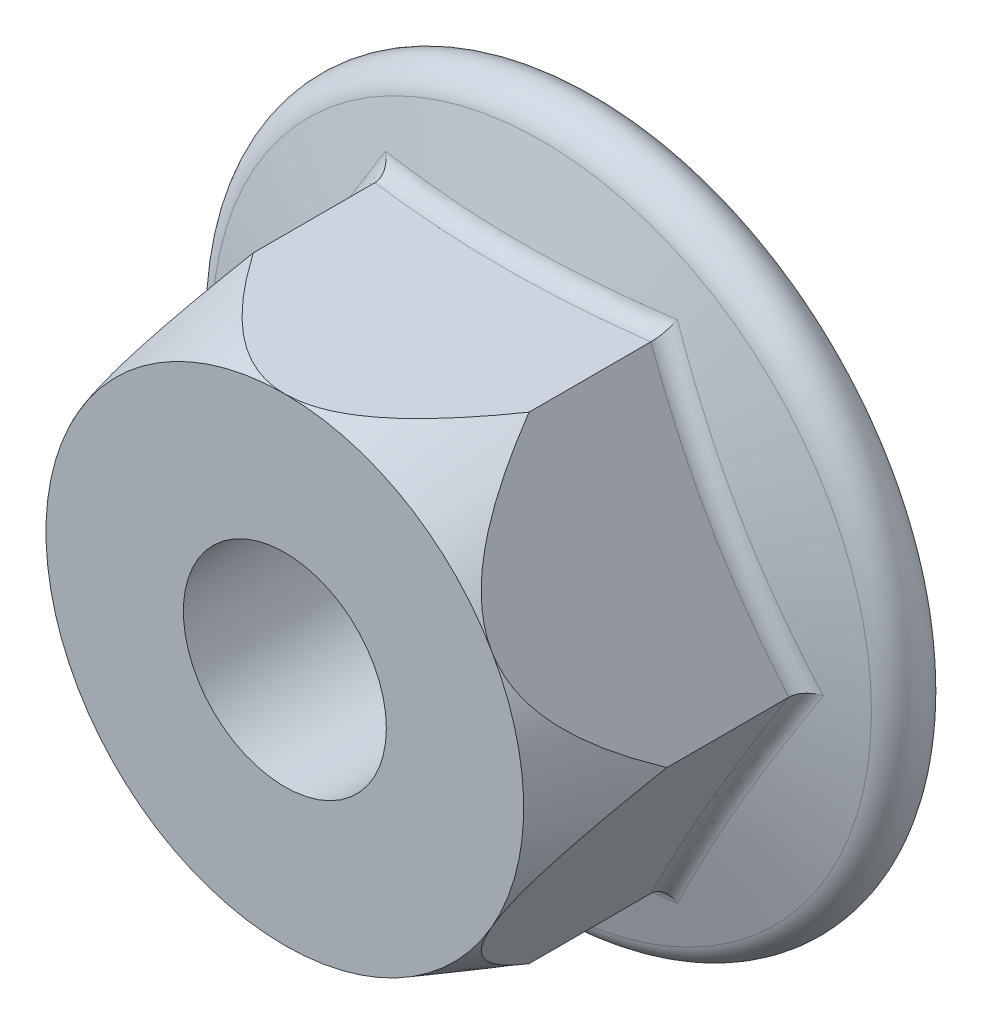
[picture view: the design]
ISO-10303-21;
HEADER;
FILE_DESCRIPTION(('STEP AP214'),'2;1');
FILE_NAME('part.step','',(''),(''),'','','');
FILE_SCHEMA(('AUTOMOTIVE_DESIGN { 1 0 10303 214 1 1 1 1 }'));
ENDSEC;
DATA;
#1=APPLICATION_CONTEXT('core data for automotive mechanical design processes');
#2=APPLICATION_PROTOCOL_DEFINITION('international standard','automotive_design',2000,#1);
#3=PRODUCT_CONTEXT('',#1,'mechanical');
#4=PRODUCT('Part','Part','',(#3));
#5=PRODUCT_RELATED_PRODUCT_CATEGORY('part','',(#4));
#6=PRODUCT_DEFINITION_FORMATION('','',#4);
#7=PRODUCT_DEFINITION_CONTEXT('part definition',#1,'design');
#8=PRODUCT_DEFINITION('design','',#6,#7);
#9=PRODUCT_DEFINITION_SHAPE('','',#8);
#10=(LENGTH_UNIT() NAMED_UNIT(*) SI_UNIT(.MILLI.,.METRE.));
#11=(NAMED_UNIT(*) PLANE_ANGLE_UNIT() SI_UNIT($,.RADIAN.));
#12=(NAMED_UNIT(*) SI_UNIT($,.STERADIAN.) SOLID_ANGLE_UNIT());
#13=UNCERTAINTY_MEASURE_WITH_UNIT(LENGTH_MEASURE(1.E-05),#10,'distance_accuracy_value','');
#14=(GEOMETRIC_REPRESENTATION_CONTEXT(3) GLOBAL_UNCERTAINTY_ASSIGNED_CONTEXT((#13)) GLOBAL_UNIT_ASSIGNED_CONTEXT((#10,
#11,#12)) REPRESENTATION_CONTEXT('',''));
#15=CARTESIAN_POINT('',(0.,0.,0.));
#16=DIRECTION('',(0.,0.,1.));
#17=DIRECTION('',(1.,0.,0.));
#18=AXIS2_PLACEMENT_3D('',#15,#16,#17);
#19=CARTESIAN_POINT('',(2.30940107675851,-4.,-5.3));
#20=DIRECTION('',(0.866025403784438,-0.5,0.));
#21=DIRECTION('',(0.5,0.866025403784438,0.));
#22=AXIS2_PLACEMENT_3D('',#19,#20,#21);
#23=PLANE('',#22);
#24=DIRECTION('',(0.,0.,1.));
#25=VECTOR('',#24,1.);
#26=CARTESIAN_POINT('',(2.30940107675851,-4.,-5.3));
#27=LINE('',#26,#25);
#28=CARTESIAN_POINT('',(2.30940107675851,-4.,-3.81737471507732));
#29=VERTEX_POINT('',#28);
#30=CARTESIAN_POINT('',(2.30940107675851,-4.,-1.78));
#31=VERTEX_POINT('',#30);
#32=EDGE_CURVE('E175',#29,#31,#27,.T.);
#33=ORIENTED_EDGE('',*,*,#32,.F.);
#34=CARTESIAN_POINT('',(-7.61123118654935,-21.1830391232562,-8.55558985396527));
#35=CARTESIAN_POINT('',(-7.57491118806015,-21.1201310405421,-8.83174684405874));
#36=CARTESIAN_POINT('',(-7.32612653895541,-21.2596298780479,-8.84536760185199));
#37=CARTESIAN_POINT('',(-7.14834835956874,-20.3813025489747,-8.31214514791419));
#38=CARTESIAN_POINT('',(-7.11245730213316,-20.3191374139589,-8.58793733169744));
#39=CARTESIAN_POINT('',(-6.863826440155,-20.4576960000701,-8.60192289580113));
#40=CARTESIAN_POINT('',(-6.68541201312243,-19.5794732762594,-8.06910132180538));
#41=CARTESIAN_POINT('',(-6.64988004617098,-19.5179301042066,-8.34442822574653));
#42=CARTESIAN_POINT('',(-6.4015282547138,-19.6556514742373,-8.35887906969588));
#43=CARTESIAN_POINT('',(-5.75902963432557,-17.9749319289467,-7.58440903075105));
#44=CARTESIAN_POINT('',(-5.72390360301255,-17.9140918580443,-7.8584468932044));
#45=CARTESIAN_POINT('',(-5.47663891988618,-18.0506377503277,-7.874186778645));
#46=CARTESIAN_POINT('',(-5.29558346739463,-17.1722196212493,-7.34276159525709));
#47=CARTESIAN_POINT('',(-5.26080405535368,-17.111979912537,-7.61612935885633));
#48=CARTESIAN_POINT('',(-5.01404777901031,-17.2476682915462,-7.63253934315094));
#49=CARTESIAN_POINT('',(-4.35666662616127,-15.545967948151,-6.85569776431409));
#50=CARTESIAN_POINT('',(-4.32238974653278,-15.4865986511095,-7.12731783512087));
#51=CARTESIAN_POINT('',(-4.07718877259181,-15.6208476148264,-7.14547551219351));
#52=CARTESIAN_POINT('',(-3.88118826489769,-14.7224152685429,-6.61034060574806));
#53=CARTESIAN_POINT('',(-3.84748393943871,-14.6640376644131,-6.88108543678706));
#54=CARTESIAN_POINT('',(-3.60292146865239,-14.7969818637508,-6.9001183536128));
#55=CARTESIAN_POINT('',(-2.93002562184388,-13.0749532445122,-6.12383947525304));
#56=CARTESIAN_POINT('',(-2.89709389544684,-13.0179138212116,-6.39216776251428));
#57=CARTESIAN_POINT('',(-2.65474442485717,-13.1488478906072,-6.41361722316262));
#58=CARTESIAN_POINT('',(-2.45434168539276,-12.2510444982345,-5.88269281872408));
#59=CARTESIAN_POINT('',(-2.4223507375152,-12.1956345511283,-6.14984390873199));
#60=CARTESIAN_POINT('',(-2.18083465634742,-12.3245802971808,-6.17247056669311));
#61=CARTESIAN_POINT('',(-1.75255773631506,-11.0355190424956,-5.53294307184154));
#62=CARTESIAN_POINT('',(-1.72021507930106,-10.9794999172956,-5.79690487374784));
#63=CARTESIAN_POINT('',(-1.48243860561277,-11.1085537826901,-5.82272081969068));
#64=CARTESIAN_POINT('',(-1.52682941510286,-10.6445461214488,-5.42136208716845));
#65=CARTESIAN_POINT('',(-1.49489405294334,-10.5892324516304,-5.6844641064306));
#66=CARTESIAN_POINT('',(-1.25791724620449,-10.7174240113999,-5.71113983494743));
#67=CARTESIAN_POINT('',(-1.07506727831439,-9.86207114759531,-5.20067849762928));
#68=CARTESIAN_POINT('',(-1.04389094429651,-9.8080721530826,-5.46179745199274));
#69=CARTESIAN_POINT('',(-0.808900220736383,-9.93467370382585,-5.49045624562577));
#70=CARTESIAN_POINT('',(-0.849033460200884,-9.47056909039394,-5.09157591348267));
#71=CARTESIAN_POINT('',(-0.81838657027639,-9.41748711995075,-5.35165029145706));
#72=CARTESIAN_POINT('',(-0.584404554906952,-9.54305316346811,-5.38135366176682));
#73=CARTESIAN_POINT('',(-0.396069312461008,-8.68601217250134,-4.87674409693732));
#74=CARTESIAN_POINT('',(-0.366445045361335,-8.63470143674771,-5.1344034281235));
#75=CARTESIAN_POINT('',(-0.134983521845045,-8.75835650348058,-5.16652184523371));
#76=CARTESIAN_POINT('',(-0.169138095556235,-8.29295577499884,-4.77102231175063));
#77=CARTESIAN_POINT('',(-0.140236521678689,-8.24289678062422,-5.02740455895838));
#78=CARTESIAN_POINT('',(0.0899417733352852,-8.36527904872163,-5.06080005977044));
#79=CARTESIAN_POINT('',(0.285345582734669,-7.50576695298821,-4.56505534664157));
#80=CARTESIAN_POINT('',(0.312820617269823,-7.45817879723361,-4.81848453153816));
#81=CARTESIAN_POINT('',(0.539752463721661,-7.57827322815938,-4.85483309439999));
#82=CARTESIAN_POINT('',(0.512898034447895,-7.11163454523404,-4.46481008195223));
#83=CARTESIAN_POINT('',(0.539373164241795,-7.06577827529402,-4.71666888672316));
#84=CARTESIAN_POINT('',(0.764637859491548,-7.18434487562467,-4.75458782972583));
#85=CARTESIAN_POINT('',(0.965655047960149,-6.32743639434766,-4.27436791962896));
#86=CARTESIAN_POINT('',(0.990117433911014,-6.28506629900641,-4.52267428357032));
#87=CARTESIAN_POINT('',(1.21118051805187,-6.40105138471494,-4.5641456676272));
#88=CARTESIAN_POINT('',(1.19084639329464,-5.93739354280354,-4.184047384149));
#89=CARTESIAN_POINT('',(1.21394070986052,-5.89739301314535,-4.43047216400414));
#90=CARTESIAN_POINT('',(1.4328377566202,-6.01170196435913,-4.47382513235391));
#91=CARTESIAN_POINT('',(1.64257926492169,-5.15496925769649,-4.01707291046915));
#92=CARTESIAN_POINT('',(1.66271797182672,-5.12008799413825,-4.25943247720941));
#93=CARTESIAN_POINT('',(1.87635689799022,-5.23168790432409,-4.30685065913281));
#94=CARTESIAN_POINT('',(1.86912112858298,-4.7625872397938,-3.94042254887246));
#95=CARTESIAN_POINT('',(1.8873877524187,-4.73094851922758,-4.18059335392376));
#96=CARTESIAN_POINT('',(2.09821883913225,-4.84102294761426,-4.23020029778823));
#97=CARTESIAN_POINT('',(2.32311926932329,-3.97623939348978,-3.80992031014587));
#98=CARTESIAN_POINT('',(2.337137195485,-3.95195963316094,-4.04600903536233));
#99=CARTESIAN_POINT('',(2.54185284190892,-4.06009928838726,-4.09969805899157));
#100=CARTESIAN_POINT('',(2.55056920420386,-3.5822845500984,-3.75598635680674));
#101=CARTESIAN_POINT('',(2.56229119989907,-3.5619814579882,-3.98996132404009));
#102=CARTESIAN_POINT('',(2.76362228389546,-3.66984429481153,-4.04576410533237));
#103=CARTESIAN_POINT('',(2.89270035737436,-2.98969600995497,-3.70029165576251));
#104=CARTESIAN_POINT('',(2.90051641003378,-2.97615820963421,-3.93207627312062));
#105=CARTESIAN_POINT('',(3.09747471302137,-3.08479578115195,-3.99006940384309));
#106=CARTESIAN_POINT('',(3.00686662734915,-2.791954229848,-3.68592836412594));
#107=CARTESIAN_POINT('',(3.0132311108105,-2.78093062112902,-3.91711556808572));
#108=CARTESIAN_POINT('',(3.20892257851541,-2.88989781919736,-3.97570611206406));
#109=CARTESIAN_POINT('',(3.23539205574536,-2.39613657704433,-3.66664521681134));
#110=CARTESIAN_POINT('',(3.23857973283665,-2.39061535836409,-3.89705602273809));
#111=CARTESIAN_POINT('',(3.4323757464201,-2.5003310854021,-3.95642296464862));
#112=CARTESIAN_POINT('',(3.34975118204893,-2.19806075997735,-3.66172391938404));
#113=CARTESIAN_POINT('',(3.35139245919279,-2.19521798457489,-3.89192321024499));
#114=CARTESIAN_POINT('',(3.544380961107,-2.30566228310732,-3.95150166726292));
#115=CARTESIAN_POINT('',(3.50978592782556,-1.92087244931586,-3.66171696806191));
#116=CARTESIAN_POINT('',(3.50913015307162,-1.92200828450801,-3.89191458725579));
#117=CARTESIAN_POINT('',(3.70152527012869,-2.03347809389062,-3.95149471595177));
#118=CARTESIAN_POINT('',(3.55546885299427,-1.8417473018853,-3.6624996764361));
#119=CARTESIAN_POINT('',(3.55416444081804,-1.84400661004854,-3.89273007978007));
#120=CARTESIAN_POINT('',(3.74642913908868,-1.95580835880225,-3.95227742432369));
#121=CARTESIAN_POINT('',(3.64682245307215,-1.68351822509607,-3.66561475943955));
#122=CARTESIAN_POINT('',(3.64421400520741,-1.68803618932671,-3.8959727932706));
#123=CARTESIAN_POINT('',(3.83632424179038,-1.80052369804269,-3.95539250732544));
#124=CARTESIAN_POINT('',(3.69249312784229,-1.60441429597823,-3.66794715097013));
#125=CARTESIAN_POINT('',(3.68924157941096,-1.61004614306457,-3.89840092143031));
#126=CARTESIAN_POINT('',(3.88131547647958,-1.72290877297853,-3.95772489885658));
#127=CARTESIAN_POINT('',(3.82950397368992,-1.36710454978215,-3.67723166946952));
#128=CARTESIAN_POINT('',(3.82436213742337,-1.37601047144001,-3.90806527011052));
#129=CARTESIAN_POINT('',(4.01644472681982,-1.49009005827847,-3.96700941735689));
#130=CARTESIAN_POINT('',(3.92080623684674,-1.20896439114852,-3.68647110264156));
#131=CARTESIAN_POINT('',(3.91445378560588,-1.21996715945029,-3.91768701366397));
#132=CARTESIAN_POINT('',(4.10670223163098,-1.33497476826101,-3.97624885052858));
#133=CARTESIAN_POINT('',(4.19477955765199,-0.734428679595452,-3.72273800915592));
#134=CARTESIAN_POINT('',(4.18503615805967,-0.751304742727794,-3.95540495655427));
#135=CARTESIAN_POINT('',(4.37816374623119,-0.869375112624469,-4.01251575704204));
#136=CARTESIAN_POINT('',(4.3771741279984,-0.418512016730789,-3.75831137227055));
#137=CARTESIAN_POINT('',(4.36539673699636,-0.438911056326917,-3.99241678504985));
#138=CARTESIAN_POINT('',(4.55971999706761,-0.559219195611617,-4.04808912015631));
#139=CARTESIAN_POINT('',(4.65065751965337,0.0551751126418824,-3.82480471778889));
#140=CARTESIAN_POINT('',(4.63549818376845,0.0289183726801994,-4.0610737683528));
#141=CARTESIAN_POINT('',(4.83278724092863,-0.0933721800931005,-4.1145824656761));
#142=CARTESIAN_POINT('',(4.74217033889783,0.213679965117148,-3.8492840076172));
#143=CARTESIAN_POINT('',(4.726080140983,0.18581092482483,-4.0863647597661));
#144=CARTESIAN_POINT('',(4.92430330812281,0.0626443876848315,-4.13906175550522));
#145=CARTESIAN_POINT('',(4.92494243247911,0.530250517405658,-3.90190705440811));
#146=CARTESIAN_POINT('',(4.90710566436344,0.499356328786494,-4.14062943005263));
#147=CARTESIAN_POINT('',(5.10728053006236,0.374525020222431,-4.19168480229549));
#148=CARTESIAN_POINT('',(5.01620168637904,0.688316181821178,-3.93005109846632));
#149=CARTESIAN_POINT('',(4.99755743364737,0.656023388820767,-4.16961875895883));
#150=CARTESIAN_POINT('',(5.19874167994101,0.530389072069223,-4.21982884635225));
#151=CARTESIAN_POINT('',(5.19824692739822,1.00362778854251,-3.9892892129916));
#152=CARTESIAN_POINT('',(5.17809955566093,0.968731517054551,-4.23053091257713));
#153=CARTESIAN_POINT('',(5.38132017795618,0.84158462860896,-4.2790669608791));
#154=CARTESIAN_POINT('',(5.28903352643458,1.16087479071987,-4.0203758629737));
#155=CARTESIAN_POINT('',(5.26818514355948,1.12476433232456,-4.26245525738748));
#156=CARTESIAN_POINT('',(5.47243781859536,0.996916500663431,-4.31015361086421));
#157=CARTESIAN_POINT('',(5.47036783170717,1.4749550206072,-4.0850307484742));
#158=CARTESIAN_POINT('',(5.44823424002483,1.43661851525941,-4.32876154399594));
#159=CARTESIAN_POINT('',(5.65451402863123,1.30742143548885,-4.37480849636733));
#160=CARTESIAN_POINT('',(5.56091558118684,1.63178832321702,-4.11859849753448));
#161=CARTESIAN_POINT('',(5.53818436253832,1.59241669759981,-4.36314658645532));
#162=CARTESIAN_POINT('',(5.74547262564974,1.46259452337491,-4.40837624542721));
#163=CARTESIAN_POINT('',(5.65136623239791,1.78845344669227,-4.15314978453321));
#164=CARTESIAN_POINT('',(5.62793136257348,1.74786306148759,-4.3984261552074));
#165=CARTESIAN_POINT('',(5.83634927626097,1.61771364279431,-4.44292753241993));
#166=(BOUNDED_SURFACE() B_SPLINE_SURFACE(3,2,((#34,#35,#36),(#37,#38,#39),(#40,#41,#42),(#43,
#44,#45),(#46,#47,#48),(#49,#50,#51),(#52,#53,#54),(#55,#56,#57),(#58,#59,#60),(#61,#62,#63),
(#64,#65,#66),(#67,#68,#69),(#70,#71,#72),(#73,#74,#75),(#76,#77,#78),(#79,#80,#81),(#82,#83,
#84),(#85,#86,#87),(#88,#89,#90),(#91,#92,#93),(#94,#95,#96),(#97,#98,#99),(#100,#101,#102),
(#103,#104,#105),(#106,#107,#108),(#109,#110,#111),(#112,#113,#114),(#115,#116,#117),(#118,#119,
#120),(#121,#122,#123),(#124,#125,#126),(#127,#128,#129),(#130,#131,#132),(#133,#134,#135),
(#136,#137,#138),(#139,#140,#141),(#142,#143,#144),(#145,#146,#147),(#148,#149,#150),(#151,#152,
#153),(#154,#155,#156),(#157,#158,#159),(#160,#161,#162),(#163,#164,#165)),.UNSPECIFIED.,.F.,
.F.,.F.) B_SPLINE_SURFACE_WITH_KNOTS((4,2,2,2,2,2,2,2,2,2,2,2,2,2,2,2,2,2,2,2,2,4),(3,3),(0.,
2.87172082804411,5.74534141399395,8.69163587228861,11.6359776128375,13.0310968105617,
14.4262276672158,15.8242453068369,17.222241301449,18.600159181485,19.978437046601,
21.3516914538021,22.0378780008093,22.7239597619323,22.9980573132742,23.272157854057,
23.8205791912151,24.9194760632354,25.4734222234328,26.0274118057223,26.5800398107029,
27.1325597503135),(0.,1.),
.UNSPECIFIED.) GEOMETRIC_REPRESENTATION_ITEM() RATIONAL_B_SPLINE_SURFACE(((1.,0.72433504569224,
1.),(1.,0.72502874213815,1.),(1.,0.725787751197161,1.),(1.,0.727541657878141,1.),(1.,
0.728536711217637,1.),(1.,0.730896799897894,1.),(1.,0.732270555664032,1.),(1.,0.73558815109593,
1.),(1.,0.737531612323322,1.),(1.,0.741117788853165,1.),(1.,0.742380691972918,1.),(1.,
0.745198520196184,1.),(1.,0.74675344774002,1.),(1.,0.750247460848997,1.),(1.,0.752187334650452,
1.),(1.,0.756556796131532,1.),(1.,0.758986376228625,1.),(1.,0.764379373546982,1.),(1.,
0.767334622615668,1.),(1.,0.773723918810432,1.),(1.,0.777158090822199,1.),(1.,0.783844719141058,
1.),(1.,0.787097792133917,1.),(1.,0.790686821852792,1.),(1.,0.791667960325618,1.),(1.,
0.79300075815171,1.),(1.,0.793352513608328,1.),(1.,0.793353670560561,1.),(1.,0.793297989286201,
1.),(1.,0.793078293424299,1.),(1.,0.792914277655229,1.),(1.,0.792266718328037,1.),(1.,
0.791627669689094,1.),(1.,0.789211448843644,1.),(1.,0.786935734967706,1.),(1.,0.783154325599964,
1.),(1.,0.78182642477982,1.),(1.,0.779132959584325,1.),(1.,0.777767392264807,1.),(1.,
0.775062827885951,1.),(1.,0.773723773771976,1.),(1.,0.771102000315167,1.),(1.,0.769819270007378,
1.),(1.,0.768581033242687,1.))) REPRESENTATION_ITEM('') SURFACE());
#167=CARTESIAN_POINT('',(-7.61123118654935,-21.1830391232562,-8.55558985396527));
#168=CARTESIAN_POINT('',(-7.14834835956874,-20.3813025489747,-8.31214514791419));
#169=CARTESIAN_POINT('',(-6.68541201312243,-19.5794732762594,-8.06910132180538));
#170=CARTESIAN_POINT('',(-5.75902963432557,-17.9749319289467,-7.58440903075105));
#171=CARTESIAN_POINT('',(-5.29558346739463,-17.1722196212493,-7.3427615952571));
#172=CARTESIAN_POINT('',(-4.35666662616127,-15.545967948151,-6.85569776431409));
#173=CARTESIAN_POINT('',(-3.88118826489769,-14.7224152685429,-6.61034060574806));
#174=CARTESIAN_POINT('',(-2.93002562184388,-13.0749532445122,-6.12383947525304));
#175=CARTESIAN_POINT('',(-2.45434168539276,-12.2510444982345,-5.88269281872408));
#176=CARTESIAN_POINT('',(-1.75255773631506,-11.0355190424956,-5.53294307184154));
#177=CARTESIAN_POINT('',(-1.52682941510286,-10.6445461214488,-5.42136208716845));
#178=CARTESIAN_POINT('',(-1.07506727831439,-9.86207114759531,-5.20067849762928));
#179=CARTESIAN_POINT('',(-0.849033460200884,-9.47056909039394,-5.09157591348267));
#180=CARTESIAN_POINT('',(-0.396069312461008,-8.68601217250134,-4.87674409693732));
#181=CARTESIAN_POINT('',(-0.169138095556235,-8.29295577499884,-4.77102231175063));
#182=CARTESIAN_POINT('',(0.285345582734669,-7.50576695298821,-4.56505534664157));
#183=CARTESIAN_POINT('',(0.512898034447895,-7.11163454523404,-4.46481008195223));
#184=CARTESIAN_POINT('',(0.965655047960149,-6.32743639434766,-4.27436791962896));
#185=CARTESIAN_POINT('',(1.19084639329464,-5.93739354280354,-4.184047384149));
#186=CARTESIAN_POINT('',(1.64257926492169,-5.15496925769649,-4.01707291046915));
#187=CARTESIAN_POINT('',(1.86912112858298,-4.7625872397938,-3.94042254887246));
#188=CARTESIAN_POINT('',(2.32311926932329,-3.97623939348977,-3.80992031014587));
#189=CARTESIAN_POINT('',(2.55056920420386,-3.5822845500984,-3.75598635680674));
#190=CARTESIAN_POINT('',(2.89270035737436,-2.98969600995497,-3.70029165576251));
#191=CARTESIAN_POINT('',(3.00686662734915,-2.791954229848,-3.68592836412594));
#192=CARTESIAN_POINT('',(3.23539205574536,-2.39613657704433,-3.66664521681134));
#193=CARTESIAN_POINT('',(3.34975118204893,-2.19806075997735,-3.66172391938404));
#194=CARTESIAN_POINT('',(3.50978592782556,-1.92087244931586,-3.66171696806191));
#195=CARTESIAN_POINT('',(3.55546885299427,-1.8417473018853,-3.6624996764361));
#196=CARTESIAN_POINT('',(3.64682245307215,-1.68351822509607,-3.66561475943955));
#197=CARTESIAN_POINT('',(3.69249312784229,-1.60441429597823,-3.66794715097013));
#198=CARTESIAN_POINT('',(3.82950397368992,-1.36710454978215,-3.67723166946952));
#199=CARTESIAN_POINT('',(3.92080623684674,-1.20896439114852,-3.68647110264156));
#200=CARTESIAN_POINT('',(4.19477955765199,-0.734428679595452,-3.72273800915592));
#201=CARTESIAN_POINT('',(4.3771741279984,-0.41851201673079,-3.75831137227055));
#202=CARTESIAN_POINT('',(4.65065751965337,0.0551751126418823,-3.82480471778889));
#203=CARTESIAN_POINT('',(4.74217033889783,0.213679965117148,-3.8492840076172));
#204=CARTESIAN_POINT('',(4.92494243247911,0.530250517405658,-3.90190705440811));
#205=CARTESIAN_POINT('',(5.01620168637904,0.688316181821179,-3.93005109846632));
#206=CARTESIAN_POINT('',(5.19824692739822,1.00362778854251,-3.9892892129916));
#207=CARTESIAN_POINT('',(5.28903352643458,1.16087479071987,-4.0203758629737));
#208=CARTESIAN_POINT('',(5.47036783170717,1.4749550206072,-4.0850307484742));
#209=CARTESIAN_POINT('',(5.56091558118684,1.63178832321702,-4.11859849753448));
#210=CARTESIAN_POINT('',(5.65136623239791,1.78845344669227,-4.15314978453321));
#211=B_SPLINE_CURVE_WITH_KNOTS('',3,(#167,#168,#169,#170,#171,#172,#173,#174,#175,#176,#177,
#178,#179,#180,#181,#182,#183,#184,#185,#186,#187,#188,#189,#190,#191,#192,#193,#194,#195,#196,
#197,#198,#199,#200,#201,#202,#203,#204,#205,#206,#207,#208,#209,#210),.UNSPECIFIED.,.F.,.F.,(4,
2,2,2,2,2,2,2,2,2,2,2,2,2,2,2,2,2,2,2,2,4),(0.,2.87172082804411,5.74534141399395,
8.69163587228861,11.6359776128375,13.0310968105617,14.4262276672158,15.8242453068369,
17.222241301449,18.600159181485,19.978437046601,21.3516914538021,22.0378780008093,
22.7239597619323,22.9980573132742,23.272157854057,23.8205791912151,24.9194760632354,
25.4734222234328,26.0274118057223,26.5800398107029,27.1325597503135),.UNSPECIFIED.);
#212=CARTESIAN_POINT('',(4.61880215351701,0.,-3.81737471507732));
#213=VERTEX_POINT('',#212);
#214=EDGE_CURVE('E329',#29,#213,#211,.T.);
#215=ORIENTED_EDGE('',*,*,#214,.T.);
#216=DIRECTION('',(0.,0.,1.));
#217=VECTOR('',#216,1.);
#218=CARTESIAN_POINT('',(4.61880215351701,0.,-5.3));
#219=LINE('',#218,#217);
#220=CARTESIAN_POINT('',(4.61880215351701,0.,-1.78));
#221=VERTEX_POINT('',#220);
#222=EDGE_CURVE('E157',#213,#221,#219,.T.);
#223=ORIENTED_EDGE('',*,*,#222,.T.);
#224=CARTESIAN_POINT('',(2.30933154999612,-4.00012042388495,-1.78020000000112));
#225=CARTESIAN_POINT('',(2.329672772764,-3.96488839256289,-1.72169220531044));
#226=CARTESIAN_POINT('',(2.35028187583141,-3.92919237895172,-1.66355827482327));
#227=CARTESIAN_POINT('',(2.3921122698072,-3.85674001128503,-1.54815677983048));
#228=CARTESIAN_POINT('',(2.41333371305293,-3.81998339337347,-1.4908894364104));
#229=CARTESIAN_POINT('',(2.47830561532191,-3.70744875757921,-1.31984609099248));
#230=CARTESIAN_POINT('',(2.52309209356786,-3.62987630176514,-1.20761921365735));
#231=CARTESIAN_POINT('',(2.61818869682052,-3.46516415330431,-0.984245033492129));
#232=CARTESIAN_POINT('',(2.66865503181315,-3.37775389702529,-0.873361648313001));
#233=CARTESIAN_POINT('',(2.77442244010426,-3.19455937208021,-0.661563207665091));
#234=CARTESIAN_POINT('',(2.82970800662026,-3.09880196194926,-0.560618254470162));
#235=CARTESIAN_POINT('',(2.9106528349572,-2.95860140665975,-0.431782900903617));
#236=CARTESIAN_POINT('',(2.93362248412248,-2.91881680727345,-0.397143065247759));
#237=CARTESIAN_POINT('',(2.98058363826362,-2.83747770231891,-0.330748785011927));
#238=CARTESIAN_POINT('',(3.00457540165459,-2.79592274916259,-0.298995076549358));
#239=CARTESIAN_POINT('',(3.07782339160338,-2.66905350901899,-0.209445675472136));
#240=CARTESIAN_POINT('',(3.12873106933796,-2.58087882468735,-0.156734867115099));
#241=CARTESIAN_POINT('',(3.22066888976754,-2.42163784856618,-0.0827968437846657));
#242=CARTESIAN_POINT('',(3.26075482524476,-2.35220697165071,-0.0569308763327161));
#243=CARTESIAN_POINT('',(3.34254671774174,-2.21053925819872,-0.0188566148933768));
#244=CARTESIAN_POINT('',(3.38425146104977,-2.1383045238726,-0.00663828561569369));
#245=CARTESIAN_POINT('',(3.46826163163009,-1.99279464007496,0.00251875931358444));
#246=CARTESIAN_POINT('',(3.5105687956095,-1.91951648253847,-0.000603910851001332));
#247=CARTESIAN_POINT('',(3.59423504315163,-1.77460229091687,-0.0218132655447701));
#248=CARTESIAN_POINT('',(3.63559318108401,-1.70296789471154,-0.0399142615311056));
#249=CARTESIAN_POINT('',(3.72775187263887,-1.54334435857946,-0.0957585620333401));
#250=CARTESIAN_POINT('',(3.77791738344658,-1.45645514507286,-0.137607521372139));
#251=CARTESIAN_POINT('',(3.87438442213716,-1.28936933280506,-0.236407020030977));
#252=CARTESIAN_POINT('',(3.92067460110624,-1.20919239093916,-0.293400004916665));
#253=CARTESIAN_POINT('',(4.00728859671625,-1.05917254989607,-0.414494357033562));
#254=CARTESIAN_POINT('',(4.04779671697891,-0.989010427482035,-0.478080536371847));
#255=CARTESIAN_POINT('',(4.1260142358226,-0.853533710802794,-0.611867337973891));
#256=CARTESIAN_POINT('',(4.16372066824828,-0.788224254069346,-0.682074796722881));
#257=CARTESIAN_POINT('',(4.23687359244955,-0.661519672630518,-0.827445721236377));
#258=CARTESIAN_POINT('',(4.27231261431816,-0.600137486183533,-0.902624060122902));
#259=CARTESIAN_POINT('',(4.34118808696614,-0.48084166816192,-1.05648002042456));
#260=CARTESIAN_POINT('',(4.37462539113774,-0.422926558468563,-1.13515612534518));
#261=CARTESIAN_POINT('',(4.44457071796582,-0.301777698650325,-1.30677603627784));
#262=CARTESIAN_POINT('',(4.48082190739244,-0.238988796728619,-1.40013569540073));
#263=CARTESIAN_POINT('',(4.55123163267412,-0.117035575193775,-1.58876843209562));
#264=CARTESIAN_POINT('',(4.58540498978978,-0.0578455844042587,-1.68401931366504));
#265=CARTESIAN_POINT('',(4.61887168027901,0.000120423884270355,-1.7802));
#266=B_SPLINE_CURVE_WITH_KNOTS('',3,(#224,#225,#226,#227,#228,#229,#230,#231,#232,#233,#234,
#235,#236,#237,#238,#239,#240,#241,#242,#243,#244,#245,#246,#247,#248,#249,#250,#251,#252,#253,
#254,#255,#256,#257,#258,#259,#260,#261,#262,#263,#264,#265),.UNSPECIFIED.,.F.,.F.,(4,2,2,2,2,2,
2,2,2,2,2,2,2,2,2,2,2,2,2,2,4),(0.,0.213777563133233,0.427608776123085,0.858145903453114,
1.30759304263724,1.75564391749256,1.92815043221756,2.10070082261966,2.44287249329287,
2.69463411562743,2.9462104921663,3.19879434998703,3.45161982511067,3.77590275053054,
4.10110434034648,4.40960953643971,4.71843682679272,5.02823407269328,5.33789828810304,
5.6924202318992,6.0440116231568),.UNSPECIFIED.);
#267=CARTESIAN_POINT('',(3.46410161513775,-2.,0.));
#268=VERTEX_POINT('',#267);
#269=EDGE_CURVE('E212',#268,#221,#266,.T.);
#270=ORIENTED_EDGE('',*,*,#269,.F.);
#271=EDGE_CURVE('E519',#31,#268,#266,.T.);
#272=ORIENTED_EDGE('',*,*,#271,.F.);
#273=EDGE_LOOP('',(#33,#215,#223,#270,#272));
#274=FACE_BOUND('',#273,.T.);
#275=ADVANCED_FACE('F35',(#274),#23,.T.);
#276=CARTESIAN_POINT('',(-2.3094010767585,-4.,-5.3));
#277=DIRECTION('',(0.,-1.,0.));
#278=DIRECTION('',(1.,0.,0.));
#279=AXIS2_PLACEMENT_3D('',#276,#277,#278);
#280=PLANE('',#279);
#281=DIRECTION('',(0.,0.,1.));
#282=VECTOR('',#281,1.);
#283=CARTESIAN_POINT('',(-2.3094010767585,-4.,-5.3));
#284=LINE('',#283,#282);
#285=CARTESIAN_POINT('',(-2.3094010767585,-4.,-3.81737471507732));
#286=VERTEX_POINT('',#285);
#287=CARTESIAN_POINT('',(-2.3094010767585,-4.,-1.78));
#288=VERTEX_POINT('',#287);
#289=EDGE_CURVE('E139',#286,#288,#284,.T.);
#290=ORIENTED_EDGE('',*,*,#289,.F.);
#291=CARTESIAN_POINT('',(-22.1112237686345,-4.00000000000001,-8.54521545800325));
#292=CARTESIAN_POINT('',(-22.0385943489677,-4.00000000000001,-8.82135013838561));
#293=CARTESIAN_POINT('',(-22.0350059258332,-4.28517781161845,-8.83499320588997));
#294=CARTESIAN_POINT('',(-21.1869548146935,-4.00000000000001,-8.30218033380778));
#295=CARTESIAN_POINT('',(-21.1151840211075,-4.00000000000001,-8.57794941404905));
#296=CARTESIAN_POINT('',(-21.1108578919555,-4.28457344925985,-8.59195808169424));
#297=CARTESIAN_POINT('',(-20.2625786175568,-4.00000000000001,-8.05954685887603));
#298=CARTESIAN_POINT('',(-20.1915266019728,-4.00000000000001,-8.33484970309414));
#299=CARTESIAN_POINT('',(-20.186614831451,-4.28391199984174,-8.34932460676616));
#300=CARTESIAN_POINT('',(-18.4128085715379,-4.00000000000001,-7.57567895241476));
#301=CARTESIAN_POINT('',(-18.3425699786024,-4.00000000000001,-7.8496906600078));
#302=CARTESIAN_POINT('',(-18.3371834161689,-4.28238013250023,-7.86545670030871));
#303=CARTESIAN_POINT('',(-17.4874144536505,-4.00000000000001,-7.33444554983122));
#304=CARTESIAN_POINT('',(-17.4178700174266,-4.,-7.60778598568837));
#305=CARTESIAN_POINT('',(-17.4119948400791,-4.28150957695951,-7.62422329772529));
#306=CARTESIAN_POINT('',(-15.6125978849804,-4.00000000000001,-6.84822064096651));
#307=CARTESIAN_POINT('',(-15.5440609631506,-4.,-7.11981074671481));
#308=CARTESIAN_POINT('',(-15.5377163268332,-4.27943938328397,-7.13799838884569));
#309=CARTESIAN_POINT('',(-14.6631600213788,-4.,-6.60328852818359));
#310=CARTESIAN_POINT('',(-14.5957695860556,-4.,-6.87400182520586));
#311=CARTESIAN_POINT('',(-14.5886140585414,-4.2782319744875,-6.89306627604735));
#312=CARTESIAN_POINT('',(-12.7638679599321,-4.,-6.11764487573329));
#313=CARTESIAN_POINT('',(-12.6980262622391,-4.,-6.38593809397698));
#314=CARTESIAN_POINT('',(-12.6902361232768,-4.27530549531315,-6.4074226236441));
#315=CARTESIAN_POINT('',(-11.8140144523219,-4.,-5.87693065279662));
#316=CARTESIAN_POINT('',(-11.750056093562,-4.,-6.14404449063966));
#317=CARTESIAN_POINT('',(-11.7409609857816,-4.2735867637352,-6.16670840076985));
#318=CARTESIAN_POINT('',(-10.4126820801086,-4.,-5.52783081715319));
#319=CARTESIAN_POINT('',(-10.3480253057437,-4.,-5.79175246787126));
#320=CARTESIAN_POINT('',(-10.3408930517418,-4.27039733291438,-5.81760856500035));
#321=CARTESIAN_POINT('',(-9.9619478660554,-4.,-5.41646145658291));
#322=CARTESIAN_POINT('',(-9.8981071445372,-4.,-5.67952220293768));
#323=CARTESIAN_POINT('',(-9.8906281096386,-4.26927197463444,-5.70623920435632));
#324=CARTESIAN_POINT('',(-9.05986760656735,-4.,-5.19620577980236));
#325=CARTESIAN_POINT('',(-8.99754862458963,-4.,-5.45728129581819));
#326=CARTESIAN_POINT('',(-8.98968585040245,-4.26675342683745,-5.48598352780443));
#327=CARTESIAN_POINT('',(-8.60852155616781,-4.,-5.08731948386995));
#328=CARTESIAN_POINT('',(-8.54726330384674,-4.,-5.34734923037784));
#329=CARTESIAN_POINT('',(-8.53900852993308,-4.26536023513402,-5.37709723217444));
#330=CARTESIAN_POINT('',(-7.70403865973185,-4.,-4.87292751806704));
#331=CARTESIAN_POINT('',(-7.64483046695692,-4.,-5.13054011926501));
#332=CARTESIAN_POINT('',(-7.63618162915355,-4.26221811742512,-5.16270526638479));
#333=CARTESIAN_POINT('',(-7.25090004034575,-4.,-4.76742929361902));
#334=CARTESIAN_POINT('',(-7.19313947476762,-4.,-5.02376363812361));
#335=CARTESIAN_POINT('',(-7.1840309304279,-4.26046846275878,-5.05720704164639));
#336=CARTESIAN_POINT('',(-6.3433786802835,-4.,-4.5619180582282));
#337=CARTESIAN_POINT('',(-6.28847741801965,-4.,-4.81529776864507));
#338=CARTESIAN_POINT('',(-6.27901227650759,-4.25650944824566,-4.85169580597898));
#339=CARTESIAN_POINT('',(-5.8889959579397,-4.,-4.46190496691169));
#340=CARTESIAN_POINT('',(-5.83609699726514,-4.,-4.7137134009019));
#341=CARTESIAN_POINT('',(-5.82614433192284,-4.25430009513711,-4.75168271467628));
#342=CARTESIAN_POINT('',(-4.9849139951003,-4.,-4.27193449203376));
#343=CARTESIAN_POINT('',(-4.93604839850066,-4.,-4.5201905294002));
#344=CARTESIAN_POINT('',(-4.92596362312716,-4.24936870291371,-4.56171224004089));
#345=CARTESIAN_POINT('',(-4.53524119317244,-4.,-4.18185333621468));
#346=CARTESIAN_POINT('',(-4.48911412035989,-4.,-4.42822784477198));
#347=CARTESIAN_POINT('',(-4.47866446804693,-4.2466544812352,-4.47163108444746));
#348=CARTESIAN_POINT('',(-3.63319803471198,-4.,-4.01536776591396));
#349=CARTESIAN_POINT('',(-3.5929902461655,-4.,-4.25768058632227));
#350=CARTESIAN_POINT('',(-3.58282861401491,-4.24074911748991,-4.30514551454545));
#351=CARTESIAN_POINT('',(-3.18082701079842,-4.,-3.93896689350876));
#352=CARTESIAN_POINT('',(-3.14436378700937,-4.,-4.17909325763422));
#353=CARTESIAN_POINT('',(-3.13429162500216,-4.23755785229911,-4.22874464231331));
#354=CARTESIAN_POINT('',(-2.27425917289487,-4.,-3.80895642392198));
#355=CARTESIAN_POINT('',(-2.2462996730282,-4.,-4.04501060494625));
#356=CARTESIAN_POINT('',(-2.23761389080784,-4.23130704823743,-4.09873417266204));
#357=CARTESIAN_POINT('',(-1.82007498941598,-4.,-3.75526491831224));
#358=CARTESIAN_POINT('',(-1.7967057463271,-4.,-3.98921229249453));
#359=CARTESIAN_POINT('',(-1.78947764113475,-4.22824707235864,-4.04504266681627));
#360=CARTESIAN_POINT('',(-1.13689782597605,-4.,-3.69988893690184));
#361=CARTESIAN_POINT('',(-1.12134181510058,-4.,-3.93165738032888));
#362=CARTESIAN_POINT('',(-1.11696623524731,-4.22486404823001,-3.98966668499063));
#363=CARTESIAN_POINT('',(-0.908928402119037,-4.,-3.6856243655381));
#364=CARTESIAN_POINT('',(-0.896273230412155,-4.,-3.91679929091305));
#365=CARTESIAN_POINT('',(-0.892816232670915,-4.22393763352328,-3.97540211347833));
#366=CARTESIAN_POINT('',(-0.452607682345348,-4.,-3.6665138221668));
#367=CARTESIAN_POINT('',(-0.446298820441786,-4.,-3.89691907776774));
#368=CARTESIAN_POINT('',(-0.444436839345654,-4.22268126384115,-3.95629157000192));
#369=CARTESIAN_POINT('',(-0.224256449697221,-4.,-3.66166641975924));
#370=CARTESIAN_POINT('',(-0.221036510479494,-4.,-3.89186334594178));
#371=CARTESIAN_POINT('',(-0.220207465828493,-4.22235121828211,-3.95144416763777));
#372=CARTESIAN_POINT('',(0.0954427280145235,-4.,-3.66174069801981));
#373=CARTESIAN_POINT('',(0.0940729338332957,-4.,-3.89193929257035));
#374=CARTESIAN_POINT('',(0.093719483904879,-4.22235556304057,-3.95151844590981));
#375=CARTESIAN_POINT('',(0.186806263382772,-4.,-3.66254657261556));
#376=CARTESIAN_POINT('',(0.184139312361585,-4.,-3.89277890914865));
#377=CARTESIAN_POINT('',(0.183433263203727,-4.22241014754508,-3.95232432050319));
#378=CARTESIAN_POINT('',(0.369508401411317,-4.,-3.66570760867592));
#379=CARTESIAN_POINT('',(0.364233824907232,-4.,-3.89606944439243));
#380=CARTESIAN_POINT('',(0.36285690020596,-4.22262231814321,-3.95548535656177));
#381=CARTESIAN_POINT('',(0.460847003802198,-4.,-3.66806278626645));
#382=CARTESIAN_POINT('',(0.454286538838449,-4.,-3.89852128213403));
#383=CARTESIAN_POINT('',(0.452566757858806,-4.22277990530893,-3.95784053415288));
#384=CARTESIAN_POINT('',(0.734859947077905,-4.,-3.67741468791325));
#385=CARTESIAN_POINT('',(0.724520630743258,-4.,-3.90825571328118));
#386=CARTESIAN_POINT('',(0.721751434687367,-4.22340023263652,-3.96719243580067));
#387=CARTESIAN_POINT('',(0.917457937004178,-4.,-3.68669772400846));
#388=CARTESIAN_POINT('',(0.904698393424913,-4.,-3.91792275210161));
#389=CARTESIAN_POINT('',(0.901209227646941,-4.22401053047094,-3.97647547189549));
#390=CARTESIAN_POINT('',(1.46538584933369,-4.,-3.72308878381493));
#391=CARTESIAN_POINT('',(1.44585029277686,-4.,-3.9557693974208));
#392=CARTESIAN_POINT('',(1.44014875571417,-4.22631007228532,-4.01286653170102));
#393=CARTESIAN_POINT('',(1.83016120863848,-4.,-3.75873584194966));
#394=CARTESIAN_POINT('',(1.80655994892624,-4.,-3.99285693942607));
#395=CARTESIAN_POINT('',(1.79952160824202,-4.22846742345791,-4.04851358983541));
#396=CARTESIAN_POINT('',(2.37711083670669,-4.,-3.82532371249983));
#397=CARTESIAN_POINT('',(2.34675067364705,-4.,-4.06161010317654));
#398=CARTESIAN_POINT('',(2.33948155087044,-4.23202948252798,-4.11510146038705));
#399=CARTESIAN_POINT('',(2.56013311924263,-4.,-3.84983223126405));
#400=CARTESIAN_POINT('',(2.52791293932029,-4.,-4.08693071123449));
#401=CARTESIAN_POINT('',(2.52035319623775,-4.23327690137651,-4.13960997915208));
#402=CARTESIAN_POINT('',(2.92567074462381,-4.,-3.90250884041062));
#403=CARTESIAN_POINT('',(2.88996101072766,-4.,-4.1412494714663));
#404=CARTESIAN_POINT('',(2.8819368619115,-4.23579994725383,-4.19228658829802));
#405=CARTESIAN_POINT('',(3.10818604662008,-4.,-3.93067721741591));
#406=CARTESIAN_POINT('',(3.0708629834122,-4.,-4.17026322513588));
#407=CARTESIAN_POINT('',(3.06264886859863,-4.23707557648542,-4.22045496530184));
#408=CARTESIAN_POINT('',(3.47226816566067,-4.,-3.98995927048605));
#409=CARTESIAN_POINT('',(3.43194217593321,-4.,-4.23121932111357));
#410=CARTESIAN_POINT('',(3.42343750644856,-4.23959503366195,-4.27973701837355));
#411=CARTESIAN_POINT('',(3.65383621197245,-4.,-4.02106549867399));
#412=CARTESIAN_POINT('',(3.61210971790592,-4.,-4.26316311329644));
#413=CARTESIAN_POINT('',(3.60351460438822,-4.24083893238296,-4.31084324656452));
#414=CARTESIAN_POINT('',(4.01649495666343,-4.,-4.08575591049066));
#415=CARTESIAN_POINT('',(3.97220093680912,-4.,-4.3295045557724));
#416=CARTESIAN_POINT('',(3.96345182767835,-4.24326819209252,-4.37553365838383));
#417=CARTESIAN_POINT('',(4.19758574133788,-4.,-4.11933960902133));
#418=CARTESIAN_POINT('',(4.15209774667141,-4.,-4.36390527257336));
#419=CARTESIAN_POINT('',(4.14331198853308,-4.24445356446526,-4.4091173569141));
#420=CARTESIAN_POINT('',(4.37848254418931,-4.,-4.15390538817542));
#421=CARTESIAN_POINT('',(4.33158869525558,-4.,-4.39919906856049));
#422=CARTESIAN_POINT('',(4.32308448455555,-4.24559492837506,-4.44368313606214));
#423=(BOUNDED_SURFACE() B_SPLINE_SURFACE(3,2,((#291,#292,#293),(#294,#295,#296),(#297,#298,
#299),(#300,#301,#302),(#303,#304,#305),(#306,#307,#308),(#309,#310,#311),(#312,#313,#314),
(#315,#316,#317),(#318,#319,#320),(#321,#322,#323),(#324,#325,#326),(#327,#328,#329),(#330,#331,
#332),(#333,#334,#335),(#336,#337,#338),(#339,#340,#341),(#342,#343,#344),(#345,#346,#347),
(#348,#349,#350),(#351,#352,#353),(#354,#355,#356),(#357,#358,#359),(#360,#361,#362),(#363,#364,
#365),(#366,#367,#368),(#369,#370,#371),(#372,#373,#374),(#375,#376,#377),(#378,#379,#380),
(#381,#382,#383),(#384,#385,#386),(#387,#388,#389),(#390,#391,#392),(#393,#394,#395),(#396,#397,
#398),(#399,#400,#401),(#402,#403,#404),(#405,#406,#407),(#408,#409,#410),(#411,#412,#413),
(#414,#415,#416),(#417,#418,#419),(#420,#421,#422)),.UNSPECIFIED.,.F.,.F.,
.F.) B_SPLINE_SURFACE_WITH_KNOTS((4,2,2,2,2,2,2,2,2,2,2,2,2,2,2,2,2,2,2,2,2,4),(3,3),(0.,
2.86706588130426,5.73602383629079,8.67758762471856,11.6172066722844,13.0100695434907,
14.4029437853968,15.7986943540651,17.1944244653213,18.5701126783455,19.9461565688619,
21.3171941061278,22.0022754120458,22.6872526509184,22.9613438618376,23.2354379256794,
23.7838463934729,24.8827249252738,25.4366728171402,25.9906641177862,26.5432868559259,
27.0958016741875),(0.,1.),
.UNSPECIFIED.) GEOMETRIC_REPRESENTATION_ITEM() RATIONAL_B_SPLINE_SURFACE(((1.,0.724364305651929,
1.),(1.,0.725059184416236,1.),(1.,0.725819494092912,1.),(1.,0.727576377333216,1.),(1.,
0.728573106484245,1.),(1.,0.730937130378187,1.),(1.,0.732313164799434,1.),(1.,0.735636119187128,
1.),(1.,0.73758266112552,1.),(1.,0.741174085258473,1.),(1.,0.742438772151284,1.),(1.,
0.74526034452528,1.),(1.,0.746817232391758,1.),(1.,0.750315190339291,1.),(1.,0.752257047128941,
1.),(1.,0.75663005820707,1.),(1.,0.759061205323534,1.),(1.,0.764455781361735,1.),(1.,
0.767411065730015,1.),(1.,0.773796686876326,1.),(1.,0.777227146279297,1.),(1.,0.783899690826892,
1.),(1.,0.787142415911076,1.),(1.,0.790713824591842,1.),(1.,0.791688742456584,1.),(1.,
0.793010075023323,1.),(1.,0.793356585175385,1.),(1.,0.793351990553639,1.),(1.,0.79329466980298,
1.),(1.,0.793071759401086,1.),(1.,0.792906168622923,1.),(1.,0.792254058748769,1.),(1.,
0.791612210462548,1.),(1.,0.789188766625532,1.),(1.,0.786909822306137,1.),(1.,0.783125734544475,
1.),(1.,0.781797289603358,1.),(1.,0.779103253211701,1.),(1.,0.777737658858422,1.),(1.,
0.77503340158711,1.),(1.,0.773694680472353,1.),(1.,0.771073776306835,1.),(1.,0.769791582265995,
1.),(1.,0.768553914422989,1.))) REPRESENTATION_ITEM('') SURFACE());
#424=CARTESIAN_POINT('',(-22.1112237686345,-4.00000000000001,-8.54521545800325));
#425=CARTESIAN_POINT('',(-21.1869548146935,-4.00000000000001,-8.30218033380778));
#426=CARTESIAN_POINT('',(-20.2625786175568,-4.00000000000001,-8.05954685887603));
#427=CARTESIAN_POINT('',(-18.4128085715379,-4.00000000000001,-7.57567895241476));
#428=CARTESIAN_POINT('',(-17.4874144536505,-4.00000000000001,-7.33444554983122));
#429=CARTESIAN_POINT('',(-15.6125978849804,-4.00000000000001,-6.84822064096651));
#430=CARTESIAN_POINT('',(-14.6631600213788,-4.,-6.60328852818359));
#431=CARTESIAN_POINT('',(-12.7638679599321,-4.,-6.11764487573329));
#432=CARTESIAN_POINT('',(-11.8140144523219,-4.,-5.87693065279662));
#433=CARTESIAN_POINT('',(-10.4126820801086,-4.,-5.52783081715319));
#434=CARTESIAN_POINT('',(-9.9619478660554,-4.,-5.41646145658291));
#435=CARTESIAN_POINT('',(-9.05986760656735,-4.,-5.19620577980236));
#436=CARTESIAN_POINT('',(-8.60852155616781,-4.,-5.08731948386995));
#437=CARTESIAN_POINT('',(-7.70403865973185,-4.,-4.87292751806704));
#438=CARTESIAN_POINT('',(-7.25090004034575,-4.,-4.76742929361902));
#439=CARTESIAN_POINT('',(-6.3433786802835,-4.,-4.5619180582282));
#440=CARTESIAN_POINT('',(-5.8889959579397,-4.,-4.46190496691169));
#441=CARTESIAN_POINT('',(-4.9849139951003,-4.,-4.27193449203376));
#442=CARTESIAN_POINT('',(-4.53524119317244,-4.,-4.18185333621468));
#443=CARTESIAN_POINT('',(-3.63319803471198,-4.,-4.01536776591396));
#444=CARTESIAN_POINT('',(-3.18082701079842,-4.,-3.93896689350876));
#445=CARTESIAN_POINT('',(-2.27425917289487,-4.,-3.80895642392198));
#446=CARTESIAN_POINT('',(-1.82007498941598,-4.,-3.75526491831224));
#447=CARTESIAN_POINT('',(-1.13689782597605,-4.,-3.69988893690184));
#448=CARTESIAN_POINT('',(-0.908928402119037,-4.,-3.6856243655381));
#449=CARTESIAN_POINT('',(-0.452607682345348,-4.,-3.6665138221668));
#450=CARTESIAN_POINT('',(-0.22425644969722,-4.,-3.66166641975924));
#451=CARTESIAN_POINT('',(0.0954427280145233,-4.,-3.66174069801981));
#452=CARTESIAN_POINT('',(0.186806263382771,-4.,-3.66254657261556));
#453=CARTESIAN_POINT('',(0.369508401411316,-4.,-3.66570760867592));
#454=CARTESIAN_POINT('',(0.460847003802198,-4.,-3.66806278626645));
#455=CARTESIAN_POINT('',(0.734859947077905,-4.,-3.67741468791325));
#456=CARTESIAN_POINT('',(0.917457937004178,-4.,-3.68669772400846));
#457=CARTESIAN_POINT('',(1.46538584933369,-4.,-3.72308878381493));
#458=CARTESIAN_POINT('',(1.83016120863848,-4.,-3.75873584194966));
#459=CARTESIAN_POINT('',(2.37711083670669,-4.,-3.82532371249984));
#460=CARTESIAN_POINT('',(2.56013311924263,-4.,-3.84983223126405));
#461=CARTESIAN_POINT('',(2.92567074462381,-4.,-3.90250884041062));
#462=CARTESIAN_POINT('',(3.10818604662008,-4.,-3.93067721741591));
#463=CARTESIAN_POINT('',(3.47226816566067,-4.,-3.98995927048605));
#464=CARTESIAN_POINT('',(3.65383621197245,-4.,-4.02106549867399));
#465=CARTESIAN_POINT('',(4.01649495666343,-4.,-4.08575591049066));
#466=CARTESIAN_POINT('',(4.19758574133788,-4.,-4.11933960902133));
#467=CARTESIAN_POINT('',(4.37848254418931,-4.,-4.15390538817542));
#468=B_SPLINE_CURVE_WITH_KNOTS('',3,(#424,#425,#426,#427,#428,#429,#430,#431,#432,#433,#434,
#435,#436,#437,#438,#439,#440,#441,#442,#443,#444,#445,#446,#447,#448,#449,#450,#451,#452,#453,
#454,#455,#456,#457,#458,#459,#460,#461,#462,#463,#464,#465,#466,#467),.UNSPECIFIED.,.F.,.F.,(4,
2,2,2,2,2,2,2,2,2,2,2,2,2,2,2,2,2,2,2,2,4),(0.,2.86706588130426,5.73602383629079,
8.67758762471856,11.6172066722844,13.0100695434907,14.4029437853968,15.7986943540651,
17.1944244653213,18.5701126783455,19.9461565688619,21.3171941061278,22.0022754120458,
22.6872526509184,22.9613438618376,23.2354379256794,23.7838463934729,24.8827249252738,
25.4366728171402,25.9906641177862,26.5432868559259,27.0958016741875),.UNSPECIFIED.);
#469=EDGE_CURVE('E50',#286,#29,#468,.T.);
#470=ORIENTED_EDGE('',*,*,#469,.T.);
#471=ORIENTED_EDGE('',*,*,#32,.T.);
#472=CARTESIAN_POINT('',(-3.95402007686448,-4.,-4.67272970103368));
#473=CARTESIAN_POINT('',(-3.87640017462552,-4.,-4.51580666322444));
#474=CARTESIAN_POINT('',(-3.79788047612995,-4.,-4.35932155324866));
#475=CARTESIAN_POINT('',(-3.63863622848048,-4.,-4.04742537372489));
#476=CARTESIAN_POINT('',(-3.55791109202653,-4.,-3.89201460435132));
#477=CARTESIAN_POINT('',(-3.39300442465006,-4.,-3.58087522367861));
#478=CARTESIAN_POINT('',(-3.30879494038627,-4.,-3.42516137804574));
#479=CARTESIAN_POINT('',(-3.13722206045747,-4.,-3.11550528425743));
#480=CARTESIAN_POINT('',(-3.04985911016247,-4.,-2.9615627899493));
#481=CARTESIAN_POINT('',(-2.86487822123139,-4.,-2.64500008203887));
#482=CARTESIAN_POINT('',(-2.76697365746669,-4.,-2.4825463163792));
#483=CARTESIAN_POINT('',(-2.56554664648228,-4.,-2.16117918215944));
#484=CARTESIAN_POINT('',(-2.46202508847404,-4.,-2.00226525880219));
#485=CARTESIAN_POINT('',(-2.24812167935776,-4.,-1.69008184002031));
#486=CARTESIAN_POINT('',(-2.13777248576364,-4.,-1.53679033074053));
#487=CARTESIAN_POINT('',(-1.96498453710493,-4.,-1.31253972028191));
#488=CARTESIAN_POINT('',(-1.90620177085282,-4.,-1.23876446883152));
#489=CARTESIAN_POINT('',(-1.78577110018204,-4.,-1.09359841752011));
#490=CARTESIAN_POINT('',(-1.72412378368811,-4.,-1.02220713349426));
#491=CARTESIAN_POINT('',(-1.61052145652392,-4.,-0.896903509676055));
#492=CARTESIAN_POINT('',(-1.55919243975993,-4.,-0.842425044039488));
#493=CARTESIAN_POINT('',(-1.454075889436,-4.,-0.735842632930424));
#494=CARTESIAN_POINT('',(-1.40028749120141,-4.,-0.68373953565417));
#495=CARTESIAN_POINT('',(-1.29016745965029,-4.,-0.582774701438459));
#496=CARTESIAN_POINT('',(-1.23384819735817,-4.,-0.533899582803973));
#497=CARTESIAN_POINT('',(-1.1181091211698,-4.,-0.439997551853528));
#498=CARTESIAN_POINT('',(-1.05869041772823,-4.,-0.394969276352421));
#499=CARTESIAN_POINT('',(-0.912113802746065,-4.,-0.292936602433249));
#500=CARTESIAN_POINT('',(-0.823293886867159,-4.,-0.238256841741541));
#501=CARTESIAN_POINT('',(-0.638475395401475,-4.,-0.142743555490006));
#502=CARTESIAN_POINT('',(-0.542492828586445,-4.,-0.101880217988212));
#503=CARTESIAN_POINT('',(-0.365756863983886,-4.,-0.045869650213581));
#504=CARTESIAN_POINT('',(-0.28618107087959,-4.,-0.0270776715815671));
#505=CARTESIAN_POINT('',(-0.12496801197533,-4.,-0.00329341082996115));
#506=CARTESIAN_POINT('',(-0.0433321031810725,-4.,0.00170772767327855));
#507=CARTESIAN_POINT('',(0.119595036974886,-4.,-0.00275332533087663));
#508=CARTESIAN_POINT('',(0.200885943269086,-4.,-0.0122270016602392));
#509=CARTESIAN_POINT('',(0.36075120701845,-4.,-0.0444133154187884));
#510=CARTESIAN_POINT('',(0.439323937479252,-4.,-0.067133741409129));
#511=CARTESIAN_POINT('',(0.626552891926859,-4.,-0.13601192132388));
#512=CARTESIAN_POINT('',(0.732992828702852,-4.,-0.188103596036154));
#513=CARTESIAN_POINT('',(0.936786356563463,-4.,-0.307816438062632));
#514=CARTESIAN_POINT('',(1.03410669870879,-4.,-0.375491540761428));
#515=CARTESIAN_POINT('',(1.2460878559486,-4.,-0.54089570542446));
#516=CARTESIAN_POINT('',(1.35823651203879,-4.,-0.641787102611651));
#517=CARTESIAN_POINT('',(1.57251337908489,-4.,-0.853819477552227));
#518=CARTESIAN_POINT('',(1.67462071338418,-4.,-0.964980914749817));
#519=CARTESIAN_POINT('',(1.87229782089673,-4.,-1.19539292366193));
#520=CARTESIAN_POINT('',(1.96776699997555,-4.,-1.31472892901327));
#521=CARTESIAN_POINT('',(2.1062622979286,-4.,-1.4971529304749));
#522=CARTESIAN_POINT('',(2.15162165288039,-4.,-1.55850014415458));
#523=CARTESIAN_POINT('',(2.24096257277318,-4.,-1.68218822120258));
#524=CARTESIAN_POINT('',(2.28494418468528,-4.,-1.7445290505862));
#525=CARTESIAN_POINT('',(2.42881087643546,-4.,-1.9527039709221));
#526=CARTESIAN_POINT('',(2.52603970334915,-4.,-2.10037526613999));
#527=CARTESIAN_POINT('',(2.71542878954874,-4.,-2.39894567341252));
#528=CARTESIAN_POINT('',(2.80758794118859,-4.,-2.54984548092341));
#529=CARTESIAN_POINT('',(2.98790854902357,-4.,-2.8541464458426));
#530=CARTESIAN_POINT('',(3.07606723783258,-4.,-3.00754923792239));
#531=CARTESIAN_POINT('',(3.2490756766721,-4.,-3.31621372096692));
#532=CARTESIAN_POINT('',(3.33392522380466,-4.,-3.47147552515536));
#533=CARTESIAN_POINT('',(3.58500735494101,-4.,-3.94058437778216));
#534=CARTESIAN_POINT('',(3.74712222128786,-4.,-4.25663403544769));
#535=CARTESIAN_POINT('',(4.06349973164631,-4.,-4.89244192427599));
#536=CARTESIAN_POINT('',(4.2177654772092,-4.,-5.21219862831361));
#537=CARTESIAN_POINT('',(4.50248810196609,-4.,-5.81629142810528));
#538=CARTESIAN_POINT('',(4.63359595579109,-4.,-6.10032168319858));
#539=CARTESIAN_POINT('',(4.89223369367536,-4.,-6.67004326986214));
#540=CARTESIAN_POINT('',(5.01976315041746,-4.,-6.95573479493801));
#541=CARTESIAN_POINT('',(5.27098286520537,-4.,-7.52627080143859));
#542=CARTESIAN_POINT('',(5.39469457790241,-4.,-7.81110585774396));
#543=CARTESIAN_POINT('',(5.63971237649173,-4.,-8.38175114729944));
#544=CARTESIAN_POINT('',(5.76101887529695,-4.,-8.66756120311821));
#545=CARTESIAN_POINT('',(5.88137200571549,-4.,-8.95376720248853));
#546=B_SPLINE_CURVE_WITH_KNOTS('',3,(#472,#473,#474,#475,#476,#477,#478,#479,#480,#481,#482,
#483,#484,#485,#486,#487,#488,#489,#490,#491,#492,#493,#494,#495,#496,#497,#498,#499,#500,#501,
#502,#503,#504,#505,#506,#507,#508,#509,#510,#511,#512,#513,#514,#515,#516,#517,#518,#519,#520,
#521,#522,#523,#524,#525,#526,#527,#528,#529,#530,#531,#532,#533,#534,#535,#536,#537,#538,#539,
#540,#541,#542,#543,#544,#545),.UNSPECIFIED.,.F.,.F.,(4,2,2,2,2,2,2,2,2,2,2,2,2,2,2,2,2,2,2,2,2,
2,2,2,2,2,2,2,2,2,2,2,2,2,2,2,4),(0.,0.525218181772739,1.05057761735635,1.58162323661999,
2.11259414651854,2.68152598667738,3.25036802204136,3.81667291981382,4.09960866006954,
4.38248658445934,4.60697399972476,4.8315409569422,5.05510944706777,5.27859838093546,
5.59064578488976,5.90201551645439,6.14626082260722,6.39034923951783,6.63463142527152,
6.87905738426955,7.2325226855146,7.58723024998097,8.03870278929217,8.49109496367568,
8.94928685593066,9.17815941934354,9.40702417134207,9.93728661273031,10.467664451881,
10.9984037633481,11.5291755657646,12.5946055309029,13.6596111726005,14.5980694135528,
15.5366392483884,16.4682501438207,17.3996996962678),.UNSPECIFIED.);
#547=CARTESIAN_POINT('',(0.,-4.,0.));
#548=VERTEX_POINT('',#547);
#549=EDGE_CURVE('E169',#548,#31,#546,.T.);
#550=ORIENTED_EDGE('',*,*,#549,.F.);
#551=EDGE_CURVE('E151',#288,#548,#546,.T.);
#552=ORIENTED_EDGE('',*,*,#551,.F.);
#553=EDGE_LOOP('',(#290,#470,#471,#550,#552));
#554=FACE_BOUND('',#553,.T.);
#555=ADVANCED_FACE('F383',(#554),#280,.T.);
#556=CARTESIAN_POINT('',(-4.61880215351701,0.,-5.3));
#557=DIRECTION('',(-0.866025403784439,-0.5,0.));
#558=DIRECTION('',(0.5,-0.866025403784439,0.));
#559=AXIS2_PLACEMENT_3D('',#556,#557,#558);
#560=PLANE('',#559);
#561=DIRECTION('',(0.,0.,1.));
#562=VECTOR('',#561,1.);
#563=CARTESIAN_POINT('',(-4.61880215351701,0.,-5.3));
#564=LINE('',#563,#562);
#565=CARTESIAN_POINT('',(-4.61880215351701,0.,-3.81737471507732));
#566=VERTEX_POINT('',#565);
#567=CARTESIAN_POINT('',(-4.61880215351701,0.,-1.78));
#568=VERTEX_POINT('',#567);
#569=EDGE_CURVE('E130',#566,#568,#564,.T.);
#570=ORIENTED_EDGE('',*,*,#569,.F.);
#571=CARTESIAN_POINT('',(-14.5394344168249,17.1830391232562,-8.55558985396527));
#572=CARTESIAN_POINT('',(-14.5031144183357,17.1201310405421,-8.83174684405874));
#573=CARTESIAN_POINT('',(-14.7483162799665,16.9744266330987,-8.84536760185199));
#574=CARTESIAN_POINT('',(-14.0765515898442,16.3813025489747,-8.31214514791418));
#575=CARTESIAN_POINT('',(-14.0406605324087,16.3191374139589,-8.58793733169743));
#576=CARTESIAN_POINT('',(-14.2849712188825,16.1730960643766,-8.60192289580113));
#577=CARTESIAN_POINT('',(-13.6136152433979,15.5794732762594,-8.06910132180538));
#578=CARTESIAN_POINT('',(-13.5780832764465,15.5179301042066,-8.34442822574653));
#579=CARTESIAN_POINT('',(-13.8215293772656,15.3717118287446,-8.35887906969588));
#580=CARTESIAN_POINT('',(-12.6872328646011,13.9749319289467,-7.58440903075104));
#581=CARTESIAN_POINT('',(-12.6521068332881,13.9140918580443,-7.8584468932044));
#582=CARTESIAN_POINT('',(-12.8939913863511,13.7682273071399,-7.874186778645));
#583=CARTESIAN_POINT('',(-12.2237866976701,13.1722196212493,-7.34276159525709));
#584=CARTESIAN_POINT('',(-12.1890072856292,13.111979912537,-7.61612935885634));
#585=CARTESIAN_POINT('',(-12.4298950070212,12.966126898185,-7.63253934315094));
#586=CARTESIAN_POINT('',(-11.2848698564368,11.545967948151,-6.85569776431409));
#587=CARTESIAN_POINT('',(-11.2505929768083,11.4865986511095,-7.12731783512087));
#588=CARTESIAN_POINT('',(-11.4894564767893,11.3413728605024,-7.14547551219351));
#589=CARTESIAN_POINT('',(-10.8093914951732,10.7224152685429,-6.61034060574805));
#590=CARTESIAN_POINT('',(-10.7756871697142,10.6640376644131,-6.88108543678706));
#591=CARTESIAN_POINT('',(-11.0131014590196,10.5187124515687,-6.9001183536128));
#592=CARTESIAN_POINT('',(-9.85822885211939,9.07495324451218,-6.12383947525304));
#593=CARTESIAN_POINT('',(-9.82529712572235,9.01791382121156,-6.39216776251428));
#594=CARTESIAN_POINT('',(-10.0598640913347,8.87350005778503,-6.41361722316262));
#595=CARTESIAN_POINT('',(-9.38254491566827,8.25104449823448,-5.88269281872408));
#596=CARTESIAN_POINT('',(-9.35055396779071,8.19563455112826,-6.14984390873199));
#597=CARTESIAN_POINT('',(-9.582982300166,8.05094836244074,-6.17247056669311));
#598=CARTESIAN_POINT('',(-8.68076096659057,7.03551904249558,-5.53294307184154));
#599=CARTESIAN_POINT('',(-8.64841830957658,6.97949991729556,-5.79690487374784));
#600=CARTESIAN_POINT('',(-8.87907047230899,6.8381063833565,-5.82272081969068));
#601=CARTESIAN_POINT('',(-8.45503264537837,6.64454612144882,-5.42136208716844));
#602=CARTESIAN_POINT('',(-8.42309728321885,6.58923245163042,-5.6844641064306));
#603=CARTESIAN_POINT('',(-8.65260283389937,6.44810029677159,-5.71113983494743));
#604=CARTESIAN_POINT('',(-8.0032705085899,5.86207114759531,-5.20067849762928));
#605=CARTESIAN_POINT('',(-7.97209417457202,5.8080721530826,-5.46179745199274));
#606=CARTESIAN_POINT('',(-8.19922969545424,5.66786499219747,-5.49045624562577));
#607=CARTESIAN_POINT('',(-7.77723669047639,5.47056909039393,-5.09157591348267));
#608=CARTESIAN_POINT('',(-7.7465898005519,5.41748711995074,-5.35165029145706));
#609=CARTESIAN_POINT('',(-7.97232419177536,5.27763577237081,-5.38135366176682));
#610=CARTESIAN_POINT('',(-7.32427254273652,4.68601217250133,-4.87674409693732));
#611=CARTESIAN_POINT('',(-7.29464827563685,4.63470143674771,-5.1344034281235));
#612=CARTESIAN_POINT('',(-7.51746746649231,4.49607741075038,-5.16652184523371));
#613=CARTESIAN_POINT('',(-7.09734132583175,4.29295577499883,-4.77102231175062));
#614=CARTESIAN_POINT('',(-7.0684397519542,4.24289678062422,-5.02740455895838));
#615=CARTESIAN_POINT('',(-7.28951505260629,4.10474766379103,-5.06080005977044));
#616=CARTESIAN_POINT('',(-6.64285764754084,3.5057669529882,-4.56505534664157));
#617=CARTESIAN_POINT('',(-6.61538261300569,3.4581787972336,-4.81848453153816));
#618=CARTESIAN_POINT('',(-6.83285336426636,3.32169726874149,-4.85483309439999));
#619=CARTESIAN_POINT('',(-6.41530519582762,3.11163454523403,-4.46481008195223));
#620=CARTESIAN_POINT('',(-6.38883006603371,3.06577827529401,-4.71666888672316));
#621=CARTESIAN_POINT('',(-6.60414410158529,2.92997662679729,-4.75458782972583));
#622=CARTESIAN_POINT('',(-5.96254818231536,2.32743639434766,-4.27436791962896));
#623=CARTESIAN_POINT('',(-5.9380857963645,2.2850662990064,-4.52267428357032));
#624=CARTESIAN_POINT('',(-6.14906336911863,2.15161259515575,-4.5641456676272));
#625=CARTESIAN_POINT('',(-5.73735683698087,1.93739354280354,-4.184047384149));
#626=CARTESIAN_POINT('',(-5.71426252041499,1.89739301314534,-4.43047216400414));
#627=CARTESIAN_POINT('',(-5.92270549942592,1.76497708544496,-4.4738251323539));
#628=CARTESIAN_POINT('',(-5.28562396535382,1.15496925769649,-4.01707291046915));
#629=CARTESIAN_POINT('',(-5.26548525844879,1.12008799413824,-4.25943247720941));
#630=CARTESIAN_POINT('',(-5.46895307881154,0.990871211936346,-4.30685065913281));
#631=CARTESIAN_POINT('',(-5.05908210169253,0.762587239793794,-3.94042254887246));
#632=CARTESIAN_POINT('',(-5.04081547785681,0.730948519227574,-4.18059335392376));
#633=CARTESIAN_POINT('',(-5.24155827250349,0.603400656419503,-4.23020029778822));
#634=CARTESIAN_POINT('',(-4.60508396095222,-0.0237606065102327,-3.80992031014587));
#635=CARTESIAN_POINT('',(-4.59106603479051,-0.048040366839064,-4.04600903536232));
#636=CARTESIAN_POINT('',(-4.78707554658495,-0.171259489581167,-4.09969805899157));
#637=CARTESIAN_POINT('',(-4.37763402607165,-0.417715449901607,-3.75598635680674));
#638=CARTESIAN_POINT('',(-4.36591203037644,-0.438018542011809,-3.98996132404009));
#639=CARTESIAN_POINT('',(-4.5599895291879,-0.558444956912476,-4.04576410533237));
#640=CARTESIAN_POINT('',(-4.03550287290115,-1.01030399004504,-3.70029165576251));
#641=CARTESIAN_POINT('',(-4.02768682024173,-1.02384179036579,-3.93207627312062));
#642=CARTESIAN_POINT('',(-4.22024886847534,-1.14009389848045,-3.99006940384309));
#643=CARTESIAN_POINT('',(-3.92133660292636,-1.20804577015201,-3.68592836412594));
#644=CARTESIAN_POINT('',(-3.91497211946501,-1.21906937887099,-3.91711556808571));
#645=CARTESIAN_POINT('',(-4.10718621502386,-1.33405956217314,-3.97570611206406));
#646=CARTESIAN_POINT('',(-3.69281117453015,-1.60386342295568,-3.66664521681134));
#647=CARTESIAN_POINT('',(-3.68962349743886,-1.60938464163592,-3.89705602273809));
#648=CARTESIAN_POINT('',(-3.88153811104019,-1.72235904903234,-3.95642296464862));
#649=CARTESIAN_POINT('',(-3.57845204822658,-1.80193924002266,-3.66172391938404));
#650=CARTESIAN_POINT('',(-3.57681077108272,-1.80478201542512,-3.89192321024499));
#651=CARTESIAN_POINT('',(-3.76895259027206,-1.91669281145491,-3.95150166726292));
#652=CARTESIAN_POINT('',(-3.41841730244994,-2.07912755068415,-3.66171696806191));
#653=CARTESIAN_POINT('',(-3.41907307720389,-2.077991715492,-3.89191458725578));
#654=CARTESIAN_POINT('',(-3.61180632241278,-2.18887586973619,-3.95149471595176));
#655=CARTESIAN_POINT('',(-3.37273437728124,-2.15825269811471,-3.6624996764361));
#656=CARTESIAN_POINT('',(-3.37403878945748,-2.15599338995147,-3.89273007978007));
#657=CARTESIAN_POINT('',(-3.56699429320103,-2.26659862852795,-3.95227742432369));
#658=CARTESIAN_POINT('',(-3.28138077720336,-2.31648177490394,-3.66561475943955));
#659=CARTESIAN_POINT('',(-3.2839892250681,-2.3119638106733,-3.8959727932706));
#660=CARTESIAN_POINT('',(-3.47746138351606,-2.42209240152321,-3.95539250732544));
#661=CARTESIAN_POINT('',(-3.23571010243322,-2.39558570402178,-3.66794715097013));
#662=CARTESIAN_POINT('',(-3.23896165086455,-2.38995385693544,-3.8984009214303));
#663=CARTESIAN_POINT('',(-3.43274050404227,-2.49986341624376,-3.95772489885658));
#664=CARTESIAN_POINT('',(-3.09869925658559,-2.63289545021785,-3.67723166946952));
#665=CARTESIAN_POINT('',(-3.10384109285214,-2.62398952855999,-3.90806527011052));
#666=CARTESIAN_POINT('',(-3.29867820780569,-2.73329813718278,-3.96700941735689));
#667=CARTESIAN_POINT('',(-3.00739699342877,-2.79103560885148,-3.68647110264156));
#668=CARTESIAN_POINT('',(-3.01374944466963,-2.78003284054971,-3.91768701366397));
#669=CARTESIAN_POINT('',(-3.20947317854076,-2.88902107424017,-3.97624885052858));
#670=CARTESIAN_POINT('',(-2.73342367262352,-3.26557132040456,-3.72273800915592));
#671=CARTESIAN_POINT('',(-2.74316707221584,-3.24869525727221,-3.95540495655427));
#672=CARTESIAN_POINT('',(-2.94198280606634,-3.35691346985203,-4.01251575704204));
#673=CARTESIAN_POINT('',(-2.55102910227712,-3.58148798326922,-3.75831137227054));
#674=CARTESIAN_POINT('',(-2.56280649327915,-3.56108894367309,-3.99241678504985));
#675=CARTESIAN_POINT('',(-2.76415802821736,-3.66922375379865,-4.04808912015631));
#676=CARTESIAN_POINT('',(-2.27754571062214,-4.05517511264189,-3.82480471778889));
#677=CARTESIAN_POINT('',(-2.29270504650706,-4.0289183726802,-4.06107376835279));
#678=CARTESIAN_POINT('',(-2.49725630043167,-4.13863043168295,-4.1145824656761));
#679=CARTESIAN_POINT('',(-2.18603289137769,-4.21367996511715,-3.8492840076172));
#680=CARTESIAN_POINT('',(-2.20212308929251,-4.18581092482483,-4.0863647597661));
#681=CARTESIAN_POINT('',(-2.40790002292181,-4.29589395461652,-4.13906175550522));
#682=CARTESIAN_POINT('',(-2.00326079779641,-4.53025051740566,-3.90190705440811));
#683=CARTESIAN_POINT('',(-2.02109756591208,-4.4993563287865,-4.14062943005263));
#684=CARTESIAN_POINT('',(-2.22929208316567,-4.61029719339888,-4.19168480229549));
#685=CARTESIAN_POINT('',(-1.91200154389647,-4.68831618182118,-3.93005109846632));
#686=CARTESIAN_POINT('',(-1.93064579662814,-4.65602338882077,-4.16961875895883));
#687=CARTESIAN_POINT('',(-2.1400404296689,-4.76743689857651,-4.21982884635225));
#688=CARTESIAN_POINT('',(-1.7299563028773,-5.00362778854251,-3.9892892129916));
#689=CARTESIAN_POINT('',(-1.75010367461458,-4.96873151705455,-4.23053091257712));
#690=CARTESIAN_POINT('',(-1.96182642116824,-5.08115229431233,-4.2790669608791));
#691=CARTESIAN_POINT('',(-1.63916970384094,-5.16087479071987,-4.0203758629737));
#692=CARTESIAN_POINT('',(-1.66001808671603,-5.12476433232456,-4.26245525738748));
#693=CARTESIAN_POINT('',(-1.87286389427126,-5.23772842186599,-4.31015361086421));
#694=CARTESIAN_POINT('',(-1.45783539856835,-5.4749550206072,-4.0850307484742));
#695=CARTESIAN_POINT('',(-1.47996899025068,-5.43661851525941,-4.32876154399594));
#696=CARTESIAN_POINT('',(-1.69499683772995,-5.55066351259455,-4.37480849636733));
#697=CARTESIAN_POINT('',(-1.36728764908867,-5.63178832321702,-4.11859849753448));
#698=CARTESIAN_POINT('',(-1.3900188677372,-5.59241669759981,-4.36314658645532));
#699=CARTESIAN_POINT('',(-1.6060923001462,-5.70702251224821,-4.40837624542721));
#700=CARTESIAN_POINT('',(-1.27683699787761,-5.78845344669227,-4.15314978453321));
#701=CARTESIAN_POINT('',(-1.30027186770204,-5.7478630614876,-4.3984261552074));
#702=CARTESIAN_POINT('',(-1.51719352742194,-5.86328355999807,-4.44292753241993));
#703=(BOUNDED_SURFACE() B_SPLINE_SURFACE(3,2,((#571,#572,#573),(#574,#575,#576),(#577,#578,
#579),(#580,#581,#582),(#583,#584,#585),(#586,#587,#588),(#589,#590,#591),(#592,#593,#594),
(#595,#596,#597),(#598,#599,#600),(#601,#602,#603),(#604,#605,#606),(#607,#608,#609),(#610,#611,
#612),(#613,#614,#615),(#616,#617,#618),(#619,#620,#621),(#622,#623,#624),(#625,#626,#627),
(#628,#629,#630),(#631,#632,#633),(#634,#635,#636),(#637,#638,#639),(#640,#641,#642),(#643,#644,
#645),(#646,#647,#648),(#649,#650,#651),(#652,#653,#654),(#655,#656,#657),(#658,#659,#660),
(#661,#662,#663),(#664,#665,#666),(#667,#668,#669),(#670,#671,#672),(#673,#674,#675),(#676,#677,
#678),(#679,#680,#681),(#682,#683,#684),(#685,#686,#687),(#688,#689,#690),(#691,#692,#693),
(#694,#695,#696),(#697,#698,#699),(#700,#701,#702)),.UNSPECIFIED.,.F.,.F.,
.F.) B_SPLINE_SURFACE_WITH_KNOTS((4,2,2,2,2,2,2,2,2,2,2,2,2,2,2,2,2,2,2,2,2,4),(3,3),(0.,
2.87172082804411,5.74534141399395,8.69163587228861,11.6359776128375,13.0310968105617,
14.4262276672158,15.8242453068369,17.222241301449,18.600159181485,19.978437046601,
21.3516914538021,22.0378780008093,22.7239597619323,22.9980573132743,23.272157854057,
23.8205791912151,24.9194760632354,25.4734222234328,26.0274118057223,26.5800398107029,
27.1325597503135),(0.,1.),
.UNSPECIFIED.) GEOMETRIC_REPRESENTATION_ITEM() RATIONAL_B_SPLINE_SURFACE(((1.,0.724335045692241,
1.),(1.,0.725028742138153,1.),(1.,0.725787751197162,1.),(1.,0.727541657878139,1.),(1.,
0.728536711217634,1.),(1.,0.730896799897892,1.),(1.,0.732270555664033,1.),(1.,0.735588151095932,
1.),(1.,0.737531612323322,1.),(1.,0.741117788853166,1.),(1.,0.742380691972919,1.),(1.,
0.745198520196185,1.),(1.,0.746753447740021,1.),(1.,0.750247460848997,1.),(1.,0.752187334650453,
1.),(1.,0.756556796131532,1.),(1.,0.758986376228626,1.),(1.,0.764379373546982,1.),(1.,
0.767334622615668,1.),(1.,0.773723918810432,1.),(1.,0.777158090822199,1.),(1.,0.783844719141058,
1.),(1.,0.787097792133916,1.),(1.,0.790686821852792,1.),(1.,0.791667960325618,1.),(1.,
0.79300075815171,1.),(1.,0.793352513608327,1.),(1.,0.793353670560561,1.),(1.,0.793297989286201,
1.),(1.,0.793078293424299,1.),(1.,0.792914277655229,1.),(1.,0.792266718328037,1.),(1.,
0.791627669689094,1.),(1.,0.789211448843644,1.),(1.,0.786935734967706,1.),(1.,0.783154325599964,
1.),(1.,0.78182642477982,1.),(1.,0.779132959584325,1.),(1.,0.777767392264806,1.),(1.,
0.77506282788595,1.),(1.,0.773723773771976,1.),(1.,0.771102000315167,1.),(1.,0.769819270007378,
1.),(1.,0.768581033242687,1.))) REPRESENTATION_ITEM('') SURFACE());
#704=CARTESIAN_POINT('',(-14.5394344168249,17.1830391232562,-8.55558985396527));
#705=CARTESIAN_POINT('',(-14.0765515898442,16.3813025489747,-8.31214514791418));
#706=CARTESIAN_POINT('',(-13.6136152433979,15.5794732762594,-8.06910132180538));
#707=CARTESIAN_POINT('',(-12.6872328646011,13.9749319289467,-7.58440903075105));
#708=CARTESIAN_POINT('',(-12.2237866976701,13.1722196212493,-7.34276159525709));
#709=CARTESIAN_POINT('',(-11.2848698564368,11.545967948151,-6.85569776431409));
#710=CARTESIAN_POINT('',(-10.8093914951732,10.7224152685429,-6.61034060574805));
#711=CARTESIAN_POINT('',(-9.85822885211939,9.07495324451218,-6.12383947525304));
#712=CARTESIAN_POINT('',(-9.38254491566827,8.25104449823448,-5.88269281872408));
#713=CARTESIAN_POINT('',(-8.68076096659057,7.03551904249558,-5.53294307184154));
#714=CARTESIAN_POINT('',(-8.45503264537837,6.64454612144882,-5.42136208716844));
#715=CARTESIAN_POINT('',(-8.0032705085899,5.86207114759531,-5.20067849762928));
#716=CARTESIAN_POINT('',(-7.77723669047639,5.47056909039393,-5.09157591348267));
#717=CARTESIAN_POINT('',(-7.32427254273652,4.68601217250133,-4.87674409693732));
#718=CARTESIAN_POINT('',(-7.09734132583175,4.29295577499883,-4.77102231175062));
#719=CARTESIAN_POINT('',(-6.64285764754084,3.5057669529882,-4.56505534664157));
#720=CARTESIAN_POINT('',(-6.41530519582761,3.11163454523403,-4.46481008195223));
#721=CARTESIAN_POINT('',(-5.96254818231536,2.32743639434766,-4.27436791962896));
#722=CARTESIAN_POINT('',(-5.73735683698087,1.93739354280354,-4.184047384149));
#723=CARTESIAN_POINT('',(-5.28562396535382,1.15496925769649,-4.01707291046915));
#724=CARTESIAN_POINT('',(-5.05908210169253,0.762587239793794,-3.94042254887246));
#725=CARTESIAN_POINT('',(-4.60508396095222,-0.0237606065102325,-3.80992031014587));
#726=CARTESIAN_POINT('',(-4.37763402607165,-0.417715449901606,-3.75598635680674));
#727=CARTESIAN_POINT('',(-4.03550287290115,-1.01030399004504,-3.70029165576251));
#728=CARTESIAN_POINT('',(-3.92133660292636,-1.20804577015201,-3.68592836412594));
#729=CARTESIAN_POINT('',(-3.69281117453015,-1.60386342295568,-3.66664521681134));
#730=CARTESIAN_POINT('',(-3.57845204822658,-1.80193924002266,-3.66172391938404));
#731=CARTESIAN_POINT('',(-3.41841730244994,-2.07912755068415,-3.66171696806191));
#732=CARTESIAN_POINT('',(-3.37273437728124,-2.15825269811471,-3.6624996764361));
#733=CARTESIAN_POINT('',(-3.28138077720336,-2.31648177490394,-3.66561475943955));
#734=CARTESIAN_POINT('',(-3.23571010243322,-2.39558570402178,-3.66794715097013));
#735=CARTESIAN_POINT('',(-3.09869925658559,-2.63289545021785,-3.67723166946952));
#736=CARTESIAN_POINT('',(-3.00739699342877,-2.79103560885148,-3.68647110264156));
#737=CARTESIAN_POINT('',(-2.73342367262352,-3.26557132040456,-3.72273800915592));
#738=CARTESIAN_POINT('',(-2.55102910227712,-3.58148798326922,-3.75831137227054));
#739=CARTESIAN_POINT('',(-2.27754571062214,-4.05517511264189,-3.82480471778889));
#740=CARTESIAN_POINT('',(-2.18603289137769,-4.21367996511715,-3.8492840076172));
#741=CARTESIAN_POINT('',(-2.00326079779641,-4.53025051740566,-3.90190705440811));
#742=CARTESIAN_POINT('',(-1.91200154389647,-4.68831618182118,-3.93005109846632));
#743=CARTESIAN_POINT('',(-1.7299563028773,-5.00362778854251,-3.9892892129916));
#744=CARTESIAN_POINT('',(-1.63916970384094,-5.16087479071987,-4.0203758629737));
#745=CARTESIAN_POINT('',(-1.45783539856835,-5.4749550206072,-4.0850307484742));
#746=CARTESIAN_POINT('',(-1.36728764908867,-5.63178832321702,-4.11859849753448));
#747=CARTESIAN_POINT('',(-1.27683699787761,-5.78845344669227,-4.15314978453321));
#748=B_SPLINE_CURVE_WITH_KNOTS('',3,(#704,#705,#706,#707,#708,#709,#710,#711,#712,#713,#714,
#715,#716,#717,#718,#719,#720,#721,#722,#723,#724,#725,#726,#727,#728,#729,#730,#731,#732,#733,
#734,#735,#736,#737,#738,#739,#740,#741,#742,#743,#744,#745,#746,#747),.UNSPECIFIED.,.F.,.F.,(4,
2,2,2,2,2,2,2,2,2,2,2,2,2,2,2,2,2,2,2,2,4),(0.,2.87172082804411,5.74534141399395,
8.69163587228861,11.6359776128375,13.0310968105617,14.4262276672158,15.8242453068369,
17.222241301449,18.600159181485,19.978437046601,21.3516914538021,22.0378780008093,
22.7239597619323,22.9980573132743,23.272157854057,23.8205791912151,24.9194760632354,
25.4734222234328,26.0274118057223,26.5800398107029,27.1325597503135),.UNSPECIFIED.);
#749=EDGE_CURVE('E11',#566,#286,#748,.T.);
#750=ORIENTED_EDGE('',*,*,#749,.T.);
#751=ORIENTED_EDGE('',*,*,#289,.T.);
#752=CARTESIAN_POINT('',(-4.61887168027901,0.000120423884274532,-1.7802));
#753=CARTESIAN_POINT('',(-4.59853045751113,-0.0351116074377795,-1.72169220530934));
#754=CARTESIAN_POINT('',(-4.57792135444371,-0.0708076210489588,-1.66355827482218));
#755=CARTESIAN_POINT('',(-4.53609096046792,-0.143259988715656,-1.54815677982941));
#756=CARTESIAN_POINT('',(-4.51486951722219,-0.180016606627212,-1.49088943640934));
#757=CARTESIAN_POINT('',(-4.44989761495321,-0.292551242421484,-1.31984609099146));
#758=CARTESIAN_POINT('',(-4.40511113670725,-0.370123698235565,-1.20761921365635));
#759=CARTESIAN_POINT('',(-4.31001453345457,-0.53483584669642,-0.984245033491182));
#760=CARTESIAN_POINT('',(-4.25954819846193,-0.622246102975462,-0.87336164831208));
#761=CARTESIAN_POINT('',(-4.1537807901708,-0.805440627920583,-0.661563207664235));
#762=CARTESIAN_POINT('',(-4.09849522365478,-0.901198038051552,-0.560618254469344));
#763=CARTESIAN_POINT('',(-4.01755039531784,-1.04139859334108,-0.431782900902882));
#764=CARTESIAN_POINT('',(-3.99458074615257,-1.08118319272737,-0.39714306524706));
#765=CARTESIAN_POINT('',(-3.94761959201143,-1.16252229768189,-0.330748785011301));
#766=CARTESIAN_POINT('',(-3.92362782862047,-1.2040772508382,-0.298995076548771));
#767=CARTESIAN_POINT('',(-3.85037983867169,-1.33094649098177,-0.209445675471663));
#768=CARTESIAN_POINT('',(-3.79947216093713,-1.41912117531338,-0.156734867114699));
#769=CARTESIAN_POINT('',(-3.70753434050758,-1.57836215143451,-0.0827968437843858));
#770=CARTESIAN_POINT('',(-3.66744840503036,-1.64779302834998,-0.0569308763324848));
#771=CARTESIAN_POINT('',(-3.58565651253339,-1.78946074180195,-0.0188566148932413));
#772=CARTESIAN_POINT('',(-3.54395176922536,-1.86169547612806,-0.00663828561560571));
#773=CARTESIAN_POINT('',(-3.45994159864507,-2.00720535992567,0.0025187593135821));
#774=CARTESIAN_POINT('',(-3.41763443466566,-2.08048351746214,-0.000603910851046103));
#775=CARTESIAN_POINT('',(-3.33396818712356,-2.22539770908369,-0.0218132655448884));
#776=CARTESIAN_POINT('',(-3.2926100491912,-2.29703210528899,-0.0399142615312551));
#777=CARTESIAN_POINT('',(-3.20045135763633,-2.45665564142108,-0.0957585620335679));
#778=CARTESIAN_POINT('',(-3.15028584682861,-2.54354485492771,-0.137607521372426));
#779=CARTESIAN_POINT('',(-3.05381880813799,-2.71063066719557,-0.236407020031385));
#780=CARTESIAN_POINT('',(-3.0075286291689,-2.79080760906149,-0.293400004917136));
#781=CARTESIAN_POINT('',(-2.92091463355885,-2.94082745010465,-0.414494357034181));
#782=CARTESIAN_POINT('',(-2.88040651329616,-3.01098957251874,-0.478080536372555));
#783=CARTESIAN_POINT('',(-2.80218899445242,-3.14646628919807,-0.611867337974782));
#784=CARTESIAN_POINT('',(-2.76448256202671,-3.21177574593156,-0.682074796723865));
#785=CARTESIAN_POINT('',(-2.6913296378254,-3.33848032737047,-0.827445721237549));
#786=CARTESIAN_POINT('',(-2.65589061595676,-3.39986251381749,-0.902624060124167));
#787=CARTESIAN_POINT('',(-2.58701514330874,-3.51915833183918,-1.05648002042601));
#788=CARTESIAN_POINT('',(-2.55357783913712,-3.57707344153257,-1.13515612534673));
#789=CARTESIAN_POINT('',(-2.48363251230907,-3.69822230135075,-1.30677603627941));
#790=CARTESIAN_POINT('',(-2.44738132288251,-3.76101120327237,-1.40013569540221));
#791=CARTESIAN_POINT('',(-2.37697159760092,-3.88296442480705,-1.58876843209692));
#792=CARTESIAN_POINT('',(-2.3427982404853,-3.94215441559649,-1.68401931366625));
#793=CARTESIAN_POINT('',(-2.30933154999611,-4.00012042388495,-1.78020000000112));
#794=B_SPLINE_CURVE_WITH_KNOTS('',3,(#752,#753,#754,#755,#756,#757,#758,#759,#760,#761,#762,
#763,#764,#765,#766,#767,#768,#769,#770,#771,#772,#773,#774,#775,#776,#777,#778,#779,#780,#781,
#782,#783,#784,#785,#786,#787,#788,#789,#790,#791,#792,#793),.UNSPECIFIED.,.F.,.F.,(4,2,2,2,2,2,
2,2,2,2,2,2,2,2,2,2,2,2,2,2,4),(0.,0.213777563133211,0.427608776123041,0.858145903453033,
1.30759304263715,1.75564391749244,1.92815043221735,2.10070082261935,2.44287249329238,
2.69463411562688,2.94621049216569,3.19879434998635,3.45161982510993,3.77590275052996,
4.10110434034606,4.4096095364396,4.71843682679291,5.02823407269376,5.33789828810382,
5.69242023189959,6.04401162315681),.UNSPECIFIED.);
#795=CARTESIAN_POINT('',(-3.46410161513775,-2.,0.));
#796=VERTEX_POINT('',#795);
#797=EDGE_CURVE('E150',#796,#288,#794,.T.);
#798=ORIENTED_EDGE('',*,*,#797,.F.);
#799=EDGE_CURVE('E145',#568,#796,#794,.T.);
#800=ORIENTED_EDGE('',*,*,#799,.F.);
#801=EDGE_LOOP('',(#570,#750,#751,#798,#800));
#802=FACE_BOUND('',#801,.T.);
#803=ADVANCED_FACE('F155',(#802),#560,.T.);
#804=CARTESIAN_POINT('',(-2.3094010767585,4.,-5.3));
#805=DIRECTION('',(-0.866025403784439,0.5,0.));
#806=DIRECTION('',(-0.5,-0.866025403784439,0.));
#807=AXIS2_PLACEMENT_3D('',#804,#805,#806);
#808=PLANE('',#807);
#809=DIRECTION('',(0.,0.,1.));
#810=VECTOR('',#809,1.);
#811=CARTESIAN_POINT('',(-2.3094010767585,4.,-5.3));
#812=LINE('',#811,#810);
#813=CARTESIAN_POINT('',(-2.3094010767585,4.,-3.81737471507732));
#814=VERTEX_POINT('',#813);
#815=CARTESIAN_POINT('',(-2.30940107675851,4.,-1.78));
#816=VERTEX_POINT('',#815);
#817=EDGE_CURVE('E140',#814,#816,#812,.T.);
#818=ORIENTED_EDGE('',*,*,#817,.F.);
#819=CARTESIAN_POINT('',(7.61123118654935,21.1830391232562,-8.55558985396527));
#820=CARTESIAN_POINT('',(7.57491118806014,21.1201310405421,-8.83174684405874));
#821=CARTESIAN_POINT('',(7.32612653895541,21.2596298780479,-8.84536760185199));
#822=CARTESIAN_POINT('',(7.14834835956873,20.3813025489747,-8.31214514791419));
#823=CARTESIAN_POINT('',(7.11245730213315,20.3191374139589,-8.58793733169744));
#824=CARTESIAN_POINT('',(6.863826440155,20.4576960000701,-8.60192289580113));
#825=CARTESIAN_POINT('',(6.68541201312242,19.5794732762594,-8.06910132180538));
#826=CARTESIAN_POINT('',(6.64988004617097,19.5179301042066,-8.34442822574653));
#827=CARTESIAN_POINT('',(6.40152825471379,19.6556514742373,-8.35887906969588));
#828=CARTESIAN_POINT('',(5.75902963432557,17.9749319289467,-7.58440903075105));
#829=CARTESIAN_POINT('',(5.72390360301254,17.9140918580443,-7.8584468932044));
#830=CARTESIAN_POINT('',(5.47663891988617,18.0506377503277,-7.874186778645));
#831=CARTESIAN_POINT('',(5.29558346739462,17.1722196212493,-7.34276159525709));
#832=CARTESIAN_POINT('',(5.26080405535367,17.111979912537,-7.61612935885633));
#833=CARTESIAN_POINT('',(5.0140477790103,17.2476682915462,-7.63253934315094));
#834=CARTESIAN_POINT('',(4.35666662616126,15.545967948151,-6.85569776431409));
#835=CARTESIAN_POINT('',(4.32238974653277,15.4865986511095,-7.12731783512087));
#836=CARTESIAN_POINT('',(4.07718877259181,15.6208476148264,-7.14547551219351));
#837=CARTESIAN_POINT('',(3.88118826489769,14.7224152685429,-6.61034060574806));
#838=CARTESIAN_POINT('',(3.84748393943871,14.6640376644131,-6.88108543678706));
#839=CARTESIAN_POINT('',(3.60292146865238,14.7969818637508,-6.9001183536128));
#840=CARTESIAN_POINT('',(2.93002562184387,13.0749532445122,-6.12383947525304));
#841=CARTESIAN_POINT('',(2.89709389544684,13.0179138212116,-6.39216776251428));
#842=CARTESIAN_POINT('',(2.65474442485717,13.1488478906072,-6.41361722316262));
#843=CARTESIAN_POINT('',(2.45434168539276,12.2510444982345,-5.88269281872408));
#844=CARTESIAN_POINT('',(2.4223507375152,12.1956345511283,-6.14984390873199));
#845=CARTESIAN_POINT('',(2.18083465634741,12.3245802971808,-6.17247056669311));
#846=CARTESIAN_POINT('',(1.75255773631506,11.0355190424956,-5.53294307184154));
#847=CARTESIAN_POINT('',(1.72021507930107,10.9794999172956,-5.79690487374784));
#848=CARTESIAN_POINT('',(1.48243860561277,11.1085537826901,-5.82272081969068));
#849=CARTESIAN_POINT('',(1.52682941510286,10.6445461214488,-5.42136208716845));
#850=CARTESIAN_POINT('',(1.49489405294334,10.5892324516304,-5.68446410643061));
#851=CARTESIAN_POINT('',(1.25791724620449,10.7174240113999,-5.71113983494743));
#852=CARTESIAN_POINT('',(1.07506727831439,9.86207114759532,-5.20067849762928));
#853=CARTESIAN_POINT('',(1.04389094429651,9.80807215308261,-5.46179745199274));
#854=CARTESIAN_POINT('',(0.808900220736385,9.93467370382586,-5.49045624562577));
#855=CARTESIAN_POINT('',(0.849033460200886,9.47056909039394,-5.09157591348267));
#856=CARTESIAN_POINT('',(0.818386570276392,9.41748711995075,-5.35165029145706));
#857=CARTESIAN_POINT('',(0.584404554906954,9.54305316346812,-5.38135366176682));
#858=CARTESIAN_POINT('',(0.396069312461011,8.68601217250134,-4.87674409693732));
#859=CARTESIAN_POINT('',(0.366445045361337,8.63470143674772,-5.1344034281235));
#860=CARTESIAN_POINT('',(0.134983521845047,8.75835650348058,-5.16652184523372));
#861=CARTESIAN_POINT('',(0.169138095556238,8.29295577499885,-4.77102231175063));
#862=CARTESIAN_POINT('',(0.140236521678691,8.24289678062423,-5.02740455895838));
#863=CARTESIAN_POINT('',(-0.0899417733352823,8.36527904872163,-5.06080005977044));
#864=CARTESIAN_POINT('',(-0.285345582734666,7.50576695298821,-4.56505534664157));
#865=CARTESIAN_POINT('',(-0.312820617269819,7.45817879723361,-4.81848453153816));
#866=CARTESIAN_POINT('',(-0.539752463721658,7.57827322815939,-4.85483309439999));
#867=CARTESIAN_POINT('',(-0.512898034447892,7.11163454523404,-4.46481008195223));
#868=CARTESIAN_POINT('',(-0.539373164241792,7.06577827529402,-4.71666888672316));
#869=CARTESIAN_POINT('',(-0.764637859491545,7.18434487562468,-4.75458782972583));
#870=CARTESIAN_POINT('',(-0.965655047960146,6.32743639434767,-4.27436791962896));
#871=CARTESIAN_POINT('',(-0.990117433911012,6.28506629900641,-4.52267428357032));
#872=CARTESIAN_POINT('',(-1.21118051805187,6.40105138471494,-4.5641456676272));
#873=CARTESIAN_POINT('',(-1.19084639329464,5.93739354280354,-4.184047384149));
#874=CARTESIAN_POINT('',(-1.21394070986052,5.89739301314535,-4.43047216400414));
#875=CARTESIAN_POINT('',(-1.4328377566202,6.01170196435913,-4.47382513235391));
#876=CARTESIAN_POINT('',(-1.64257926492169,5.1549692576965,-4.01707291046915));
#877=CARTESIAN_POINT('',(-1.66271797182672,5.12008799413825,-4.25943247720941));
#878=CARTESIAN_POINT('',(-1.87635689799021,5.23168790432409,-4.30685065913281));
#879=CARTESIAN_POINT('',(-1.86912112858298,4.7625872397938,-3.94042254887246));
#880=CARTESIAN_POINT('',(-1.8873877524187,4.73094851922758,-4.18059335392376));
#881=CARTESIAN_POINT('',(-2.09821883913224,4.84102294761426,-4.23020029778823));
#882=CARTESIAN_POINT('',(-2.32311926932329,3.97623939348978,-3.80992031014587));
#883=CARTESIAN_POINT('',(-2.337137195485,3.95195963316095,-4.04600903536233));
#884=CARTESIAN_POINT('',(-2.54185284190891,4.06009928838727,-4.09969805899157));
#885=CARTESIAN_POINT('',(-2.55056920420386,3.5822845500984,-3.75598635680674));
#886=CARTESIAN_POINT('',(-2.56229119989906,3.5619814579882,-3.98996132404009));
#887=CARTESIAN_POINT('',(-2.76362228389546,3.66984429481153,-4.04576410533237));
#888=CARTESIAN_POINT('',(-2.89270035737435,2.98969600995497,-3.70029165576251));
#889=CARTESIAN_POINT('',(-2.90051641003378,2.97615820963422,-3.93207627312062));
#890=CARTESIAN_POINT('',(-3.09747471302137,3.08479578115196,-3.99006940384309));
#891=CARTESIAN_POINT('',(-3.00686662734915,2.791954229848,-3.68592836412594));
#892=CARTESIAN_POINT('',(-3.0132311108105,2.78093062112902,-3.91711556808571));
#893=CARTESIAN_POINT('',(-3.20892257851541,2.88989781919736,-3.97570611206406));
#894=CARTESIAN_POINT('',(-3.23539205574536,2.39613657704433,-3.66664521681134));
#895=CARTESIAN_POINT('',(-3.23857973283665,2.39061535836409,-3.89705602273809));
#896=CARTESIAN_POINT('',(-3.4323757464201,2.5003310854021,-3.95642296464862));
#897=CARTESIAN_POINT('',(-3.34975118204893,2.19806075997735,-3.66172391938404));
#898=CARTESIAN_POINT('',(-3.35139245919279,2.19521798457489,-3.89192321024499));
#899=CARTESIAN_POINT('',(-3.544380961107,2.30566228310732,-3.95150166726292));
#900=CARTESIAN_POINT('',(-3.50978592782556,1.92087244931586,-3.66171696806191));
#901=CARTESIAN_POINT('',(-3.50913015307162,1.92200828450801,-3.89191458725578));
#902=CARTESIAN_POINT('',(-3.70152527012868,2.03347809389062,-3.95149471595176));
#903=CARTESIAN_POINT('',(-3.55546885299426,1.8417473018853,-3.6624996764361));
#904=CARTESIAN_POINT('',(-3.55416444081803,1.84400661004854,-3.89273007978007));
#905=CARTESIAN_POINT('',(-3.74642913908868,1.95580835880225,-3.95227742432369));
#906=CARTESIAN_POINT('',(-3.64682245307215,1.68351822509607,-3.66561475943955));
#907=CARTESIAN_POINT('',(-3.6442140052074,1.68803618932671,-3.89597279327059));
#908=CARTESIAN_POINT('',(-3.83632424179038,1.80052369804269,-3.95539250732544));
#909=CARTESIAN_POINT('',(-3.69249312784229,1.60441429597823,-3.66794715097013));
#910=CARTESIAN_POINT('',(-3.68924157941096,1.61004614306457,-3.8984009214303));
#911=CARTESIAN_POINT('',(-3.88131547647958,1.72290877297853,-3.95772489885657));
#912=CARTESIAN_POINT('',(-3.82950397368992,1.36710454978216,-3.67723166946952));
#913=CARTESIAN_POINT('',(-3.82436213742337,1.37601047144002,-3.90806527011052));
#914=CARTESIAN_POINT('',(-4.01644472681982,1.49009005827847,-3.96700941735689));
#915=CARTESIAN_POINT('',(-3.92080623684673,1.20896439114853,-3.68647110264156));
#916=CARTESIAN_POINT('',(-3.91445378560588,1.21996715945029,-3.91768701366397));
#917=CARTESIAN_POINT('',(-4.10670223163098,1.33497476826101,-3.97624885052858));
#918=CARTESIAN_POINT('',(-4.19477955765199,0.734428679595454,-3.72273800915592));
#919=CARTESIAN_POINT('',(-4.18503615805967,0.751304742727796,-3.95540495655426));
#920=CARTESIAN_POINT('',(-4.37816374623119,0.86937511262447,-4.01251575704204));
#921=CARTESIAN_POINT('',(-4.37717412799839,0.418512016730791,-3.75831137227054));
#922=CARTESIAN_POINT('',(-4.36539673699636,0.438911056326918,-3.99241678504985));
#923=CARTESIAN_POINT('',(-4.5597199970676,0.559219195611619,-4.04808912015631));
#924=CARTESIAN_POINT('',(-4.65065751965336,-0.0551751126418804,-3.82480471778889));
#925=CARTESIAN_POINT('',(-4.63549818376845,-0.0289183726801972,-4.06107376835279));
#926=CARTESIAN_POINT('',(-4.83278724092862,0.0933721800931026,-4.11458246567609));
#927=CARTESIAN_POINT('',(-4.74217033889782,-0.213679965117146,-3.84928400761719));
#928=CARTESIAN_POINT('',(-4.726080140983,-0.185810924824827,-4.0863647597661));
#929=CARTESIAN_POINT('',(-4.9243033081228,-0.0626443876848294,-4.13906175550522));
#930=CARTESIAN_POINT('',(-4.9249424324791,-0.530250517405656,-3.9019070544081));
#931=CARTESIAN_POINT('',(-4.90710566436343,-0.499356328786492,-4.14062943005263));
#932=CARTESIAN_POINT('',(-5.10728053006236,-0.374525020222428,-4.19168480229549));
#933=CARTESIAN_POINT('',(-5.01620168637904,-0.688316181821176,-3.93005109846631));
#934=CARTESIAN_POINT('',(-4.99755743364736,-0.656023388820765,-4.16961875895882));
#935=CARTESIAN_POINT('',(-5.198741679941,-0.530389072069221,-4.21982884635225));
#936=CARTESIAN_POINT('',(-5.19824692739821,-1.00362778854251,-3.9892892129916));
#937=CARTESIAN_POINT('',(-5.17809955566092,-0.968731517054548,-4.23053091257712));
#938=CARTESIAN_POINT('',(-5.38132017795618,-0.841584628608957,-4.2790669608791));
#939=CARTESIAN_POINT('',(-5.28903352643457,-1.16087479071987,-4.0203758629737));
#940=CARTESIAN_POINT('',(-5.26818514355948,-1.12476433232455,-4.26245525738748));
#941=CARTESIAN_POINT('',(-5.47243781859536,-0.996916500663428,-4.31015361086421));
#942=CARTESIAN_POINT('',(-5.47036783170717,-1.4749550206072,-4.0850307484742));
#943=CARTESIAN_POINT('',(-5.44823424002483,-1.43661851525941,-4.32876154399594));
#944=CARTESIAN_POINT('',(-5.65451402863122,-1.30742143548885,-4.37480849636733));
#945=CARTESIAN_POINT('',(-5.56091558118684,-1.63178832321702,-4.11859849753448));
#946=CARTESIAN_POINT('',(-5.53818436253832,-1.59241669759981,-4.36314658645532));
#947=CARTESIAN_POINT('',(-5.74547262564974,-1.46259452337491,-4.40837624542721));
#948=CARTESIAN_POINT('',(-5.65136623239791,-1.78845344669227,-4.1531497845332));
#949=CARTESIAN_POINT('',(-5.62793136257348,-1.7478630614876,-4.3984261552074));
#950=CARTESIAN_POINT('',(-5.83634927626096,-1.61771364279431,-4.44292753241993));
#951=(BOUNDED_SURFACE() B_SPLINE_SURFACE(3,2,((#819,#820,#821),(#822,#823,#824),(#825,#826,
#827),(#828,#829,#830),(#831,#832,#833),(#834,#835,#836),(#837,#838,#839),(#840,#841,#842),
(#843,#844,#845),(#846,#847,#848),(#849,#850,#851),(#852,#853,#854),(#855,#856,#857),(#858,#859,
#860),(#861,#862,#863),(#864,#865,#866),(#867,#868,#869),(#870,#871,#872),(#873,#874,#875),
(#876,#877,#878),(#879,#880,#881),(#882,#883,#884),(#885,#886,#887),(#888,#889,#890),(#891,#892,
#893),(#894,#895,#896),(#897,#898,#899),(#900,#901,#902),(#903,#904,#905),(#906,#907,#908),
(#909,#910,#911),(#912,#913,#914),(#915,#916,#917),(#918,#919,#920),(#921,#922,#923),(#924,#925,
#926),(#927,#928,#929),(#930,#931,#932),(#933,#934,#935),(#936,#937,#938),(#939,#940,#941),
(#942,#943,#944),(#945,#946,#947),(#948,#949,#950)),.UNSPECIFIED.,.F.,.F.,
.F.) B_SPLINE_SURFACE_WITH_KNOTS((4,2,2,2,2,2,2,2,2,2,2,2,2,2,2,2,2,2,2,2,2,4),(3,3),(0.,
2.87172082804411,5.74534141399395,8.69163587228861,11.6359776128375,13.0310968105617,
14.4262276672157,15.8242453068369,17.222241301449,18.600159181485,19.978437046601,
21.3516914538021,22.0378780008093,22.7239597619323,22.9980573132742,23.272157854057,
23.8205791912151,24.9194760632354,25.4734222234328,26.0274118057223,26.5800398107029,
27.1325597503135),(0.,1.),
.UNSPECIFIED.) GEOMETRIC_REPRESENTATION_ITEM() RATIONAL_B_SPLINE_SURFACE(((1.,0.72433504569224,
1.),(1.,0.72502874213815,1.),(1.,0.72578775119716,1.),(1.,0.72754165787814,1.),(1.,
0.728536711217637,1.),(1.,0.730896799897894,1.),(1.,0.732270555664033,1.),(1.,0.73558815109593,
1.),(1.,0.737531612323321,1.),(1.,0.741117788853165,1.),(1.,0.742380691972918,1.),(1.,
0.745198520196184,1.),(1.,0.74675344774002,1.),(1.,0.750247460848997,1.),(1.,0.752187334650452,
1.),(1.,0.756556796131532,1.),(1.,0.758986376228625,1.),(1.,0.764379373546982,1.),(1.,
0.767334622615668,1.),(1.,0.773723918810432,1.),(1.,0.777158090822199,1.),(1.,0.783844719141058,
1.),(1.,0.787097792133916,1.),(1.,0.790686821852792,1.),(1.,0.791667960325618,1.),(1.,
0.79300075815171,1.),(1.,0.793352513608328,1.),(1.,0.793353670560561,1.),(1.,0.793297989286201,
1.),(1.,0.793078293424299,1.),(1.,0.792914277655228,1.),(1.,0.792266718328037,1.),(1.,
0.791627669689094,1.),(1.,0.789211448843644,1.),(1.,0.786935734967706,1.),(1.,0.783154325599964,
1.),(1.,0.78182642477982,1.),(1.,0.779132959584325,1.),(1.,0.777767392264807,1.),(1.,
0.77506282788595,1.),(1.,0.773723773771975,1.),(1.,0.771102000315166,1.),(1.,0.769819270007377,
1.),(1.,0.768581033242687,1.))) REPRESENTATION_ITEM('') SURFACE());
#952=CARTESIAN_POINT('',(7.61123118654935,21.1830391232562,-8.55558985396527));
#953=CARTESIAN_POINT('',(7.14834835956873,20.3813025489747,-8.31214514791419));
#954=CARTESIAN_POINT('',(6.68541201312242,19.5794732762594,-8.06910132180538));
#955=CARTESIAN_POINT('',(5.75902963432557,17.9749319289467,-7.58440903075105));
#956=CARTESIAN_POINT('',(5.29558346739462,17.1722196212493,-7.3427615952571));
#957=CARTESIAN_POINT('',(4.35666662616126,15.545967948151,-6.85569776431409));
#958=CARTESIAN_POINT('',(3.88118826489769,14.7224152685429,-6.61034060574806));
#959=CARTESIAN_POINT('',(2.93002562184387,13.0749532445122,-6.12383947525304));
#960=CARTESIAN_POINT('',(2.45434168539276,12.2510444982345,-5.88269281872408));
#961=CARTESIAN_POINT('',(1.75255773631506,11.0355190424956,-5.53294307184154));
#962=CARTESIAN_POINT('',(1.52682941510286,10.6445461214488,-5.42136208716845));
#963=CARTESIAN_POINT('',(1.07506727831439,9.86207114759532,-5.20067849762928));
#964=CARTESIAN_POINT('',(0.849033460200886,9.47056909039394,-5.09157591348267));
#965=CARTESIAN_POINT('',(0.396069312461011,8.68601217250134,-4.87674409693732));
#966=CARTESIAN_POINT('',(0.169138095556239,8.29295577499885,-4.77102231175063));
#967=CARTESIAN_POINT('',(-0.285345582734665,7.50576695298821,-4.56505534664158));
#968=CARTESIAN_POINT('',(-0.512898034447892,7.11163454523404,-4.46481008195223));
#969=CARTESIAN_POINT('',(-0.965655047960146,6.32743639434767,-4.27436791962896));
#970=CARTESIAN_POINT('',(-1.19084639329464,5.93739354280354,-4.184047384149));
#971=CARTESIAN_POINT('',(-1.64257926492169,5.15496925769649,-4.01707291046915));
#972=CARTESIAN_POINT('',(-1.86912112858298,4.7625872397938,-3.94042254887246));
#973=CARTESIAN_POINT('',(-2.32311926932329,3.97623939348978,-3.80992031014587));
#974=CARTESIAN_POINT('',(-2.55056920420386,3.5822845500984,-3.75598635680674));
#975=CARTESIAN_POINT('',(-2.89270035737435,2.98969600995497,-3.70029165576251));
#976=CARTESIAN_POINT('',(-3.00686662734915,2.791954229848,-3.68592836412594));
#977=CARTESIAN_POINT('',(-3.23539205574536,2.39613657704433,-3.66664521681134));
#978=CARTESIAN_POINT('',(-3.34975118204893,2.19806075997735,-3.66172391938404));
#979=CARTESIAN_POINT('',(-3.50978592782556,1.92087244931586,-3.66171696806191));
#980=CARTESIAN_POINT('',(-3.55546885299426,1.8417473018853,-3.6624996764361));
#981=CARTESIAN_POINT('',(-3.64682245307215,1.68351822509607,-3.66561475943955));
#982=CARTESIAN_POINT('',(-3.69249312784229,1.60441429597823,-3.66794715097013));
#983=CARTESIAN_POINT('',(-3.82950397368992,1.36710454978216,-3.67723166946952));
#984=CARTESIAN_POINT('',(-3.92080623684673,1.20896439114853,-3.68647110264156));
#985=CARTESIAN_POINT('',(-4.19477955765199,0.734428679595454,-3.72273800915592));
#986=CARTESIAN_POINT('',(-4.37717412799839,0.418512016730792,-3.75831137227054));
#987=CARTESIAN_POINT('',(-4.65065751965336,-0.0551751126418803,-3.82480471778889));
#988=CARTESIAN_POINT('',(-4.74217033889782,-0.213679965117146,-3.84928400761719));
#989=CARTESIAN_POINT('',(-4.9249424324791,-0.530250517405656,-3.9019070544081));
#990=CARTESIAN_POINT('',(-5.01620168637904,-0.688316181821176,-3.93005109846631));
#991=CARTESIAN_POINT('',(-5.19824692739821,-1.0036277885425,-3.9892892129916));
#992=CARTESIAN_POINT('',(-5.28903352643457,-1.16087479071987,-4.0203758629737));
#993=CARTESIAN_POINT('',(-5.47036783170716,-1.4749550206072,-4.0850307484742));
#994=CARTESIAN_POINT('',(-5.56091558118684,-1.63178832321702,-4.11859849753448));
#995=CARTESIAN_POINT('',(-5.65136623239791,-1.78845344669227,-4.1531497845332));
#996=B_SPLINE_CURVE_WITH_KNOTS('',3,(#952,#953,#954,#955,#956,#957,#958,#959,#960,#961,#962,
#963,#964,#965,#966,#967,#968,#969,#970,#971,#972,#973,#974,#975,#976,#977,#978,#979,#980,#981,
#982,#983,#984,#985,#986,#987,#988,#989,#990,#991,#992,#993,#994,#995),.UNSPECIFIED.,.F.,.F.,(4,
2,2,2,2,2,2,2,2,2,2,2,2,2,2,2,2,2,2,2,2,4),(0.,2.87172082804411,5.74534141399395,
8.69163587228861,11.6359776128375,13.0310968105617,14.4262276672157,15.8242453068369,
17.222241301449,18.600159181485,19.978437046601,21.3516914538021,22.0378780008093,
22.7239597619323,22.9980573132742,23.272157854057,23.8205791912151,24.9194760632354,
25.4734222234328,26.0274118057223,26.5800398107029,27.1325597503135),.UNSPECIFIED.);
#997=EDGE_CURVE('E137',#814,#566,#996,.T.);
#998=ORIENTED_EDGE('',*,*,#997,.T.);
#999=ORIENTED_EDGE('',*,*,#569,.T.);
#1000=CARTESIAN_POINT('',(-2.30933154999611,4.00012042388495,-1.78020000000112));
#1001=CARTESIAN_POINT('',(-2.329672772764,3.9648883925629,-1.72169220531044));
#1002=CARTESIAN_POINT('',(-2.35028187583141,3.92919237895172,-1.66355827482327));
#1003=CARTESIAN_POINT('',(-2.3921122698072,3.85674001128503,-1.54815677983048));
#1004=CARTESIAN_POINT('',(-2.41333371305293,3.81998339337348,-1.4908894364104));
#1005=CARTESIAN_POINT('',(-2.4783056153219,3.70744875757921,-1.31984609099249));
#1006=CARTESIAN_POINT('',(-2.52309209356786,3.62987630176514,-1.20761921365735));
#1007=CARTESIAN_POINT('',(-2.61818869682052,3.46516415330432,-0.98424503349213));
#1008=CARTESIAN_POINT('',(-2.66865503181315,3.37775389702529,-0.873361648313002));
#1009=CARTESIAN_POINT('',(-2.77442244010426,3.19455937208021,-0.661563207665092));
#1010=CARTESIAN_POINT('',(-2.82970800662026,3.09880196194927,-0.560618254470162));
#1011=CARTESIAN_POINT('',(-2.91065283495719,2.95860140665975,-0.431782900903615));
#1012=CARTESIAN_POINT('',(-2.93362248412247,2.91881680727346,-0.397143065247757));
#1013=CARTESIAN_POINT('',(-2.98058363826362,2.83747770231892,-0.330748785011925));
#1014=CARTESIAN_POINT('',(-3.00457540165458,2.7959227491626,-0.298995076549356));
#1015=CARTESIAN_POINT('',(-3.07782339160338,2.66905350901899,-0.209445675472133));
#1016=CARTESIAN_POINT('',(-3.12873106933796,2.58087882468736,-0.156734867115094));
#1017=CARTESIAN_POINT('',(-3.22066888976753,2.42163784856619,-0.0827968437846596));
#1018=CARTESIAN_POINT('',(-3.26075482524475,2.35220697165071,-0.0569308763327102));
#1019=CARTESIAN_POINT('',(-3.34254671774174,2.21053925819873,-0.0188566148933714));
#1020=CARTESIAN_POINT('',(-3.38425146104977,2.1383045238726,-0.0066382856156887));
#1021=CARTESIAN_POINT('',(-3.46826163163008,1.99279464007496,0.00251875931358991));
#1022=CARTESIAN_POINT('',(-3.5105687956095,1.91951648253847,-0.000603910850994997));
#1023=CARTESIAN_POINT('',(-3.59423504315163,1.77460229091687,-0.0218132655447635));
#1024=CARTESIAN_POINT('',(-3.63559318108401,1.70296789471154,-0.0399142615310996));
#1025=CARTESIAN_POINT('',(-3.72775187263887,1.54334435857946,-0.0957585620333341));
#1026=CARTESIAN_POINT('',(-3.77791738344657,1.45645514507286,-0.137607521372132));
#1027=CARTESIAN_POINT('',(-3.87438442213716,1.28936933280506,-0.236407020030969));
#1028=CARTESIAN_POINT('',(-3.92067460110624,1.20919239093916,-0.293400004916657));
#1029=CARTESIAN_POINT('',(-4.00728859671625,1.05917254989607,-0.414494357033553));
#1030=CARTESIAN_POINT('',(-4.04779671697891,0.989010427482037,-0.478080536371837));
#1031=CARTESIAN_POINT('',(-4.12601423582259,0.853533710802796,-0.611867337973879));
#1032=CARTESIAN_POINT('',(-4.16372066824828,0.788224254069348,-0.682074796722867));
#1033=CARTESIAN_POINT('',(-4.23687359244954,0.661519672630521,-0.827445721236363));
#1034=CARTESIAN_POINT('',(-4.27231261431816,0.600137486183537,-0.902624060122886));
#1035=CARTESIAN_POINT('',(-4.34118808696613,0.480841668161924,-1.05648002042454));
#1036=CARTESIAN_POINT('',(-4.37462539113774,0.422926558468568,-1.13515612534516));
#1037=CARTESIAN_POINT('',(-4.44457071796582,0.301777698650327,-1.30677603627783));
#1038=CARTESIAN_POINT('',(-4.48082190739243,0.238988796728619,-1.40013569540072));
#1039=CARTESIAN_POINT('',(-4.55123163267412,0.117035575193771,-1.58876843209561));
#1040=CARTESIAN_POINT('',(-4.58540498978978,0.0578455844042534,-1.68401931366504));
#1041=CARTESIAN_POINT('',(-4.61887168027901,-0.000120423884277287,-1.7802));
#1042=B_SPLINE_CURVE_WITH_KNOTS('',3,(#1000,#1001,#1002,#1003,#1004,#1005,#1006,#1007,#1008,
#1009,#1010,#1011,#1012,#1013,#1014,#1015,#1016,#1017,#1018,#1019,#1020,#1021,#1022,#1023,#1024,
#1025,#1026,#1027,#1028,#1029,#1030,#1031,#1032,#1033,#1034,#1035,#1036,#1037,#1038,#1039,#1040,
#1041),.UNSPECIFIED.,.F.,.F.,(4,2,2,2,2,2,2,2,2,2,2,2,2,2,2,2,2,2,2,2,4),(0.,0.213777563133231,
0.427608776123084,0.858145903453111,1.30759304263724,1.75564391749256,1.92815043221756,
2.10070082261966,2.44287249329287,2.69463411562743,2.9462104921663,3.19879434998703,
3.45161982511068,3.77590275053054,4.10110434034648,4.40960953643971,4.71843682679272,
5.02823407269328,5.33789828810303,5.6924202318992,6.04401162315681),.UNSPECIFIED.);
#1043=CARTESIAN_POINT('',(-3.46410161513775,2.,0.));
#1044=VERTEX_POINT('',#1043);
#1045=EDGE_CURVE('E135',#1044,#568,#1042,.T.);
#1046=ORIENTED_EDGE('',*,*,#1045,.F.);
#1047=EDGE_CURVE('E153',#816,#1044,#1042,.T.);
#1048=ORIENTED_EDGE('',*,*,#1047,.F.);
#1049=EDGE_LOOP('',(#818,#998,#999,#1046,#1048));
#1050=FACE_BOUND('',#1049,.T.);
#1051=ADVANCED_FACE('F133',(#1050),#808,.T.);
#1052=CARTESIAN_POINT('',(2.3094010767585,4.,-5.3));
#1053=DIRECTION('',(0.,1.,0.));
#1054=DIRECTION('',(-1.,0.,0.));
#1055=AXIS2_PLACEMENT_3D('',#1052,#1053,#1054);
#1056=PLANE('',#1055);
#1057=DIRECTION('',(0.,0.,1.));
#1058=VECTOR('',#1057,1.);
#1059=CARTESIAN_POINT('',(2.3094010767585,4.,-5.3));
#1060=LINE('',#1059,#1058);
#1061=CARTESIAN_POINT('',(2.3094010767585,4.,-3.81737471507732));
#1062=VERTEX_POINT('',#1061);
#1063=CARTESIAN_POINT('',(2.30940107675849,4.00000000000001,-1.78));
#1064=VERTEX_POINT('',#1063);
#1065=EDGE_CURVE('E159',#1062,#1064,#1060,.T.);
#1066=ORIENTED_EDGE('',*,*,#1065,.F.);
#1067=CARTESIAN_POINT('',(22.1188668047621,4.,-8.54722575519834));
#1068=CARTESIAN_POINT('',(22.0462353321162,4.00000000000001,-8.82336476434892));
#1069=CARTESIAN_POINT('',(22.0426480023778,4.28518274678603,-8.83700350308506));
#1070=CARTESIAN_POINT('',(21.1946054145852,4.00000000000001,-8.30418942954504));
#1071=CARTESIAN_POINT('',(21.1228321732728,4.00000000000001,-8.5799631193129));
#1072=CARTESIAN_POINT('',(21.1185074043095,4.2845787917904,-8.59396717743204));
#1073=CARTESIAN_POINT('',(20.2702368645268,4.,-8.06155444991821));
#1074=CARTESIAN_POINT('',(20.1991816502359,4.00000000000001,-8.33686215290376));
#1075=CARTESIAN_POINT('',(20.1942718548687,4.28391779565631,-8.35133219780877));
#1076=CARTESIAN_POINT('',(18.4204834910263,4.,-7.57768195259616));
#1077=CARTESIAN_POINT('',(18.3502408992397,4.,-7.85169940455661));
#1078=CARTESIAN_POINT('',(18.3448567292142,4.28238706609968,-7.86745970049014));
#1079=CARTESIAN_POINT('',(17.4950983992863,4.,-7.33644546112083));
#1080=CARTESIAN_POINT('',(17.4255492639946,4.,-7.60979211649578));
#1081=CARTESIAN_POINT('',(17.4196769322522,4.28151719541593,-7.62622320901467));
#1082=CARTESIAN_POINT('',(15.6203737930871,4.,-6.8502301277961));
#1083=CARTESIAN_POINT('',(15.551830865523,4.,-7.12182785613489));
#1084=CARTESIAN_POINT('',(15.5454896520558,4.27944884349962,-7.14000787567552));
#1085=CARTESIAN_POINT('',(14.6710189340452,4.,-6.60531041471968));
#1086=CARTESIAN_POINT('',(14.6036209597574,4.,-6.87603207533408));
#1087=CARTESIAN_POINT('',(14.5964698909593,4.27824262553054,-6.89508816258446));
#1088=CARTESIAN_POINT('',(12.7718935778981,4.,-6.11968437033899));
#1089=CARTESIAN_POINT('',(12.706042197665,4.,-6.38798839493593));
#1090=CARTESIAN_POINT('',(12.6982571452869,4.27531933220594,-6.40946211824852));
#1091=CARTESIAN_POINT('',(11.8221237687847,4.,-5.87897536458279));
#1092=CARTESIAN_POINT('',(11.7581527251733,4.,-6.14610115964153));
#1093=CARTESIAN_POINT('',(11.749064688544,4.27360259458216,-6.16875311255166));
#1094=CARTESIAN_POINT('',(10.4208753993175,4.,-5.52986072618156));
#1095=CARTESIAN_POINT('',(10.3562064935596,4.,-5.79379809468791));
#1096=CARTESIAN_POINT('',(10.3490782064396,4.27041718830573,-5.81963847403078));
#1097=CARTESIAN_POINT('',(9.97013994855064,4.,-5.41847780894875));
#1098=CARTESIAN_POINT('',(9.90628576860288,4.,-5.68155522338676));
#1099=CARTESIAN_POINT('',(9.89881107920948,4.26929322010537,-5.70825555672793));
#1100=CARTESIAN_POINT('',(9.0680583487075,4.,-5.19818967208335));
#1101=CARTESIAN_POINT('',(9.00572328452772,4.,-5.45928412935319));
#1102=CARTESIAN_POINT('',(8.9978650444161,4.26677789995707,-5.48796742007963));
#1103=CARTESIAN_POINT('',(8.61671219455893,4.,-5.08928447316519));
#1104=CARTESIAN_POINT('',(8.55543600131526,4.,-5.34933438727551));
#1105=CARTESIAN_POINT('',(8.54718613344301,4.26538654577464,-5.37906222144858));
#1106=CARTESIAN_POINT('',(7.71223265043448,4.,-4.87484654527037));
#1107=CARTESIAN_POINT('',(7.65300260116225,4.,-5.13248218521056));
#1108=CARTESIAN_POINT('',(7.64435868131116,4.26224868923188,-5.16462429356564));
#1109=CARTESIAN_POINT('',(7.25909749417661,4.,-4.76932123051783));
#1110=CARTESIAN_POINT('',(7.20131231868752,4.,-5.0256801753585));
#1111=CARTESIAN_POINT('',(7.19220902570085,4.26050146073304,-5.05909897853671));
#1112=CARTESIAN_POINT('',(6.35158630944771,4.,-4.56374155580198));
#1113=CARTESIAN_POINT('',(6.29665448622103,4.,-4.81714937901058));
#1114=CARTESIAN_POINT('',(6.28719405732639,4.25654795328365,-4.85351930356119));
#1115=CARTESIAN_POINT('',(5.89721030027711,4.,-4.46368711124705));
#1116=CARTESIAN_POINT('',(5.84427682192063,4.,-4.71552559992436));
#1117=CARTESIAN_POINT('',(5.83432875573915,4.25434168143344,-4.75346485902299));
#1118=CARTESIAN_POINT('',(4.99312971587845,4.,-4.27360636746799));
#1119=CARTESIAN_POINT('',(4.94422055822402,4.,-4.52189612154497));
#1120=CARTESIAN_POINT('',(4.93413854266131,4.24941660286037,-4.56338411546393));
#1121=CARTESIAN_POINT('',(4.54345145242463,4.,-4.18345695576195));
#1122=CARTESIAN_POINT('',(4.49727542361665,4.,-4.42986713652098));
#1123=CARTESIAN_POINT('',(4.4868271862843,4.24670559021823,-4.4732347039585));
#1124=CARTESIAN_POINT('',(3.6414017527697,4.,-4.01679463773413));
#1125=CARTESIAN_POINT('',(3.60113183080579,4.,-4.25914547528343));
#1126=CARTESIAN_POINT('',(3.59096705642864,4.24080527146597,-4.30657238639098));
#1127=CARTESIAN_POINT('',(3.18902964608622,4.,-3.94028528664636));
#1128=CARTESIAN_POINT('',(3.15249836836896,4.,-4.18045094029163));
#1129=CARTESIAN_POINT('',(3.14241799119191,4.23761584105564,-4.23006303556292));
#1130=CARTESIAN_POINT('',(2.2824594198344,4.,-3.80999477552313));
#1131=CARTESIAN_POINT('',(2.2544136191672,4.,-4.04608484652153));
#1132=CARTESIAN_POINT('',(2.24571228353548,4.23136221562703,-4.09977252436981));
#1133=CARTESIAN_POINT('',(1.8282738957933,4.,-3.7561320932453));
#1134=CARTESIAN_POINT('',(1.80481383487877,4.,-3.99011227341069));
#1135=CARTESIAN_POINT('',(1.79756013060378,4.22829760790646,-4.04590984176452));
#1136=CARTESIAN_POINT('',(1.14508719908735,4.,-3.70045408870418));
#1137=CARTESIAN_POINT('',(1.12942407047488,4.,-3.9322449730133));
#1138=CARTESIAN_POINT('',(1.12502182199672,4.22489989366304,-3.99023183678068));
#1139=CARTESIAN_POINT('',(0.917113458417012,4.,-3.6860813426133));
#1140=CARTESIAN_POINT('',(0.904348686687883,4.,-3.9172746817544));
#1141=CARTESIAN_POINT('',(0.900862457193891,4.22396729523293,-3.97585909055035));
#1142=CARTESIAN_POINT('',(0.460779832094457,4.,-3.66674621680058));
#1143=CARTESIAN_POINT('',(0.454357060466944,4.,-3.89716120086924));
#1144=CARTESIAN_POINT('',(0.452463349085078,4.22269690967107,-3.95652396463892));
#1145=CARTESIAN_POINT('',(0.2324200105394,4.,-3.66178240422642));
#1146=CARTESIAN_POINT('',(0.229085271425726,4.,-3.89198408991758));
#1147=CARTESIAN_POINT('',(0.22822362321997,4.22235903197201,-3.95156015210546));
#1148=CARTESIAN_POINT('',(-0.087293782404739,4.,-3.66169428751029));
#1149=CARTESIAN_POINT('',(-0.0860404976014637,4.,-3.89189097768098));
#1150=CARTESIAN_POINT('',(-0.0857176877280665,4.22235243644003,-3.95147203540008));
#1151=CARTESIAN_POINT('',(-0.1786612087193,4.,-3.66245380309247));
#1152=CARTESIAN_POINT('',(-0.176110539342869,4.,-3.89268231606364));
#1153=CARTESIAN_POINT('',(-0.175434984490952,4.22240389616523,-3.95223155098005));
#1154=CARTESIAN_POINT('',(-0.361371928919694,4.,-3.66552286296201));
#1155=CARTESIAN_POINT('',(-0.35621276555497,4.,-3.89587713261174));
#1156=CARTESIAN_POINT('',(-0.354865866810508,4.22260994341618,-3.95530061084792));
#1157=CARTESIAN_POINT('',(-0.452715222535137,4.,-3.66783242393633));
#1158=CARTESIAN_POINT('',(-0.446269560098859,4.,-3.89828150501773));
#1159=CARTESIAN_POINT('',(-0.444579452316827,4.22276453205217,-3.95761017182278));
#1160=CARTESIAN_POINT('',(-0.726742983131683,4.,-3.67704936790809));
#1161=CARTESIAN_POINT('',(-0.716515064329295,4.,-3.90787557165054));
#1162=CARTESIAN_POINT('',(-0.713775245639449,4.22337620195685,-3.96682711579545));
#1163=CARTESIAN_POINT('',(-0.909352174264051,4.,-3.68624499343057));
#1164=CARTESIAN_POINT('',(-0.896702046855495,4.,-3.91745180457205));
#1165=CARTESIAN_POINT('',(-0.893240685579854,4.223981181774,-3.97602274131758));
#1166=CARTESIAN_POINT('',(-1.45731312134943,4.,-3.72238704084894));
#1167=CARTESIAN_POINT('',(-1.43787525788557,4.,-3.95504030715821));
#1168=CARTESIAN_POINT('',(-1.43220058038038,4.22626706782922,-4.01216478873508));
#1169=CARTESIAN_POINT('',(-1.82211350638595,4.,-3.75788611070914));
#1170=CARTESIAN_POINT('',(-1.79860540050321,4.,-3.99197579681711));
#1171=CARTESIAN_POINT('',(-1.79158727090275,4.22841841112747,-4.04766385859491));
#1172=CARTESIAN_POINT('',(-2.3690973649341,4.,-3.82428437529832));
#1173=CARTESIAN_POINT('',(-2.33882038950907,4.,-4.06053603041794));
#1174=CARTESIAN_POINT('',(-2.3315651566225,4.23197565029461,-4.11406212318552));
#1175=CARTESIAN_POINT('',(-2.55212878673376,4.,-3.84873461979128));
#1176=CARTESIAN_POINT('',(-2.51998835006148,4.,-4.08579759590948));
#1177=CARTESIAN_POINT('',(-2.51244058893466,4.23322215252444,-4.13851236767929));
#1178=CARTESIAN_POINT('',(-2.91768436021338,4.,-3.90130458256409));
#1179=CARTESIAN_POINT('',(-2.88204713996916,4.,-4.14000867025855));
#1180=CARTESIAN_POINT('',(-2.87403200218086,4.2357443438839,-4.19108233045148));
#1181=CARTESIAN_POINT('',(-3.10020847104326,4.,-3.92942458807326));
#1182=CARTESIAN_POINT('',(-3.06295461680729,4.,-4.16897387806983));
#1183=CARTESIAN_POINT('',(-3.05474796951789,4.2370200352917,-4.21920233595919));
#1184=CARTESIAN_POINT('',(-3.46431090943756,4.,-3.98861924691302));
#1185=CARTESIAN_POINT('',(-3.42404746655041,4.,-4.22984258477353));
#1186=CARTESIAN_POINT('',(-3.41554789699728,4.23954027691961,-4.27839699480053));
#1187=CARTESIAN_POINT('',(-3.64589045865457,4.,-4.01968648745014));
#1188=CARTESIAN_POINT('',(-3.60422346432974,4.,-4.26174765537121));
#1189=CARTESIAN_POINT('',(-3.59563232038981,4.24078489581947,-4.30946423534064));
#1190=CARTESIAN_POINT('',(-4.00857134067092,4.,-4.08430622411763));
#1191=CARTESIAN_POINT('',(-3.96433101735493,4.,-4.3280191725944));
#1192=CARTESIAN_POINT('',(-3.95558401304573,4.24321596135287,-4.37408397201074));
#1193=CARTESIAN_POINT('',(-4.1896727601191,4.,-4.11785823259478));
#1194=CARTESIAN_POINT('',(-4.14423589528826,4.,-4.36238875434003));
#1195=CARTESIAN_POINT('',(-4.13545131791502,4.24440241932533,-4.40763598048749));
#1196=CARTESIAN_POINT('',(-4.37057976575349,4.,-4.15239525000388));
#1197=CARTESIAN_POINT('',(-4.32373413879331,4.,-4.39765432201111));
#1198=CARTESIAN_POINT('',(-4.31523086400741,4.24554491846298,-4.4421729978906));
#1199=(BOUNDED_SURFACE() B_SPLINE_SURFACE(3,2,((#1067,#1068,#1069),(#1070,#1071,#1072),(#1073,
#1074,#1075),(#1076,#1077,#1078),(#1079,#1080,#1081),(#1082,#1083,#1084),(#1085,#1086,#1087),
(#1088,#1089,#1090),(#1091,#1092,#1093),(#1094,#1095,#1096),(#1097,#1098,#1099),(#1100,#1101,
#1102),(#1103,#1104,#1105),(#1106,#1107,#1108),(#1109,#1110,#1111),(#1112,#1113,#1114),(#1115,
#1116,#1117),(#1118,#1119,#1120),(#1121,#1122,#1123),(#1124,#1125,#1126),(#1127,#1128,#1129),
(#1130,#1131,#1132),(#1133,#1134,#1135),(#1136,#1137,#1138),(#1139,#1140,#1141),(#1142,#1143,
#1144),(#1145,#1146,#1147),(#1148,#1149,#1150),(#1151,#1152,#1153),(#1154,#1155,#1156),(#1157,
#1158,#1159),(#1160,#1161,#1162),(#1163,#1164,#1165),(#1166,#1167,#1168),(#1169,#1170,#1171),
(#1172,#1173,#1174),(#1175,#1176,#1177),(#1178,#1179,#1180),(#1181,#1182,#1183),(#1184,#1185,
#1186),(#1187,#1188,#1189),(#1190,#1191,#1192),(#1193,#1194,#1195),(#1196,#1197,#1198)),
.UNSPECIFIED.,.F.,.F.,.F.) B_SPLINE_SURFACE_WITH_KNOTS((4,2,2,2,2,2,2,2,2,2,2,2,2,2,2,2,2,2,2,2,
2,4),(3,3),(0.,2.86704484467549,5.73597893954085,8.67729232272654,11.6166642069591,
13.0095404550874,14.4024283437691,15.7981873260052,17.1939247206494,18.5696699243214,
19.9457731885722,21.3168795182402,22.0019945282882,22.6870051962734,22.9611068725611,
23.2352114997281,23.7836401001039,24.8825476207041,25.4364993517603,25.9904944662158,
26.5431313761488,27.0956601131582),(0.,1.),
.UNSPECIFIED.) GEOMETRIC_REPRESENTATION_ITEM() RATIONAL_B_SPLINE_SURFACE(((1.,0.724358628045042,
1.),(1.,0.725053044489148,1.),(1.,0.725812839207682,1.),(1.,0.727568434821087,1.),(1.,
0.728564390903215,1.),(1.,0.730926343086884,1.),(1.,0.732301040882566,1.),(1.,0.735620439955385,
1.),(1.,0.737564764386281,1.),(1.,0.741151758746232,1.),(1.,0.742414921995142,1.),(1.,
0.745232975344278,1.),(1.,0.746787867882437,1.),(1.,0.7502812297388,1.),(1.,0.752220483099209,
1.),(1.,0.756587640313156,1.),(1.,0.759015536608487,1.),(1.,0.764403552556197,1.),(1.,
0.767355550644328,1.),(1.,0.773736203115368,1.),(1.,0.777164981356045,1.),(1.,0.783841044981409,
1.),(1.,0.787088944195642,1.),(1.,0.790676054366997,1.),(1.,0.791657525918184,1.),(1.,
0.792993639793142,1.),(1.,0.793348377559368,1.),(1.,0.793355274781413,1.),(1.,0.793301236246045,
1.),(1.,0.793084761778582,1.),(1.,0.792922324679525,1.),(1.,0.792279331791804,1.),(1.,
0.791643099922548,1.),(1.,0.789234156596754,1.),(1.,0.786961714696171,1.),(1.,0.783183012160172,
1.),(1.,0.781855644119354,1.),(1.,0.779162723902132,1.),(1.,0.777797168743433,1.),(1.,
0.775092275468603,1.),(1.,0.773752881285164,1.),(1.,0.771130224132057,1.),(1.,0.769846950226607,
1.),(1.,0.768608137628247,1.))) REPRESENTATION_ITEM('') SURFACE());
#1200=CARTESIAN_POINT('',(22.1188668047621,4.,-8.54722575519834));
#1201=CARTESIAN_POINT('',(21.1946054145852,4.00000000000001,-8.30418942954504));
#1202=CARTESIAN_POINT('',(20.2702368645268,4.,-8.06155444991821));
#1203=CARTESIAN_POINT('',(18.4204834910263,4.,-7.57768195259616));
#1204=CARTESIAN_POINT('',(17.4950983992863,4.,-7.33644546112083));
#1205=CARTESIAN_POINT('',(15.6203737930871,4.,-6.8502301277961));
#1206=CARTESIAN_POINT('',(14.6710189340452,4.,-6.60531041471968));
#1207=CARTESIAN_POINT('',(12.7718935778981,4.,-6.119684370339));
#1208=CARTESIAN_POINT('',(11.8221237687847,4.,-5.87897536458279));
#1209=CARTESIAN_POINT('',(10.4208753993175,4.,-5.52986072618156));
#1210=CARTESIAN_POINT('',(9.97013994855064,4.,-5.41847780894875));
#1211=CARTESIAN_POINT('',(9.0680583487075,4.,-5.19818967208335));
#1212=CARTESIAN_POINT('',(8.61671219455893,4.,-5.08928447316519));
#1213=CARTESIAN_POINT('',(7.71223265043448,4.,-4.87484654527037));
#1214=CARTESIAN_POINT('',(7.25909749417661,4.,-4.76932123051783));
#1215=CARTESIAN_POINT('',(6.35158630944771,4.,-4.56374155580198));
#1216=CARTESIAN_POINT('',(5.89721030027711,4.,-4.46368711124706));
#1217=CARTESIAN_POINT('',(4.99312971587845,4.,-4.27360636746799));
#1218=CARTESIAN_POINT('',(4.54345145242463,4.,-4.18345695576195));
#1219=CARTESIAN_POINT('',(3.6414017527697,4.,-4.01679463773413));
#1220=CARTESIAN_POINT('',(3.18902964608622,4.,-3.94028528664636));
#1221=CARTESIAN_POINT('',(2.2824594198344,4.,-3.80999477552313));
#1222=CARTESIAN_POINT('',(1.8282738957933,4.,-3.7561320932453));
#1223=CARTESIAN_POINT('',(1.14508719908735,4.,-3.70045408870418));
#1224=CARTESIAN_POINT('',(0.917113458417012,4.,-3.6860813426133));
#1225=CARTESIAN_POINT('',(0.460779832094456,4.,-3.66674621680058));
#1226=CARTESIAN_POINT('',(0.232420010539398,4.,-3.66178240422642));
#1227=CARTESIAN_POINT('',(-0.087293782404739,4.,-3.66169428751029));
#1228=CARTESIAN_POINT('',(-0.178661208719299,4.,-3.66245380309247));
#1229=CARTESIAN_POINT('',(-0.361371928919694,4.,-3.66552286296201));
#1230=CARTESIAN_POINT('',(-0.452715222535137,4.,-3.66783242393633));
#1231=CARTESIAN_POINT('',(-0.726742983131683,4.,-3.67704936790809));
#1232=CARTESIAN_POINT('',(-0.909352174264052,4.,-3.68624499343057));
#1233=CARTESIAN_POINT('',(-1.45731312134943,4.,-3.72238704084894));
#1234=CARTESIAN_POINT('',(-1.82211350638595,4.,-3.75788611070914));
#1235=CARTESIAN_POINT('',(-2.3690973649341,4.,-3.82428437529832));
#1236=CARTESIAN_POINT('',(-2.55212878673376,4.,-3.84873461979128));
#1237=CARTESIAN_POINT('',(-2.91768436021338,4.,-3.90130458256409));
#1238=CARTESIAN_POINT('',(-3.10020847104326,4.,-3.92942458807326));
#1239=CARTESIAN_POINT('',(-3.46431090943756,4.,-3.98861924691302));
#1240=CARTESIAN_POINT('',(-3.64589045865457,4.,-4.01968648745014));
#1241=CARTESIAN_POINT('',(-4.00857134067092,4.,-4.08430622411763));
#1242=CARTESIAN_POINT('',(-4.1896727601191,4.,-4.11785823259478));
#1243=CARTESIAN_POINT('',(-4.37057976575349,4.,-4.15239525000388));
#1244=B_SPLINE_CURVE_WITH_KNOTS('',3,(#1200,#1201,#1202,#1203,#1204,#1205,#1206,#1207,#1208,
#1209,#1210,#1211,#1212,#1213,#1214,#1215,#1216,#1217,#1218,#1219,#1220,#1221,#1222,#1223,#1224,
#1225,#1226,#1227,#1228,#1229,#1230,#1231,#1232,#1233,#1234,#1235,#1236,#1237,#1238,#1239,#1240,
#1241,#1242,#1243),.UNSPECIFIED.,.F.,.F.,(4,2,2,2,2,2,2,2,2,2,2,2,2,2,2,2,2,2,2,2,2,4),(0.,
2.86704484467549,5.73597893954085,8.67729232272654,11.6166642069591,13.0095404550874,
14.4024283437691,15.7981873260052,17.1939247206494,18.5696699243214,19.9457731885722,
21.3168795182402,22.0019945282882,22.6870051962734,22.9611068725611,23.2352114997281,
23.7836401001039,24.8825476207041,25.4364993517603,25.9904944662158,26.5431313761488,
27.0956601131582),.UNSPECIFIED.);
#1245=EDGE_CURVE('E324',#1062,#814,#1244,.T.);
#1246=ORIENTED_EDGE('',*,*,#1245,.T.);
#1247=ORIENTED_EDGE('',*,*,#817,.T.);
#1248=CARTESIAN_POINT('',(-3.95402007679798,4.,-4.6727297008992));
#1249=CARTESIAN_POINT('',(-3.87640017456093,4.,-4.51580666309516));
#1250=CARTESIAN_POINT('',(-3.7978804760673,4.,-4.35932155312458));
#1251=CARTESIAN_POINT('',(-3.63863622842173,4.,-4.04742537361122));
#1252=CARTESIAN_POINT('',(-3.55791109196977,4.,-3.89201460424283));
#1253=CARTESIAN_POINT('',(-3.39300442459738,4.,-3.58087522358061));
#1254=CARTESIAN_POINT('',(-3.30879494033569,4.,-3.42516137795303));
#1255=CARTESIAN_POINT('',(-3.13722206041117,4.,-3.11550528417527));
#1256=CARTESIAN_POINT('',(-3.04985911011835,4.,-2.9615627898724));
#1257=CARTESIAN_POINT('',(-2.86487822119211,4.,-2.64500008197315));
#1258=CARTESIAN_POINT('',(-2.76697365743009,4.,-2.48254631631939));
#1259=CARTESIAN_POINT('',(-2.56554664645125,4.,-2.16117918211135));
#1260=CARTESIAN_POINT('',(-2.46202508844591,4.,-2.00226525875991));
#1261=CARTESIAN_POINT('',(-2.24812167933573,4.,-1.6900818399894));
#1262=CARTESIAN_POINT('',(-2.13777248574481,4.,-1.53679033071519));
#1263=CARTESIAN_POINT('',(-1.96498453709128,4.,-1.31253972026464));
#1264=CARTESIAN_POINT('',(-1.90620177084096,4.,-1.2387644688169));
#1265=CARTESIAN_POINT('',(-1.78577110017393,4.,-1.09359841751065));
#1266=CARTESIAN_POINT('',(-1.72412378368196,4.,-1.02220713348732));
#1267=CARTESIAN_POINT('',(-1.61052145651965,4.,-0.89690350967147));
#1268=CARTESIAN_POINT('',(-1.55919243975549,4.,-0.842425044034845));
#1269=CARTESIAN_POINT('',(-1.45407588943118,4.,-0.735842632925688));
#1270=CARTESIAN_POINT('',(-1.4002874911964,4.,-0.683739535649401));
#1271=CARTESIAN_POINT('',(-1.29016745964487,4.,-0.582774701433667));
#1272=CARTESIAN_POINT('',(-1.23384819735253,4.,-0.53389958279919));
#1273=CARTESIAN_POINT('',(-1.11810912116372,4.,-0.439997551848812));
#1274=CARTESIAN_POINT('',(-1.05869041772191,4.,-0.394969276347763));
#1275=CARTESIAN_POINT('',(-0.912113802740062,4.,-0.292936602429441));
#1276=CARTESIAN_POINT('',(-0.823293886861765,4.,-0.238256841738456));
#1277=CARTESIAN_POINT('',(-0.63847539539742,4.,-0.142743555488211));
#1278=CARTESIAN_POINT('',(-0.542492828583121,4.,-0.101880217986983));
#1279=CARTESIAN_POINT('',(-0.365756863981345,4.,-0.0458696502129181));
#1280=CARTESIAN_POINT('',(-0.286181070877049,4.,-0.0270776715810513));
#1281=CARTESIAN_POINT('',(-0.124968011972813,4.,-0.0032934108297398));
#1282=CARTESIAN_POINT('',(-0.0433321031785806,4.,0.00170772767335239));
#1283=CARTESIAN_POINT('',(0.119595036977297,4.,-0.00275332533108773));
#1284=CARTESIAN_POINT('',(0.20088594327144,4.,-0.0122270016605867));
#1285=CARTESIAN_POINT('',(0.360751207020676,4.,-0.0444133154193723));
#1286=CARTESIAN_POINT('',(0.439323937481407,4.,-0.0671337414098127));
#1287=CARTESIAN_POINT('',(0.626552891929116,4.,-0.136011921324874));
#1288=CARTESIAN_POINT('',(0.732992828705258,4.,-0.188103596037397));
#1289=CARTESIAN_POINT('',(0.936786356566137,4.,-0.307816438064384));
#1290=CARTESIAN_POINT('',(1.03410669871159,4.,-0.375491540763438));
#1291=CARTESIAN_POINT('',(1.24608785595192,4.,-0.540895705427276));
#1292=CARTESIAN_POINT('',(1.35823651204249,4.,-0.641787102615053));
#1293=CARTESIAN_POINT('',(1.57251337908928,4.,-0.853819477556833));
#1294=CARTESIAN_POINT('',(1.67462071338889,4.,-0.964980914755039));
#1295=CARTESIAN_POINT('',(1.87229782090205,4.,-1.19539292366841));
#1296=CARTESIAN_POINT('',(1.96776699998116,4.,-1.31472892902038));
#1297=CARTESIAN_POINT('',(2.10626229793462,4.,-1.49715293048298));
#1298=CARTESIAN_POINT('',(2.15162165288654,4.,-1.55850014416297));
#1299=CARTESIAN_POINT('',(2.2409625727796,4.,-1.68218822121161));
#1300=CARTESIAN_POINT('',(2.28494418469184,4.,-1.74452905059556));
#1301=CARTESIAN_POINT('',(2.42881087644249,4.,-1.95270397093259));
#1302=CARTESIAN_POINT('',(2.52603970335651,4.,-2.10037526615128));
#1303=CARTESIAN_POINT('',(2.71542878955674,4.,-2.39894567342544));
#1304=CARTESIAN_POINT('',(2.8075879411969,4.,-2.54984548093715));
#1305=CARTESIAN_POINT('',(2.9879085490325,4.,-2.85414644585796));
#1306=CARTESIAN_POINT('',(3.07606723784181,4.,-3.00754923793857));
#1307=CARTESIAN_POINT('',(3.24907567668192,4.,-3.31621372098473));
#1308=CARTESIAN_POINT('',(3.33392522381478,4.,-3.47147552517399));
#1309=CARTESIAN_POINT('',(3.58500735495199,4.,-3.94058437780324));
#1310=CARTESIAN_POINT('',(3.74712222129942,4.,-4.25663403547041));
#1311=CARTESIAN_POINT('',(4.06349973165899,4.,-4.89244192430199));
#1312=CARTESIAN_POINT('',(4.21776547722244,4.,-5.21219862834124));
#1313=CARTESIAN_POINT('',(4.50248810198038,4.,-5.81629142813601));
#1314=CARTESIAN_POINT('',(4.63359595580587,4.,-6.10032168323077));
#1315=CARTESIAN_POINT('',(4.89223369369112,4.,-6.67004326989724));
#1316=CARTESIAN_POINT('',(5.01976315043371,4.,-6.95573479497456));
#1317=CARTESIAN_POINT('',(5.27098286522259,4.,-7.52627080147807));
#1318=CARTESIAN_POINT('',(5.39469457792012,4.,-7.81110585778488));
#1319=CARTESIAN_POINT('',(5.63971237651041,4.,-8.38175114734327));
#1320=CARTESIAN_POINT('',(5.76101887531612,4.,-8.6675612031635));
#1321=CARTESIAN_POINT('',(5.88137200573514,4.,-8.95376720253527));
#1322=B_SPLINE_CURVE_WITH_KNOTS('',3,(#1248,#1249,#1250,#1251,#1252,#1253,#1254,#1255,#1256,
#1257,#1258,#1259,#1260,#1261,#1262,#1263,#1264,#1265,#1266,#1267,#1268,#1269,#1270,#1271,#1272,
#1273,#1274,#1275,#1276,#1277,#1278,#1279,#1280,#1281,#1282,#1283,#1284,#1285,#1286,#1287,#1288,
#1289,#1290,#1291,#1292,#1293,#1294,#1295,#1296,#1297,#1298,#1299,#1300,#1301,#1302,#1303,#1304,
#1305,#1306,#1307,#1308,#1309,#1310,#1311,#1312,#1313,#1314,#1315,#1316,#1317,#1318,#1319,#1320,
#1321),.UNSPECIFIED.,.F.,.F.,(4,2,2,2,2,2,2,2,2,2,2,2,2,2,2,2,2,2,2,2,2,2,2,2,2,2,2,2,2,2,2,2,2,
2,2,2,4),(0.,0.525218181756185,1.05057761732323,1.58162323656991,2.11259414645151,
2.68152598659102,3.25036802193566,3.81667291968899,4.09960865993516,4.38248658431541,
4.60697399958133,4.83154095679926,5.05510944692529,5.27859838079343,5.59064578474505,
5.90201551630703,6.14626082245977,6.39034923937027,6.63463142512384,6.87905738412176,
7.23252268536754,7.58723024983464,8.03870278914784,8.49109496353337,8.94928685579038,
9.17815941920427,9.40702417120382,9.93728661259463,10.4676644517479,10.9984037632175,
11.5291755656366,12.5946055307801,13.6596111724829,14.5980694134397,15.5366392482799,
16.4682501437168,17.3996996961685),.UNSPECIFIED.);
#1323=CARTESIAN_POINT('',(0.,4.,0.));
#1324=VERTEX_POINT('',#1323);
#1325=EDGE_CURVE('E222',#1324,#816,#1322,.F.);
#1326=ORIENTED_EDGE('',*,*,#1325,.F.);
#1327=EDGE_CURVE('E204',#1064,#1324,#1322,.F.);
#1328=ORIENTED_EDGE('',*,*,#1327,.F.);
#1329=EDGE_LOOP('',(#1066,#1246,#1247,#1326,#1328));
#1330=FACE_BOUND('',#1329,.T.);
#1331=ADVANCED_FACE('F225',(#1330),#1056,.T.);
#1332=CARTESIAN_POINT('',(4.61880215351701,0.,-5.3));
#1333=DIRECTION('',(0.866025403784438,0.5,0.));
#1334=DIRECTION('',(-0.500000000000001,0.866025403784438,0.));
#1335=AXIS2_PLACEMENT_3D('',#1332,#1333,#1334);
#1336=PLANE('',#1335);
#1337=ORIENTED_EDGE('',*,*,#222,.F.);
#1338=CARTESIAN_POINT('',(14.5394344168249,-17.1830391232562,-8.55558985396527));
#1339=CARTESIAN_POINT('',(14.5031144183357,-17.1201310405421,-8.83174684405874));
#1340=CARTESIAN_POINT('',(14.7483162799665,-16.9744266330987,-8.84536760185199));
#1341=CARTESIAN_POINT('',(14.0765515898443,-16.3813025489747,-8.31214514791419));
#1342=CARTESIAN_POINT('',(14.0406605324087,-16.3191374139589,-8.58793733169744));
#1343=CARTESIAN_POINT('',(14.2849712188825,-16.1730960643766,-8.60192289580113));
#1344=CARTESIAN_POINT('',(13.6136152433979,-15.5794732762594,-8.06910132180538));
#1345=CARTESIAN_POINT('',(13.5780832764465,-15.5179301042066,-8.34442822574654));
#1346=CARTESIAN_POINT('',(13.8215293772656,-15.3717118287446,-8.35887906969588));
#1347=CARTESIAN_POINT('',(12.6872328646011,-13.9749319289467,-7.58440903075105));
#1348=CARTESIAN_POINT('',(12.6521068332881,-13.9140918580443,-7.85844689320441));
#1349=CARTESIAN_POINT('',(12.8939913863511,-13.7682273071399,-7.874186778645));
#1350=CARTESIAN_POINT('',(12.2237866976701,-13.1722196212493,-7.3427615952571));
#1351=CARTESIAN_POINT('',(12.1890072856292,-13.111979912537,-7.61612935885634));
#1352=CARTESIAN_POINT('',(12.4298950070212,-12.966126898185,-7.63253934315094));
#1353=CARTESIAN_POINT('',(11.2848698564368,-11.545967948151,-6.8556977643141));
#1354=CARTESIAN_POINT('',(11.2505929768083,-11.4865986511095,-7.12731783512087));
#1355=CARTESIAN_POINT('',(11.4894564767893,-11.3413728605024,-7.14547551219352));
#1356=CARTESIAN_POINT('',(10.8093914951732,-10.7224152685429,-6.61034060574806));
#1357=CARTESIAN_POINT('',(10.7756871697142,-10.6640376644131,-6.88108543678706));
#1358=CARTESIAN_POINT('',(11.0131014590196,-10.5187124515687,-6.90011835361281));
#1359=CARTESIAN_POINT('',(9.85822885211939,-9.07495324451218,-6.12383947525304));
#1360=CARTESIAN_POINT('',(9.82529712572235,-9.01791382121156,-6.39216776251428));
#1361=CARTESIAN_POINT('',(10.0598640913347,-8.87350005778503,-6.41361722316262));
#1362=CARTESIAN_POINT('',(9.38254491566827,-8.25104449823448,-5.88269281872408));
#1363=CARTESIAN_POINT('',(9.35055396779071,-8.19563455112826,-6.149843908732));
#1364=CARTESIAN_POINT('',(9.582982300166,-8.05094836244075,-6.17247056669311));
#1365=CARTESIAN_POINT('',(8.68076096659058,-7.03551904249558,-5.53294307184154));
#1366=CARTESIAN_POINT('',(8.64841830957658,-6.97949991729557,-5.79690487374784));
#1367=CARTESIAN_POINT('',(8.87907047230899,-6.83810638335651,-5.82272081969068));
#1368=CARTESIAN_POINT('',(8.45503264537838,-6.64454612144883,-5.42136208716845));
#1369=CARTESIAN_POINT('',(8.42309728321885,-6.58923245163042,-5.6844641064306));
#1370=CARTESIAN_POINT('',(8.65260283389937,-6.44810029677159,-5.71113983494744));
#1371=CARTESIAN_POINT('',(8.0032705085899,-5.86207114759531,-5.20067849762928));
#1372=CARTESIAN_POINT('',(7.97209417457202,-5.8080721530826,-5.46179745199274));
#1373=CARTESIAN_POINT('',(8.19922969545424,-5.66786499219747,-5.49045624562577));
#1374=CARTESIAN_POINT('',(7.7772366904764,-5.47056909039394,-5.09157591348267));
#1375=CARTESIAN_POINT('',(7.7465898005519,-5.41748711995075,-5.35165029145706));
#1376=CARTESIAN_POINT('',(7.97232419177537,-5.27763577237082,-5.38135366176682));
#1377=CARTESIAN_POINT('',(7.32427254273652,-4.68601217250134,-4.87674409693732));
#1378=CARTESIAN_POINT('',(7.29464827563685,-4.63470143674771,-5.1344034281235));
#1379=CARTESIAN_POINT('',(7.51746746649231,-4.49607741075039,-5.16652184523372));
#1380=CARTESIAN_POINT('',(7.09734132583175,-4.29295577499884,-4.77102231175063));
#1381=CARTESIAN_POINT('',(7.0684397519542,-4.24289678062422,-5.02740455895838));
#1382=CARTESIAN_POINT('',(7.2895150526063,-4.10474766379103,-5.06080005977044));
#1383=CARTESIAN_POINT('',(6.64285764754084,-3.50576695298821,-4.56505534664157));
#1384=CARTESIAN_POINT('',(6.61538261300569,-3.45817879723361,-4.81848453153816));
#1385=CARTESIAN_POINT('',(6.83285336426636,-3.32169726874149,-4.85483309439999));
#1386=CARTESIAN_POINT('',(6.41530519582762,-3.11163454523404,-4.46481008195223));
#1387=CARTESIAN_POINT('',(6.38883006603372,-3.06577827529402,-4.71666888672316));
#1388=CARTESIAN_POINT('',(6.60414410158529,-2.9299766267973,-4.75458782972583));
#1389=CARTESIAN_POINT('',(5.96254818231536,-2.32743639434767,-4.27436791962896));
#1390=CARTESIAN_POINT('',(5.9380857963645,-2.28506629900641,-4.52267428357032));
#1391=CARTESIAN_POINT('',(6.14906336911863,-2.15161259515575,-4.5641456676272));
#1392=CARTESIAN_POINT('',(5.73735683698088,-1.93739354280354,-4.184047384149));
#1393=CARTESIAN_POINT('',(5.71426252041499,-1.89739301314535,-4.43047216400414));
#1394=CARTESIAN_POINT('',(5.92270549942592,-1.76497708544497,-4.47382513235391));
#1395=CARTESIAN_POINT('',(5.28562396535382,-1.15496925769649,-4.01707291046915));
#1396=CARTESIAN_POINT('',(5.26548525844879,-1.12008799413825,-4.25943247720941));
#1397=CARTESIAN_POINT('',(5.46895307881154,-0.99087121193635,-4.30685065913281));
#1398=CARTESIAN_POINT('',(5.05908210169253,-0.7625872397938,-3.94042254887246));
#1399=CARTESIAN_POINT('',(5.04081547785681,-0.73094851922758,-4.18059335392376));
#1400=CARTESIAN_POINT('',(5.24155827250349,-0.603400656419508,-4.23020029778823));
#1401=CARTESIAN_POINT('',(4.60508396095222,0.0237606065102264,-3.80992031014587));
#1402=CARTESIAN_POINT('',(4.59106603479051,0.0480403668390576,-4.04600903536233));
#1403=CARTESIAN_POINT('',(4.78707554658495,0.171259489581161,-4.09969805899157));
#1404=CARTESIAN_POINT('',(4.37763402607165,0.417715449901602,-3.75598635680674));
#1405=CARTESIAN_POINT('',(4.36591203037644,0.438018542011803,-3.98996132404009));
#1406=CARTESIAN_POINT('',(4.5599895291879,0.558444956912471,-4.04576410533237));
#1407=CARTESIAN_POINT('',(4.03550287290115,1.01030399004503,-3.70029165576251));
#1408=CARTESIAN_POINT('',(4.02768682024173,1.02384179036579,-3.93207627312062));
#1409=CARTESIAN_POINT('',(4.22024886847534,1.14009389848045,-3.99006940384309));
#1410=CARTESIAN_POINT('',(3.92133660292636,1.208045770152,-3.68592836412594));
#1411=CARTESIAN_POINT('',(3.91497211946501,1.21906937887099,-3.91711556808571));
#1412=CARTESIAN_POINT('',(4.10718621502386,1.33405956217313,-3.97570611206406));
#1413=CARTESIAN_POINT('',(3.69281117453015,1.60386342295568,-3.66664521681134));
#1414=CARTESIAN_POINT('',(3.68962349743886,1.60938464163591,-3.89705602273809));
#1415=CARTESIAN_POINT('',(3.88153811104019,1.72235904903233,-3.95642296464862));
#1416=CARTESIAN_POINT('',(3.57845204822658,1.80193924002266,-3.66172391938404));
#1417=CARTESIAN_POINT('',(3.57681077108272,1.80478201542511,-3.89192321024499));
#1418=CARTESIAN_POINT('',(3.76895259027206,1.91669281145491,-3.95150166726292));
#1419=CARTESIAN_POINT('',(3.41841730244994,2.07912755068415,-3.66171696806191));
#1420=CARTESIAN_POINT('',(3.41907307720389,2.07799171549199,-3.89191458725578));
#1421=CARTESIAN_POINT('',(3.61180632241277,2.18887586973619,-3.95149471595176));
#1422=CARTESIAN_POINT('',(3.37273437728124,2.15825269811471,-3.6624996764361));
#1423=CARTESIAN_POINT('',(3.37403878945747,2.15599338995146,-3.89273007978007));
#1424=CARTESIAN_POINT('',(3.56699429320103,2.26659862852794,-3.95227742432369));
#1425=CARTESIAN_POINT('',(3.28138077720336,2.31648177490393,-3.66561475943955));
#1426=CARTESIAN_POINT('',(3.2839892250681,2.3119638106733,-3.8959727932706));
#1427=CARTESIAN_POINT('',(3.47746138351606,2.4220924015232,-3.95539250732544));
#1428=CARTESIAN_POINT('',(3.23571010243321,2.39558570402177,-3.66794715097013));
#1429=CARTESIAN_POINT('',(3.23896165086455,2.38995385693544,-3.8984009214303));
#1430=CARTESIAN_POINT('',(3.43274050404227,2.49986341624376,-3.95772489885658));
#1431=CARTESIAN_POINT('',(3.09869925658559,2.63289545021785,-3.67723166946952));
#1432=CARTESIAN_POINT('',(3.10384109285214,2.62398952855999,-3.90806527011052));
#1433=CARTESIAN_POINT('',(3.29867820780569,2.73329813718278,-3.96700941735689));
#1434=CARTESIAN_POINT('',(3.00739699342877,2.79103560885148,-3.68647110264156));
#1435=CARTESIAN_POINT('',(3.01374944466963,2.78003284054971,-3.91768701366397));
#1436=CARTESIAN_POINT('',(3.20947317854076,2.88902107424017,-3.97624885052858));
#1437=CARTESIAN_POINT('',(2.73342367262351,3.26557132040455,-3.72273800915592));
#1438=CARTESIAN_POINT('',(2.74316707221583,3.24869525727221,-3.95540495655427));
#1439=CARTESIAN_POINT('',(2.94198280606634,3.35691346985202,-4.01251575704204));
#1440=CARTESIAN_POINT('',(2.55102910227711,3.58148798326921,-3.75831137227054));
#1441=CARTESIAN_POINT('',(2.56280649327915,3.56108894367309,-3.99241678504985));
#1442=CARTESIAN_POINT('',(2.76415802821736,3.66922375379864,-4.04808912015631));
#1443=CARTESIAN_POINT('',(2.27754571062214,4.05517511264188,-3.82480471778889));
#1444=CARTESIAN_POINT('',(2.29270504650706,4.0289183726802,-4.06107376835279));
#1445=CARTESIAN_POINT('',(2.49725630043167,4.13863043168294,-4.11458246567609));
#1446=CARTESIAN_POINT('',(2.18603289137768,4.21367996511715,-3.8492840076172));
#1447=CARTESIAN_POINT('',(2.20212308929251,4.18581092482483,-4.0863647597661));
#1448=CARTESIAN_POINT('',(2.40790002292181,4.29589395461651,-4.13906175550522));
#1449=CARTESIAN_POINT('',(2.0032607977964,4.53025051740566,-3.9019070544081));
#1450=CARTESIAN_POINT('',(2.02109756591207,4.49935632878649,-4.14062943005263));
#1451=CARTESIAN_POINT('',(2.22929208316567,4.61029719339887,-4.19168480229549));
#1452=CARTESIAN_POINT('',(1.91200154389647,4.68831618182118,-3.93005109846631));
#1453=CARTESIAN_POINT('',(1.93064579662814,4.65602338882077,-4.16961875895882));
#1454=CARTESIAN_POINT('',(2.1400404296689,4.76743689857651,-4.21982884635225));
#1455=CARTESIAN_POINT('',(1.72995630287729,5.00362778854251,-3.9892892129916));
#1456=CARTESIAN_POINT('',(1.75010367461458,4.96873151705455,-4.23053091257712));
#1457=CARTESIAN_POINT('',(1.96182642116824,5.08115229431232,-4.2790669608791));
#1458=CARTESIAN_POINT('',(1.63916970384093,5.16087479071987,-4.0203758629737));
#1459=CARTESIAN_POINT('',(1.66001808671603,5.12476433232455,-4.26245525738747));
#1460=CARTESIAN_POINT('',(1.87286389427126,5.23772842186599,-4.31015361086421));
#1461=CARTESIAN_POINT('',(1.45783539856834,5.4749550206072,-4.0850307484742));
#1462=CARTESIAN_POINT('',(1.47996899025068,5.43661851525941,-4.32876154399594));
#1463=CARTESIAN_POINT('',(1.69499683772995,5.55066351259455,-4.37480849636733));
#1464=CARTESIAN_POINT('',(1.36728764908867,5.63178832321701,-4.11859849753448));
#1465=CARTESIAN_POINT('',(1.39001886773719,5.59241669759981,-4.36314658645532));
#1466=CARTESIAN_POINT('',(1.6060923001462,5.70702251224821,-4.40837624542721));
#1467=CARTESIAN_POINT('',(1.2768369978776,5.78845344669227,-4.1531497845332));
#1468=CARTESIAN_POINT('',(1.30027186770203,5.74786306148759,-4.3984261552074));
#1469=CARTESIAN_POINT('',(1.51719352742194,5.86328355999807,-4.44292753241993));
#1470=(BOUNDED_SURFACE() B_SPLINE_SURFACE(3,2,((#1338,#1339,#1340),(#1341,#1342,#1343),(#1344,
#1345,#1346),(#1347,#1348,#1349),(#1350,#1351,#1352),(#1353,#1354,#1355),(#1356,#1357,#1358),
(#1359,#1360,#1361),(#1362,#1363,#1364),(#1365,#1366,#1367),(#1368,#1369,#1370),(#1371,#1372,
#1373),(#1374,#1375,#1376),(#1377,#1378,#1379),(#1380,#1381,#1382),(#1383,#1384,#1385),(#1386,
#1387,#1388),(#1389,#1390,#1391),(#1392,#1393,#1394),(#1395,#1396,#1397),(#1398,#1399,#1400),
(#1401,#1402,#1403),(#1404,#1405,#1406),(#1407,#1408,#1409),(#1410,#1411,#1412),(#1413,#1414,
#1415),(#1416,#1417,#1418),(#1419,#1420,#1421),(#1422,#1423,#1424),(#1425,#1426,#1427),(#1428,
#1429,#1430),(#1431,#1432,#1433),(#1434,#1435,#1436),(#1437,#1438,#1439),(#1440,#1441,#1442),
(#1443,#1444,#1445),(#1446,#1447,#1448),(#1449,#1450,#1451),(#1452,#1453,#1454),(#1455,#1456,
#1457),(#1458,#1459,#1460),(#1461,#1462,#1463),(#1464,#1465,#1466),(#1467,#1468,#1469)),
.UNSPECIFIED.,.F.,.F.,.F.) B_SPLINE_SURFACE_WITH_KNOTS((4,2,2,2,2,2,2,2,2,2,2,2,2,2,2,2,2,2,2,2,
2,4),(3,3),(0.,2.87172082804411,5.74534141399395,8.69163587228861,11.6359776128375,
13.0310968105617,14.4262276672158,15.8242453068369,17.222241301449,18.600159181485,
19.978437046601,21.3516914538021,22.0378780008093,22.7239597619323,22.9980573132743,
23.272157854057,23.8205791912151,24.9194760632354,25.4734222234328,26.0274118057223,
26.5800398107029,27.1325597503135),(0.,1.),
.UNSPECIFIED.) GEOMETRIC_REPRESENTATION_ITEM() RATIONAL_B_SPLINE_SURFACE(((1.,0.724335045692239,
1.),(1.,0.72502874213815,1.),(1.,0.725787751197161,1.),(1.,0.72754165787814,1.),(1.,
0.728536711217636,1.),(1.,0.730896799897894,1.),(1.,0.732270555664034,1.),(1.,0.735588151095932,
1.),(1.,0.737531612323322,1.),(1.,0.741117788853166,1.),(1.,0.742380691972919,1.),(1.,
0.745198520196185,1.),(1.,0.74675344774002,1.),(1.,0.750247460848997,1.),(1.,0.752187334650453,
1.),(1.,0.756556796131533,1.),(1.,0.758986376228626,1.),(1.,0.764379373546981,1.),(1.,
0.767334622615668,1.),(1.,0.773723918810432,1.),(1.,0.777158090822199,1.),(1.,0.783844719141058,
1.),(1.,0.787097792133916,1.),(1.,0.790686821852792,1.),(1.,0.791667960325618,1.),(1.,
0.793000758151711,1.),(1.,0.793352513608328,1.),(1.,0.793353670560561,1.),(1.,0.793297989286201,
1.),(1.,0.793078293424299,1.),(1.,0.792914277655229,1.),(1.,0.792266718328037,1.),(1.,
0.791627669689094,1.),(1.,0.789211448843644,1.),(1.,0.786935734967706,1.),(1.,0.783154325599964,
1.),(1.,0.78182642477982,1.),(1.,0.779132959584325,1.),(1.,0.777767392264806,1.),(1.,
0.77506282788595,1.),(1.,0.773723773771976,1.),(1.,0.771102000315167,1.),(1.,0.769819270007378,
1.),(1.,0.768581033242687,1.))) REPRESENTATION_ITEM('') SURFACE());
#1471=CARTESIAN_POINT('',(14.5394344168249,-17.1830391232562,-8.55558985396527));
#1472=CARTESIAN_POINT('',(14.0765515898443,-16.3813025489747,-8.31214514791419));
#1473=CARTESIAN_POINT('',(13.6136152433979,-15.5794732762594,-8.06910132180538));
#1474=CARTESIAN_POINT('',(12.6872328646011,-13.9749319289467,-7.58440903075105));
#1475=CARTESIAN_POINT('',(12.2237866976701,-13.1722196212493,-7.3427615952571));
#1476=CARTESIAN_POINT('',(11.2848698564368,-11.545967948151,-6.8556977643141));
#1477=CARTESIAN_POINT('',(10.8093914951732,-10.7224152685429,-6.61034060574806));
#1478=CARTESIAN_POINT('',(9.85822885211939,-9.07495324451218,-6.12383947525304));
#1479=CARTESIAN_POINT('',(9.38254491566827,-8.25104449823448,-5.88269281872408));
#1480=CARTESIAN_POINT('',(8.68076096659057,-7.03551904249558,-5.53294307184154));
#1481=CARTESIAN_POINT('',(8.45503264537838,-6.64454612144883,-5.42136208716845));
#1482=CARTESIAN_POINT('',(8.0032705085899,-5.86207114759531,-5.20067849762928));
#1483=CARTESIAN_POINT('',(7.7772366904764,-5.47056909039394,-5.09157591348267));
#1484=CARTESIAN_POINT('',(7.32427254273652,-4.68601217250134,-4.87674409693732));
#1485=CARTESIAN_POINT('',(7.09734132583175,-4.29295577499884,-4.77102231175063));
#1486=CARTESIAN_POINT('',(6.64285764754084,-3.50576695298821,-4.56505534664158));
#1487=CARTESIAN_POINT('',(6.41530519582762,-3.11163454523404,-4.46481008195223));
#1488=CARTESIAN_POINT('',(5.96254818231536,-2.32743639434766,-4.27436791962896));
#1489=CARTESIAN_POINT('',(5.73735683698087,-1.93739354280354,-4.184047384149));
#1490=CARTESIAN_POINT('',(5.28562396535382,-1.15496925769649,-4.01707291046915));
#1491=CARTESIAN_POINT('',(5.05908210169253,-0.7625872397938,-3.94042254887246));
#1492=CARTESIAN_POINT('',(4.60508396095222,0.0237606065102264,-3.80992031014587));
#1493=CARTESIAN_POINT('',(4.37763402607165,0.417715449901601,-3.75598635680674));
#1494=CARTESIAN_POINT('',(4.03550287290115,1.01030399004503,-3.70029165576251));
#1495=CARTESIAN_POINT('',(3.92133660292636,1.208045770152,-3.68592836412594));
#1496=CARTESIAN_POINT('',(3.69281117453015,1.60386342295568,-3.66664521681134));
#1497=CARTESIAN_POINT('',(3.57845204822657,1.80193924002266,-3.66172391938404));
#1498=CARTESIAN_POINT('',(3.41841730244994,2.07912755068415,-3.66171696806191));
#1499=CARTESIAN_POINT('',(3.37273437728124,2.15825269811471,-3.6624996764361));
#1500=CARTESIAN_POINT('',(3.28138077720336,2.31648177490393,-3.66561475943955));
#1501=CARTESIAN_POINT('',(3.23571010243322,2.39558570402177,-3.66794715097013));
#1502=CARTESIAN_POINT('',(3.09869925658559,2.63289545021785,-3.67723166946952));
#1503=CARTESIAN_POINT('',(3.00739699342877,2.79103560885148,-3.68647110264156));
#1504=CARTESIAN_POINT('',(2.73342367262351,3.26557132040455,-3.72273800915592));
#1505=CARTESIAN_POINT('',(2.55102910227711,3.58148798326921,-3.75831137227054));
#1506=CARTESIAN_POINT('',(2.27754571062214,4.05517511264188,-3.82480471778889));
#1507=CARTESIAN_POINT('',(2.18603289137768,4.21367996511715,-3.8492840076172));
#1508=CARTESIAN_POINT('',(2.0032607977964,4.53025051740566,-3.90190705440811));
#1509=CARTESIAN_POINT('',(1.91200154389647,4.68831618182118,-3.93005109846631));
#1510=CARTESIAN_POINT('',(1.72995630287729,5.00362778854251,-3.9892892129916));
#1511=CARTESIAN_POINT('',(1.63916970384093,5.16087479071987,-4.0203758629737));
#1512=CARTESIAN_POINT('',(1.45783539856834,5.4749550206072,-4.0850307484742));
#1513=CARTESIAN_POINT('',(1.36728764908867,5.63178832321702,-4.11859849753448));
#1514=CARTESIAN_POINT('',(1.2768369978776,5.78845344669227,-4.1531497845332));
#1515=B_SPLINE_CURVE_WITH_KNOTS('',3,(#1471,#1472,#1473,#1474,#1475,#1476,#1477,#1478,#1479,
#1480,#1481,#1482,#1483,#1484,#1485,#1486,#1487,#1488,#1489,#1490,#1491,#1492,#1493,#1494,#1495,
#1496,#1497,#1498,#1499,#1500,#1501,#1502,#1503,#1504,#1505,#1506,#1507,#1508,#1509,#1510,#1511,
#1512,#1513,#1514),.UNSPECIFIED.,.F.,.F.,(4,2,2,2,2,2,2,2,2,2,2,2,2,2,2,2,2,2,2,2,2,4),(0.,
2.87172082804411,5.74534141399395,8.69163587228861,11.6359776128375,13.0310968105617,
14.4262276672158,15.8242453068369,17.222241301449,18.600159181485,19.978437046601,
21.3516914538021,22.0378780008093,22.7239597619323,22.9980573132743,23.272157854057,
23.8205791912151,24.9194760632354,25.4734222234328,26.0274118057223,26.5800398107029,
27.1325597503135),.UNSPECIFIED.);
#1516=EDGE_CURVE('E325',#213,#1062,#1515,.T.);
#1517=ORIENTED_EDGE('',*,*,#1516,.T.);
#1518=ORIENTED_EDGE('',*,*,#1065,.T.);
#1519=CARTESIAN_POINT('',(4.61887168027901,-0.000120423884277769,-1.7802));
#1520=CARTESIAN_POINT('',(4.59853045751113,0.0351116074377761,-1.72169220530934));
#1521=CARTESIAN_POINT('',(4.57792135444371,0.0708076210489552,-1.66355827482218));
#1522=CARTESIAN_POINT('',(4.53609096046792,0.143259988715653,-1.54815677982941));
#1523=CARTESIAN_POINT('',(4.51486951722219,0.180016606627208,-1.49088943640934));
#1524=CARTESIAN_POINT('',(4.4498976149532,0.29255124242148,-1.31984609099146));
#1525=CARTESIAN_POINT('',(4.40511113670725,0.370123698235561,-1.20761921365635));
#1526=CARTESIAN_POINT('',(4.31001453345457,0.534835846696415,-0.984245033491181));
#1527=CARTESIAN_POINT('',(4.25954819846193,0.622246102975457,-0.873361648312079));
#1528=CARTESIAN_POINT('',(4.1537807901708,0.805440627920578,-0.661563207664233));
#1529=CARTESIAN_POINT('',(4.09849522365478,0.901198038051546,-0.560618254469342));
#1530=CARTESIAN_POINT('',(4.01755039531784,1.04139859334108,-0.431782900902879));
#1531=CARTESIAN_POINT('',(3.99458074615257,1.08118319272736,-0.397143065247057));
#1532=CARTESIAN_POINT('',(3.94761959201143,1.16252229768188,-0.330748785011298));
#1533=CARTESIAN_POINT('',(3.92362782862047,1.20407725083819,-0.298995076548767));
#1534=CARTESIAN_POINT('',(3.8503798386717,1.33094649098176,-0.209445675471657));
#1535=CARTESIAN_POINT('',(3.79947216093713,1.41912117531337,-0.156734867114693));
#1536=CARTESIAN_POINT('',(3.70753434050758,1.5783621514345,-0.082796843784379));
#1537=CARTESIAN_POINT('',(3.66744840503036,1.64779302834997,-0.0569308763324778));
#1538=CARTESIAN_POINT('',(3.58565651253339,1.78946074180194,-0.0188566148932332));
#1539=CARTESIAN_POINT('',(3.54395176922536,1.86169547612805,-0.00663828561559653));
#1540=CARTESIAN_POINT('',(3.45994159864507,2.00720535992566,0.00251875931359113));
#1541=CARTESIAN_POINT('',(3.41763443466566,2.08048351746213,-0.000603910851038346));
#1542=CARTESIAN_POINT('',(3.33396818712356,2.22539770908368,-0.021813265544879));
#1543=CARTESIAN_POINT('',(3.2926100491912,2.29703210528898,-0.0399142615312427));
#1544=CARTESIAN_POINT('',(3.20045135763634,2.45665564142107,-0.0957585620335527));
#1545=CARTESIAN_POINT('',(3.15028584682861,2.5435448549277,-0.137607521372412));
#1546=CARTESIAN_POINT('',(3.05381880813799,2.71063066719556,-0.236407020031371));
#1547=CARTESIAN_POINT('',(3.0075286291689,2.79080760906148,-0.29340000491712));
#1548=CARTESIAN_POINT('',(2.92091463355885,2.94082745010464,-0.414494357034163));
#1549=CARTESIAN_POINT('',(2.88040651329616,3.01098957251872,-0.478080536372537));
#1550=CARTESIAN_POINT('',(2.80218899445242,3.14646628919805,-0.61186733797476));
#1551=CARTESIAN_POINT('',(2.76448256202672,3.21177574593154,-0.682074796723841));
#1552=CARTESIAN_POINT('',(2.6913296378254,3.33848032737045,-0.827445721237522));
#1553=CARTESIAN_POINT('',(2.65589061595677,3.39986251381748,-0.90262406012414));
#1554=CARTESIAN_POINT('',(2.58701514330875,3.51915833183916,-1.05648002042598));
#1555=CARTESIAN_POINT('',(2.55357783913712,3.57707344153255,-1.1351561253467));
#1556=CARTESIAN_POINT('',(2.48363251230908,3.69822230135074,-1.30677603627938));
#1557=CARTESIAN_POINT('',(2.44738132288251,3.76101120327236,-1.40013569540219));
#1558=CARTESIAN_POINT('',(2.37697159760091,3.88296442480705,-1.58876843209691));
#1559=CARTESIAN_POINT('',(2.3427982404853,3.94215441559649,-1.68401931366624));
#1560=CARTESIAN_POINT('',(2.30933154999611,4.00012042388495,-1.78020000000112));
#1561=B_SPLINE_CURVE_WITH_KNOTS('',3,(#1519,#1520,#1521,#1522,#1523,#1524,#1525,#1526,#1527,
#1528,#1529,#1530,#1531,#1532,#1533,#1534,#1535,#1536,#1537,#1538,#1539,#1540,#1541,#1542,#1543,
#1544,#1545,#1546,#1547,#1548,#1549,#1550,#1551,#1552,#1553,#1554,#1555,#1556,#1557,#1558,#1559,
#1560),.UNSPECIFIED.,.F.,.F.,(4,2,2,2,2,2,2,2,2,2,2,2,2,2,2,2,2,2,2,2,4),(0.,0.21377756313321,
0.42760877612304,0.858145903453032,1.30759304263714,1.75564391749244,1.92815043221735,
2.10070082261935,2.44287249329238,2.69463411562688,2.94621049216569,3.19879434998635,
3.45161982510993,3.77590275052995,4.10110434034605,4.40960953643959,4.71843682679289,
5.02823407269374,5.33789828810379,5.69242023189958,6.04401162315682),.UNSPECIFIED.);
#1562=CARTESIAN_POINT('',(3.46410161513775,2.,0.));
#1563=VERTEX_POINT('',#1562);
#1564=EDGE_CURVE('E194',#1563,#1064,#1561,.T.);
#1565=ORIENTED_EDGE('',*,*,#1564,.F.);
#1566=EDGE_CURVE('E443',#221,#1563,#1561,.T.);
#1567=ORIENTED_EDGE('',*,*,#1566,.F.);
#1568=EDGE_LOOP('',(#1337,#1517,#1518,#1565,#1567));
#1569=FACE_BOUND('',#1568,.T.);
#1570=ADVANCED_FACE('F359',(#1569),#1336,.T.);
#1571=CARTESIAN_POINT('',(4.61880215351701,0.,-5.3));
#1572=DIRECTION('',(0.,0.,1.));
#1573=DIRECTION('',(1.,0.,0.));
#1574=AXIS2_PLACEMENT_3D('',#1571,#1572,#1573);
#1575=PLANE('',#1574);
#1576=CARTESIAN_POINT('',(0.,0.,-5.3));
#1577=DIRECTION('',(0.,0.,1.));
#1578=DIRECTION('',(1.,0.,0.));
#1579=AXIS2_PLACEMENT_3D('',#1576,#1577,#1578);
#1580=CIRCLE('',#1579,2.18571428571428);
#1581=CARTESIAN_POINT('',(-2.18571428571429,0.,-5.3));
#1582=VERTEX_POINT('',#1581);
#1583=EDGE_CURVE('E535',#1582,#1582,#1580,.T.);
#1584=ORIENTED_EDGE('',*,*,#1583,.T.);
#1585=EDGE_LOOP('',(#1584));
#1586=FACE_BOUND('',#1585,.T.);
#1587=CARTESIAN_POINT('',(0.,0.,-5.3));
#1588=DIRECTION('',(0.,0.,-1.));
#1589=DIRECTION('',(-1.,0.,0.));
#1590=AXIS2_PLACEMENT_3D('',#1587,#1588,#1589);
#1591=CIRCLE('',#1590,5.3913338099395);
#1592=CARTESIAN_POINT('',(-5.3913338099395,0.,-5.3));
#1593=VERTEX_POINT('',#1592);
#1594=EDGE_CURVE('E502',#1593,#1593,#1591,.T.);
#1595=ORIENTED_EDGE('',*,*,#1594,.T.);
#1596=EDGE_LOOP('',(#1595));
#1597=FACE_BOUND('',#1596,.T.);
#1598=ADVANCED_FACE('F189',(#1586,#1597),#1575,.F.);
#1599=CARTESIAN_POINT('',(0.,0.,0.));
#1600=DIRECTION('',(0.,0.,-1.));
#1601=DIRECTION('',(-1.,0.,0.));
#1602=AXIS2_PLACEMENT_3D('',#1599,#1600,#1601);
#1603=CONICAL_SURFACE('',#1602,4.,0.334572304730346);
#1604=ORIENTED_EDGE('',*,*,#269,.T.);
#1605=ORIENTED_EDGE('',*,*,#1566,.T.);
#1606=CARTESIAN_POINT('',(0.,0.,0.));
#1607=DIRECTION('',(0.,0.,1.));
#1608=DIRECTION('',(1.,0.,0.));
#1609=AXIS2_PLACEMENT_3D('',#1606,#1607,#1608);
#1610=CIRCLE('',#1609,4.);
#1611=EDGE_CURVE('E529',#1563,#268,#1610,.F.);
#1612=ORIENTED_EDGE('',*,*,#1611,.T.);
#1613=EDGE_LOOP('',(#1604,#1605,#1612));
#1614=FACE_BOUND('',#1613,.T.);
#1615=ADVANCED_FACE('F185',(#1614),#1603,.T.);
#1616=ORIENTED_EDGE('',*,*,#1327,.T.);
#1617=EDGE_CURVE('E531',#1324,#1563,#1610,.F.);
#1618=ORIENTED_EDGE('',*,*,#1617,.T.);
#1619=ORIENTED_EDGE('',*,*,#1564,.T.);
#1620=EDGE_LOOP('',(#1616,#1618,#1619));
#1621=FACE_BOUND('',#1620,.T.);
#1622=ADVANCED_FACE('F179',(#1621),#1603,.T.);
#1623=ORIENTED_EDGE('',*,*,#1047,.T.);
#1624=CARTESIAN_POINT('',(0.,0.,0.));
#1625=DIRECTION('',(0.,0.,-1.));
#1626=DIRECTION('',(-1.,0.,0.));
#1627=AXIS2_PLACEMENT_3D('',#1624,#1625,#1626);
#1628=CIRCLE('',#1627,4.);
#1629=EDGE_CURVE('E509',#1044,#1324,#1628,.T.);
#1630=ORIENTED_EDGE('',*,*,#1629,.T.);
#1631=ORIENTED_EDGE('',*,*,#1325,.T.);
#1632=EDGE_LOOP('',(#1623,#1630,#1631));
#1633=FACE_BOUND('',#1632,.T.);
#1634=ADVANCED_FACE('F184',(#1633),#1603,.T.);
#1635=ORIENTED_EDGE('',*,*,#799,.T.);
#1636=EDGE_CURVE('E148',#796,#1044,#1610,.F.);
#1637=ORIENTED_EDGE('',*,*,#1636,.T.);
#1638=ORIENTED_EDGE('',*,*,#1045,.T.);
#1639=EDGE_LOOP('',(#1635,#1637,#1638));
#1640=FACE_BOUND('',#1639,.T.);
#1641=ADVANCED_FACE('F144',(#1640),#1603,.T.);
#1642=ORIENTED_EDGE('',*,*,#797,.T.);
#1643=ORIENTED_EDGE('',*,*,#551,.T.);
#1644=EDGE_CURVE('E534',#548,#796,#1610,.F.);
#1645=ORIENTED_EDGE('',*,*,#1644,.T.);
#1646=EDGE_LOOP('',(#1642,#1643,#1645));
#1647=FACE_BOUND('',#1646,.T.);
#1648=ADVANCED_FACE('F541',(#1647),#1603,.T.);
#1649=ORIENTED_EDGE('',*,*,#549,.T.);
#1650=ORIENTED_EDGE('',*,*,#271,.T.);
#1651=EDGE_CURVE('E526',#268,#548,#1610,.F.);
#1652=ORIENTED_EDGE('',*,*,#1651,.T.);
#1653=EDGE_LOOP('',(#1649,#1650,#1652));
#1654=FACE_BOUND('',#1653,.T.);
#1655=ADVANCED_FACE('F524',(#1654),#1603,.T.);
#1656=CARTESIAN_POINT('',(4.61880215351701,0.,0.));
#1657=DIRECTION('',(0.,0.,1.));
#1658=DIRECTION('',(1.,0.,0.));
#1659=AXIS2_PLACEMENT_3D('',#1656,#1657,#1658);
#1660=PLANE('',#1659);
#1661=CARTESIAN_POINT('',(0.,0.,0.));
#1662=DIRECTION('',(0.,0.,1.));
#1663=DIRECTION('',(1.,0.,0.));
#1664=AXIS2_PLACEMENT_3D('',#1661,#1662,#1663);
#1665=CIRCLE('',#1664,1.7);
#1666=CARTESIAN_POINT('',(1.7,0.,0.));
#1667=VERTEX_POINT('',#1666);
#1668=EDGE_CURVE('E505',#1667,#1667,#1665,.T.);
#1669=ORIENTED_EDGE('',*,*,#1668,.F.);
#1670=EDGE_LOOP('',(#1669));
#1671=FACE_BOUND('',#1670,.T.);
#1672=ORIENTED_EDGE('',*,*,#1651,.F.);
#1673=ORIENTED_EDGE('',*,*,#1611,.F.);
#1674=ORIENTED_EDGE('',*,*,#1617,.F.);
#1675=ORIENTED_EDGE('',*,*,#1629,.F.);
#1676=ORIENTED_EDGE('',*,*,#1636,.F.);
#1677=ORIENTED_EDGE('',*,*,#1644,.F.);
#1678=EDGE_LOOP('',(#1672,#1673,#1674,#1675,#1676,#1677));
#1679=FACE_BOUND('',#1678,.T.);
#1680=ADVANCED_FACE('F533',(#1671,#1679),#1660,.T.);
#1681=CARTESIAN_POINT('',(0.,0.,-5.3));
#1682=DIRECTION('',(0.,0.,1.));
#1683=DIRECTION('',(1.,0.,0.));
#1684=AXIS2_PLACEMENT_3D('',#1681,#1682,#1683);
#1685=CYLINDRICAL_SURFACE('',#1684,1.7);
#1686=CARTESIAN_POINT('',(0.,0.,-4.81428571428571));
#1687=DIRECTION('',(0.,0.,1.));
#1688=DIRECTION('',(1.,0.,0.));
#1689=AXIS2_PLACEMENT_3D('',#1686,#1687,#1688);
#1690=CIRCLE('',#1689,1.7);
#1691=CARTESIAN_POINT('',(-1.7,0.,-4.81428571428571));
#1692=VERTEX_POINT('',#1691);
#1693=EDGE_CURVE('E483',#1692,#1692,#1690,.F.);
#1694=ORIENTED_EDGE('',*,*,#1693,.T.);
#1695=EDGE_LOOP('',(#1694));
#1696=FACE_BOUND('',#1695,.T.);
#1697=ORIENTED_EDGE('',*,*,#1668,.T.);
#1698=EDGE_LOOP('',(#1697));
#1699=FACE_BOUND('',#1698,.T.);
#1700=ADVANCED_FACE('F187',(#1696,#1699),#1685,.F.);
#1701=CARTESIAN_POINT('',(0.,0.,-5.3));
#1702=DIRECTION('',(0.,0.,-1.));
#1703=DIRECTION('',(-1.,0.,0.));
#1704=AXIS2_PLACEMENT_3D('',#1701,#1702,#1703);
#1705=CONICAL_SURFACE('',#1704,2.18571428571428,0.785398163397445);
#1706=CARTESIAN_POINT('',(-1.7,0.,-4.81428571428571));
#1707=CARTESIAN_POINT('',(-1.70505952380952,0.,-4.81934523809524));
#1708=CARTESIAN_POINT('',(-1.71011904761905,0.,-4.82440476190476));
#1709=CARTESIAN_POINT('',(-1.7202380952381,0.,-4.83452380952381));
#1710=CARTESIAN_POINT('',(-1.72529761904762,0.,-4.83958333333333));
#1711=CARTESIAN_POINT('',(-1.73541666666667,0.,-4.84970238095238));
#1712=CARTESIAN_POINT('',(-1.74047619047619,0.,-4.8547619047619));
#1713=CARTESIAN_POINT('',(-1.75059523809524,0.,-4.86488095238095));
#1714=CARTESIAN_POINT('',(-1.75565476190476,0.,-4.86994047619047));
#1715=CARTESIAN_POINT('',(-1.76577380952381,0.,-4.88005952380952));
#1716=CARTESIAN_POINT('',(-1.77083333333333,0.,-4.88511904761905));
#1717=CARTESIAN_POINT('',(-1.78095238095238,0.,-4.89523809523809));
#1718=CARTESIAN_POINT('',(-1.7860119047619,0.,-4.90029761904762));
#1719=CARTESIAN_POINT('',(-1.79613095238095,0.,-4.91041666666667));
#1720=CARTESIAN_POINT('',(-1.80119047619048,0.,-4.91547619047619));
#1721=CARTESIAN_POINT('',(-1.81130952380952,0.,-4.92559523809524));
#1722=CARTESIAN_POINT('',(-1.81636904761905,0.,-4.93065476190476));
#1723=CARTESIAN_POINT('',(-1.8264880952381,0.,-4.94077380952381));
#1724=CARTESIAN_POINT('',(-1.83154761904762,0.,-4.94583333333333));
#1725=CARTESIAN_POINT('',(-1.84166666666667,0.,-4.95595238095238));
#1726=CARTESIAN_POINT('',(-1.84672619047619,0.,-4.9610119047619));
#1727=CARTESIAN_POINT('',(-1.85684523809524,0.,-4.97113095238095));
#1728=CARTESIAN_POINT('',(-1.86190476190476,0.,-4.97619047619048));
#1729=CARTESIAN_POINT('',(-1.87202380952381,0.,-4.98630952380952));
#1730=CARTESIAN_POINT('',(-1.87708333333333,0.,-4.99136904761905));
#1731=CARTESIAN_POINT('',(-1.88720238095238,0.,-5.00148809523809));
#1732=CARTESIAN_POINT('',(-1.8922619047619,0.,-5.00654761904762));
#1733=CARTESIAN_POINT('',(-1.90238095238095,0.,-5.01666666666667));
#1734=CARTESIAN_POINT('',(-1.90744047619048,0.,-5.02172619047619));
#1735=CARTESIAN_POINT('',(-1.91755952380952,0.,-5.03184523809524));
#1736=CARTESIAN_POINT('',(-1.92261904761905,0.,-5.03690476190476));
#1737=CARTESIAN_POINT('',(-1.9327380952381,0.,-5.04702380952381));
#1738=CARTESIAN_POINT('',(-1.93779761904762,0.,-5.05208333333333));
#1739=CARTESIAN_POINT('',(-1.94791666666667,0.,-5.06220238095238));
#1740=CARTESIAN_POINT('',(-1.95297619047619,0.,-5.0672619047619));
#1741=CARTESIAN_POINT('',(-1.96309523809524,0.,-5.07738095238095));
#1742=CARTESIAN_POINT('',(-1.96815476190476,0.,-5.08244047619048));
#1743=CARTESIAN_POINT('',(-1.97827380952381,0.,-5.09255952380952));
#1744=CARTESIAN_POINT('',(-1.98333333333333,0.,-5.09761904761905));
#1745=CARTESIAN_POINT('',(-1.99345238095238,0.,-5.1077380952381));
#1746=CARTESIAN_POINT('',(-1.9985119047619,0.,-5.11279761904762));
#1747=CARTESIAN_POINT('',(-2.00863095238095,0.,-5.12291666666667));
#1748=CARTESIAN_POINT('',(-2.01369047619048,0.,-5.12797619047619));
#1749=CARTESIAN_POINT('',(-2.02380952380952,0.,-5.13809523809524));
#1750=CARTESIAN_POINT('',(-2.02886904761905,0.,-5.14315476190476));
#1751=CARTESIAN_POINT('',(-2.03898809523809,0.,-5.15327380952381));
#1752=CARTESIAN_POINT('',(-2.04404761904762,0.,-5.15833333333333));
#1753=CARTESIAN_POINT('',(-2.05416666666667,0.,-5.16845238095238));
#1754=CARTESIAN_POINT('',(-2.05922619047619,0.,-5.1735119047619));
#1755=CARTESIAN_POINT('',(-2.06934523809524,0.,-5.18363095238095));
#1756=CARTESIAN_POINT('',(-2.07440476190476,0.,-5.18869047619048));
#1757=CARTESIAN_POINT('',(-2.08452380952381,0.,-5.19880952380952));
#1758=CARTESIAN_POINT('',(-2.08958333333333,0.,-5.20386904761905));
#1759=CARTESIAN_POINT('',(-2.09970238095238,0.,-5.2139880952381));
#1760=CARTESIAN_POINT('',(-2.1047619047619,0.,-5.21904761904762));
#1761=CARTESIAN_POINT('',(-2.11488095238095,0.,-5.22916666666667));
#1762=CARTESIAN_POINT('',(-2.11994047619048,0.,-5.23422619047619));
#1763=CARTESIAN_POINT('',(-2.13005952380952,0.,-5.24434523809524));
#1764=CARTESIAN_POINT('',(-2.13511904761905,0.,-5.24940476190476));
#1765=CARTESIAN_POINT('',(-2.1452380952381,0.,-5.25952380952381));
#1766=CARTESIAN_POINT('',(-2.15029761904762,0.,-5.26458333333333));
#1767=CARTESIAN_POINT('',(-2.16041666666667,0.,-5.27470238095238));
#1768=CARTESIAN_POINT('',(-2.16547619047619,0.,-5.27976190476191));
#1769=CARTESIAN_POINT('',(-2.17559523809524,0.,-5.28988095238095));
#1770=CARTESIAN_POINT('',(-2.18065476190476,0.,-5.29494047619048));
#1771=CARTESIAN_POINT('',(-2.18571428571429,0.,-5.3));
#1772=B_SPLINE_CURVE_WITH_KNOTS('',3,(#1706,#1707,#1708,#1709,#1710,#1711,#1712,#1713,#1714,
#1715,#1716,#1717,#1718,#1719,#1720,#1721,#1722,#1723,#1724,#1725,#1726,#1727,#1728,#1729,#1730,
#1731,#1732,#1733,#1734,#1735,#1736,#1737,#1738,#1739,#1740,#1741,#1742,#1743,#1744,#1745,#1746,
#1747,#1748,#1749,#1750,#1751,#1752,#1753,#1754,#1755,#1756,#1757,#1758,#1759,#1760,#1761,#1762,
#1763,#1764,#1765,#1766,#1767,#1768,#1769,#1770,#1771),.UNSPECIFIED.,.F.,.F.,(4,2,2,2,2,2,2,2,2,
2,2,2,2,2,2,2,2,2,2,2,2,2,2,2,2,2,2,2,2,2,2,2,4),(0.,0.0214657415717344,0.0429314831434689,
0.0643972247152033,0.0858629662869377,0.107328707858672,0.128794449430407,0.150260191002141,
0.171725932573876,0.19319167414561,0.214657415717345,0.236123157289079,0.257588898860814,
0.279054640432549,0.300520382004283,0.321986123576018,0.343451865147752,0.364917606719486,
0.386383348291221,0.407849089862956,0.42931483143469,0.450780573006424,0.472246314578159,
0.493712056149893,0.515177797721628,0.536643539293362,0.558109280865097,0.579575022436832,
0.601040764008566,0.622506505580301,0.643972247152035,0.665437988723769,0.686903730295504),.UNSPECIFIED.);
#1773=EDGE_CURVE('BSEAM412',#1692,#1582,#1772,.T.);
#1774=ORIENTED_EDGE('',*,*,#1693,.F.);
#1775=ORIENTED_EDGE('',*,*,#1583,.F.);
#1776=ORIENTED_EDGE('',*,*,#1773,.T.);
#1777=ORIENTED_EDGE('',*,*,#1773,.F.);
#1778=EDGE_LOOP('',(#1774,#1776,#1775,#1777));
#1779=FACE_BOUND('',#1778,.T.);
#1780=ADVANCED_FACE('F412',(#1779),#1705,.F.);
#1781=CARTESIAN_POINT('',(0.,0.,-4.7913338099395));
#1782=DIRECTION('',(0.,0.,-1.));
#1783=DIRECTION('',(-1.,0.,0.));
#1784=AXIS2_PLACEMENT_3D('',#1781,#1782,#1783);
#1785=TOROIDAL_SURFACE('',#1784,5.3913338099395,0.5086661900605);
#1786=CARTESIAN_POINT('',(0.,0.,-4.3));
#1787=DIRECTION('',(0.,0.,-1.));
#1788=DIRECTION('',(-1.,0.,0.));
#1789=AXIS2_PLACEMENT_3D('',#1786,#1787,#1788);
#1790=CIRCLE('',#1789,5.5229863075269);
#1791=CARTESIAN_POINT('',(-5.5229863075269,0.,-4.3));
#1792=VERTEX_POINT('',#1791);
#1793=EDGE_CURVE('E500',#1792,#1792,#1790,.T.);
#1794=ORIENTED_EDGE('',*,*,#1793,.T.);
#1795=EDGE_LOOP('',(#1794));
#1796=FACE_BOUND('',#1795,.T.);
#1797=ORIENTED_EDGE('',*,*,#1594,.F.);
#1798=EDGE_LOOP('',(#1797));
#1799=FACE_BOUND('',#1798,.T.);
#1800=ADVANCED_FACE('F497',(#1796,#1799),#1785,.T.);
#1801=CARTESIAN_POINT('',(0.,0.,-4.05772458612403));
#1802=DIRECTION('',(0.,0.,-1.));
#1803=DIRECTION('',(-1.,0.,0.));
#1804=AXIS2_PLACEMENT_3D('',#1801,#1802,#1803);
#1805=CONICAL_SURFACE('',#1804,4.61880215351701,1.30899693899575);
#1806=CARTESIAN_POINT('',(-1.51719352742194,-5.86328355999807,-4.44292753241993));
#1807=CARTESIAN_POINT('',(-1.6060923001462,-5.70702251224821,-4.40837624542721));
#1808=CARTESIAN_POINT('',(-1.69499683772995,-5.55066351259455,-4.37480849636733));
#1809=CARTESIAN_POINT('',(-1.87286389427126,-5.23772842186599,-4.31015361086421));
#1810=CARTESIAN_POINT('',(-1.96182642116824,-5.08115229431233,-4.2790669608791));
#1811=CARTESIAN_POINT('',(-2.1400404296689,-4.76743689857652,-4.21982884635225));
#1812=CARTESIAN_POINT('',(-2.22929208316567,-4.61029719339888,-4.19168480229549));
#1813=CARTESIAN_POINT('',(-2.40790002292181,-4.29589395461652,-4.13906175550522));
#1814=CARTESIAN_POINT('',(-2.49725630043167,-4.13863043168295,-4.1145824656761));
#1815=CARTESIAN_POINT('',(-2.76415802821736,-3.66922375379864,-4.04808912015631));
#1816=CARTESIAN_POINT('',(-2.94198280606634,-3.35691346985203,-4.01251575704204));
#1817=CARTESIAN_POINT('',(-3.20947317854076,-2.88902107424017,-3.97624885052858));
#1818=CARTESIAN_POINT('',(-3.29867820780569,-2.73329813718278,-3.96700941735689));
#1819=CARTESIAN_POINT('',(-3.43274050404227,-2.49986341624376,-3.95772489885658));
#1820=CARTESIAN_POINT('',(-3.47746138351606,-2.42209240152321,-3.95539250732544));
#1821=CARTESIAN_POINT('',(-3.56699429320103,-2.26659862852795,-3.95227742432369));
#1822=CARTESIAN_POINT('',(-3.61180632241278,-2.18887586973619,-3.95149471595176));
#1823=CARTESIAN_POINT('',(-3.76895259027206,-1.91669281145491,-3.95150166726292));
#1824=CARTESIAN_POINT('',(-3.88153811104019,-1.72235904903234,-3.95642296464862));
#1825=CARTESIAN_POINT('',(-4.10718621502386,-1.33405956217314,-3.97570611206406));
#1826=CARTESIAN_POINT('',(-4.22024886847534,-1.14009389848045,-3.99006940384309));
#1827=CARTESIAN_POINT('',(-4.5599895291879,-0.558444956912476,-4.04576410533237));
#1828=CARTESIAN_POINT('',(-4.78707554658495,-0.171259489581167,-4.09969805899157));
#1829=CARTESIAN_POINT('',(-5.24155827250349,0.603400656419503,-4.23020029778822));
#1830=CARTESIAN_POINT('',(-5.46895307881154,0.990871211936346,-4.30685065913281));
#1831=CARTESIAN_POINT('',(-5.92270549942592,1.76497708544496,-4.4738251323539));
#1832=CARTESIAN_POINT('',(-6.14906336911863,2.15161259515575,-4.5641456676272));
#1833=CARTESIAN_POINT('',(-6.60414410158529,2.92997662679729,-4.75458782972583));
#1834=CARTESIAN_POINT('',(-6.83285336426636,3.32169726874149,-4.85483309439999));
#1835=CARTESIAN_POINT('',(-7.28951505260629,4.10474766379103,-5.06080005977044));
#1836=CARTESIAN_POINT('',(-7.51746746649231,4.49607741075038,-5.16652184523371));
#1837=CARTESIAN_POINT('',(-7.97232419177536,5.27763577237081,-5.38135366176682));
#1838=CARTESIAN_POINT('',(-8.19922969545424,5.66786499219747,-5.49045624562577));
#1839=CARTESIAN_POINT('',(-8.65260283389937,6.44810029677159,-5.71113983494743));
#1840=CARTESIAN_POINT('',(-8.87907047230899,6.8381063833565,-5.82272081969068));
#1841=CARTESIAN_POINT('',(-9.582982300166,8.05094836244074,-6.17247056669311));
#1842=CARTESIAN_POINT('',(-10.0598640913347,8.87350005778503,-6.41361722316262));
#1843=CARTESIAN_POINT('',(-11.0131014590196,10.5187124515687,-6.9001183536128));
#1844=CARTESIAN_POINT('',(-11.4894564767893,11.3413728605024,-7.14547551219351));
#1845=CARTESIAN_POINT('',(-12.4298950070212,12.966126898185,-7.63253934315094));
#1846=CARTESIAN_POINT('',(-12.8939913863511,13.7682273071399,-7.874186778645));
#1847=CARTESIAN_POINT('',(-13.8215293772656,15.3717118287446,-8.35887906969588));
#1848=CARTESIAN_POINT('',(-14.2849712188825,16.1730960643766,-8.60192289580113));
#1849=CARTESIAN_POINT('',(-14.7483162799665,16.9744266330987,-8.84536760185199));
#1850=B_SPLINE_CURVE_WITH_KNOTS('',3,(#1806,#1807,#1808,#1809,#1810,#1811,#1812,#1813,#1814,
#1815,#1816,#1817,#1818,#1819,#1820,#1821,#1822,#1823,#1824,#1825,#1826,#1827,#1828,#1829,#1830,
#1831,#1832,#1833,#1834,#1835,#1836,#1837,#1838,#1839,#1840,#1841,#1842,#1843,#1844,#1845,#1846,
#1847,#1848,#1849),.UNSPECIFIED.,.F.,.F.,(4,2,2,2,2,2,2,2,2,2,2,2,2,2,2,2,2,2,2,2,2,4),(0.,
0.552519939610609,1.10514794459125,1.65913752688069,2.21308368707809,3.3119805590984,
3.86040189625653,4.13450243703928,4.40859998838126,5.0946817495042,5.7808682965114,
7.15412270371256,8.53240056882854,9.91031844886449,11.3083144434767,12.7063320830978,
14.1014629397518,15.496582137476,18.4409238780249,21.3872183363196,24.2608389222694,
27.1325597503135),.UNSPECIFIED.);
#1851=CARTESIAN_POINT('',(-2.44378330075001,-4.2327568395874,-4.12973980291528));
#1852=VERTEX_POINT('',#1851);
#1853=CARTESIAN_POINT('',(-4.88756660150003,0.,-4.12973980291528));
#1854=VERTEX_POINT('',#1853);
#1855=EDGE_CURVE('E475',#1852,#1854,#1850,.T.);
#1856=ORIENTED_EDGE('',*,*,#1855,.T.);
#1857=CARTESIAN_POINT('',(-5.83634927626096,-1.61771364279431,-4.44292753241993));
#1858=CARTESIAN_POINT('',(-5.74547262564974,-1.46259452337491,-4.40837624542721));
#1859=CARTESIAN_POINT('',(-5.65451402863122,-1.30742143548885,-4.37480849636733));
#1860=CARTESIAN_POINT('',(-5.47243781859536,-0.996916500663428,-4.31015361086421));
#1861=CARTESIAN_POINT('',(-5.38132017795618,-0.841584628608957,-4.2790669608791));
#1862=CARTESIAN_POINT('',(-5.198741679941,-0.530389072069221,-4.21982884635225));
#1863=CARTESIAN_POINT('',(-5.10728053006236,-0.374525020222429,-4.19168480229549));
#1864=CARTESIAN_POINT('',(-4.9243033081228,-0.0626443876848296,-4.13906175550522));
#1865=CARTESIAN_POINT('',(-4.83278724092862,0.0933721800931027,-4.11458246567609));
#1866=CARTESIAN_POINT('',(-4.5597199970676,0.55921919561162,-4.04808912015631));
#1867=CARTESIAN_POINT('',(-4.37816374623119,0.86937511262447,-4.01251575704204));
#1868=CARTESIAN_POINT('',(-4.10670223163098,1.33497476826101,-3.97624885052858));
#1869=CARTESIAN_POINT('',(-4.01644472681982,1.49009005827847,-3.96700941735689));
#1870=CARTESIAN_POINT('',(-3.88131547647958,1.72290877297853,-3.95772489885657));
#1871=CARTESIAN_POINT('',(-3.83632424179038,1.80052369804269,-3.95539250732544));
#1872=CARTESIAN_POINT('',(-3.74642913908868,1.95580835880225,-3.95227742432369));
#1873=CARTESIAN_POINT('',(-3.70152527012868,2.03347809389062,-3.95149471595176));
#1874=CARTESIAN_POINT('',(-3.544380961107,2.30566228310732,-3.95150166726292));
#1875=CARTESIAN_POINT('',(-3.4323757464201,2.5003310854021,-3.95642296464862));
#1876=CARTESIAN_POINT('',(-3.20892257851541,2.88989781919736,-3.97570611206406));
#1877=CARTESIAN_POINT('',(-3.09747471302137,3.08479578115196,-3.99006940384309));
#1878=CARTESIAN_POINT('',(-2.76362228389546,3.66984429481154,-4.04576410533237));
#1879=CARTESIAN_POINT('',(-2.54185284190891,4.06009928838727,-4.09969805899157));
#1880=CARTESIAN_POINT('',(-2.09821883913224,4.84102294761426,-4.23020029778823));
#1881=CARTESIAN_POINT('',(-1.87635689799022,5.23168790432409,-4.30685065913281));
#1882=CARTESIAN_POINT('',(-1.4328377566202,6.01170196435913,-4.47382513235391));
#1883=CARTESIAN_POINT('',(-1.21118051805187,6.40105138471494,-4.5641456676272));
#1884=CARTESIAN_POINT('',(-0.764637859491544,7.18434487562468,-4.75458782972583));
#1885=CARTESIAN_POINT('',(-0.539752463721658,7.57827322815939,-4.85483309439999));
#1886=CARTESIAN_POINT('',(-0.0899417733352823,8.36527904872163,-5.06080005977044));
#1887=CARTESIAN_POINT('',(0.134983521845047,8.75835650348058,-5.16652184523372));
#1888=CARTESIAN_POINT('',(0.584404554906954,9.54305316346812,-5.38135366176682));
#1889=CARTESIAN_POINT('',(0.808900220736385,9.93467370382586,-5.49045624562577));
#1890=CARTESIAN_POINT('',(1.25791724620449,10.7174240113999,-5.71113983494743));
#1891=CARTESIAN_POINT('',(1.48243860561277,11.1085537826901,-5.82272081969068));
#1892=CARTESIAN_POINT('',(2.18083465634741,12.3245802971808,-6.17247056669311));
#1893=CARTESIAN_POINT('',(2.65474442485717,13.1488478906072,-6.41361722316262));
#1894=CARTESIAN_POINT('',(3.60292146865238,14.7969818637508,-6.9001183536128));
#1895=CARTESIAN_POINT('',(4.07718877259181,15.6208476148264,-7.14547551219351));
#1896=CARTESIAN_POINT('',(5.0140477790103,17.2476682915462,-7.63253934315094));
#1897=CARTESIAN_POINT('',(5.47663891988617,18.0506377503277,-7.874186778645));
#1898=CARTESIAN_POINT('',(6.40152825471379,19.6556514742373,-8.35887906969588));
#1899=CARTESIAN_POINT('',(6.86382644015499,20.4576960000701,-8.60192289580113));
#1900=CARTESIAN_POINT('',(7.32612653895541,21.2596298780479,-8.84536760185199));
#1901=B_SPLINE_CURVE_WITH_KNOTS('',3,(#1857,#1858,#1859,#1860,#1861,#1862,#1863,#1864,#1865,
#1866,#1867,#1868,#1869,#1870,#1871,#1872,#1873,#1874,#1875,#1876,#1877,#1878,#1879,#1880,#1881,
#1882,#1883,#1884,#1885,#1886,#1887,#1888,#1889,#1890,#1891,#1892,#1893,#1894,#1895,#1896,#1897,
#1898,#1899,#1900),.UNSPECIFIED.,.F.,.F.,(4,2,2,2,2,2,2,2,2,2,2,2,2,2,2,2,2,2,2,2,2,4),(0.,
0.552519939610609,1.10514794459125,1.6591375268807,2.21308368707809,3.3119805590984,
3.86040189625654,4.13450243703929,4.40859998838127,5.09468174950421,5.7808682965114,
7.15412270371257,8.53240056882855,9.9103184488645,11.3083144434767,12.7063320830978,
14.1014629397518,15.496582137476,18.4409238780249,21.3872183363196,24.2608389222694,
27.1325597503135),.UNSPECIFIED.);
#1902=CARTESIAN_POINT('',(-2.44378330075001,4.2327568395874,-4.12973980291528));
#1903=VERTEX_POINT('',#1902);
#1904=EDGE_CURVE('E310',#1854,#1903,#1901,.T.);
#1905=ORIENTED_EDGE('',*,*,#1904,.T.);
#1906=CARTESIAN_POINT('',(-4.31523086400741,4.24554491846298,-4.4421729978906));
#1907=CARTESIAN_POINT('',(-4.13545131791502,4.24440241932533,-4.40763598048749));
#1908=CARTESIAN_POINT('',(-3.95558401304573,4.24321596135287,-4.37408397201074));
#1909=CARTESIAN_POINT('',(-3.59563232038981,4.24078489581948,-4.30946423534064));
#1910=CARTESIAN_POINT('',(-3.41554789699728,4.23954027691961,-4.27839699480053));
#1911=CARTESIAN_POINT('',(-3.05474796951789,4.2370200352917,-4.21920233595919));
#1912=CARTESIAN_POINT('',(-2.87403200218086,4.2357443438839,-4.19108233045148));
#1913=CARTESIAN_POINT('',(-2.51244058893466,4.23322215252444,-4.13851236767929));
#1914=CARTESIAN_POINT('',(-2.3315651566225,4.23197565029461,-4.11406212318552));
#1915=CARTESIAN_POINT('',(-1.79158727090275,4.22841841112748,-4.04766385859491));
#1916=CARTESIAN_POINT('',(-1.43220058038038,4.22626706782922,-4.01216478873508));
#1917=CARTESIAN_POINT('',(-0.893240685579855,4.223981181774,-3.97602274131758));
#1918=CARTESIAN_POINT('',(-0.71377524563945,4.22337620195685,-3.96682711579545));
#1919=CARTESIAN_POINT('',(-0.444579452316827,4.22276453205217,-3.95761017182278));
#1920=CARTESIAN_POINT('',(-0.354865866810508,4.22260994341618,-3.95530061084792));
#1921=CARTESIAN_POINT('',(-0.175434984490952,4.22240389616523,-3.95223155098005));
#1922=CARTESIAN_POINT('',(-0.0857176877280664,4.22235243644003,-3.95147203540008));
#1923=CARTESIAN_POINT('',(0.228223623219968,4.22235903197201,-3.95156015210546));
#1924=CARTESIAN_POINT('',(0.452463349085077,4.22269690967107,-3.95652396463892));
#1925=CARTESIAN_POINT('',(0.900862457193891,4.22396729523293,-3.97585909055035));
#1926=CARTESIAN_POINT('',(1.12502182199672,4.22489989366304,-3.99023183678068));
#1927=CARTESIAN_POINT('',(1.79756013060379,4.22829760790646,-4.04590984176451));
#1928=CARTESIAN_POINT('',(2.24571228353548,4.23136221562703,-4.09977252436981));
#1929=CARTESIAN_POINT('',(3.14241799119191,4.23761584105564,-4.23006303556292));
#1930=CARTESIAN_POINT('',(3.59096705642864,4.24080527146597,-4.30657238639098));
#1931=CARTESIAN_POINT('',(4.4868271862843,4.24670559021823,-4.4732347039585));
#1932=CARTESIAN_POINT('',(4.93413854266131,4.24941660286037,-4.56338411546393));
#1933=CARTESIAN_POINT('',(5.83432875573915,4.25434168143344,-4.75346485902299));
#1934=CARTESIAN_POINT('',(6.28719405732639,4.25654795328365,-4.85351930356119));
#1935=CARTESIAN_POINT('',(7.19220902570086,4.26050146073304,-5.05909897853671));
#1936=CARTESIAN_POINT('',(7.64435868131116,4.26224868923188,-5.16462429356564));
#1937=CARTESIAN_POINT('',(8.54718613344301,4.26538654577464,-5.37906222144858));
#1938=CARTESIAN_POINT('',(8.9978650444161,4.26677789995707,-5.48796742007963));
#1939=CARTESIAN_POINT('',(9.89881107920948,4.26929322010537,-5.70825555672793));
#1940=CARTESIAN_POINT('',(10.3490782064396,4.27041718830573,-5.81963847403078));
#1941=CARTESIAN_POINT('',(11.749064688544,4.27360259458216,-6.16875311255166));
#1942=CARTESIAN_POINT('',(12.6982571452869,4.27531933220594,-6.40946211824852));
#1943=CARTESIAN_POINT('',(14.5964698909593,4.27824262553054,-6.89508816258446));
#1944=CARTESIAN_POINT('',(15.5454896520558,4.27944884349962,-7.14000787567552));
#1945=CARTESIAN_POINT('',(17.4196769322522,4.28151719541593,-7.62622320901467));
#1946=CARTESIAN_POINT('',(18.3448567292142,4.28238706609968,-7.86745970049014));
#1947=CARTESIAN_POINT('',(20.1942718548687,4.28391779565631,-8.35133219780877));
#1948=CARTESIAN_POINT('',(21.1185074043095,4.2845787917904,-8.59396717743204));
#1949=CARTESIAN_POINT('',(22.0426480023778,4.28518274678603,-8.83700350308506));
#1950=B_SPLINE_CURVE_WITH_KNOTS('',3,(#1906,#1907,#1908,#1909,#1910,#1911,#1912,#1913,#1914,
#1915,#1916,#1917,#1918,#1919,#1920,#1921,#1922,#1923,#1924,#1925,#1926,#1927,#1928,#1929,#1930,
#1931,#1932,#1933,#1934,#1935,#1936,#1937,#1938,#1939,#1940,#1941,#1942,#1943,#1944,#1945,#1946,
#1947,#1948,#1949),.UNSPECIFIED.,.F.,.F.,(4,2,2,2,2,2,2,2,2,2,2,2,2,2,2,2,2,2,2,2,2,4),(0.,
0.552528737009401,1.10516564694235,1.65916076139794,2.21311249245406,3.31202001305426,
3.86044861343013,4.13455324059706,4.40865491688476,5.09366558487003,5.77878059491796,
7.14988692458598,8.52599018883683,9.9017353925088,11.297472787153,12.693231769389,
14.0861196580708,15.4789959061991,18.4183677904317,21.3596811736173,24.2286152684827,
27.0956601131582),.UNSPECIFIED.);
#1951=CARTESIAN_POINT('',(2.44378330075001,4.2327568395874,-4.12973980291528));
#1952=VERTEX_POINT('',#1951);
#1953=EDGE_CURVE('E304',#1903,#1952,#1950,.T.);
#1954=ORIENTED_EDGE('',*,*,#1953,.T.);
#1955=CARTESIAN_POINT('',(1.51719352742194,5.86328355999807,-4.44292753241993));
#1956=CARTESIAN_POINT('',(1.6060923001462,5.70702251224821,-4.40837624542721));
#1957=CARTESIAN_POINT('',(1.69499683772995,5.55066351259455,-4.37480849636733));
#1958=CARTESIAN_POINT('',(1.87286389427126,5.23772842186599,-4.31015361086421));
#1959=CARTESIAN_POINT('',(1.96182642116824,5.08115229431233,-4.2790669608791));
#1960=CARTESIAN_POINT('',(2.1400404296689,4.76743689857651,-4.21982884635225));
#1961=CARTESIAN_POINT('',(2.22929208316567,4.61029719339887,-4.19168480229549));
#1962=CARTESIAN_POINT('',(2.40790002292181,4.29589395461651,-4.13906175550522));
#1963=CARTESIAN_POINT('',(2.49725630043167,4.13863043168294,-4.1145824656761));
#1964=CARTESIAN_POINT('',(2.76415802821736,3.66922375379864,-4.04808912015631));
#1965=CARTESIAN_POINT('',(2.94198280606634,3.35691346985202,-4.01251575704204));
#1966=CARTESIAN_POINT('',(3.20947317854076,2.88902107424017,-3.97624885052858));
#1967=CARTESIAN_POINT('',(3.29867820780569,2.73329813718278,-3.96700941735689));
#1968=CARTESIAN_POINT('',(3.43274050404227,2.49986341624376,-3.95772489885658));
#1969=CARTESIAN_POINT('',(3.47746138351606,2.4220924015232,-3.95539250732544));
#1970=CARTESIAN_POINT('',(3.56699429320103,2.26659862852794,-3.95227742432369));
#1971=CARTESIAN_POINT('',(3.61180632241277,2.18887586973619,-3.95149471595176));
#1972=CARTESIAN_POINT('',(3.76895259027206,1.91669281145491,-3.95150166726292));
#1973=CARTESIAN_POINT('',(3.88153811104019,1.72235904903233,-3.95642296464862));
#1974=CARTESIAN_POINT('',(4.10718621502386,1.33405956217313,-3.97570611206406));
#1975=CARTESIAN_POINT('',(4.22024886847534,1.14009389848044,-3.99006940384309));
#1976=CARTESIAN_POINT('',(4.5599895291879,0.558444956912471,-4.04576410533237));
#1977=CARTESIAN_POINT('',(4.78707554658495,0.171259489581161,-4.09969805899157));
#1978=CARTESIAN_POINT('',(5.24155827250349,-0.603400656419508,-4.23020029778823));
#1979=CARTESIAN_POINT('',(5.46895307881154,-0.99087121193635,-4.30685065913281));
#1980=CARTESIAN_POINT('',(5.92270549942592,-1.76497708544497,-4.47382513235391));
#1981=CARTESIAN_POINT('',(6.14906336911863,-2.15161259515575,-4.5641456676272));
#1982=CARTESIAN_POINT('',(6.60414410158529,-2.9299766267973,-4.75458782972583));
#1983=CARTESIAN_POINT('',(6.83285336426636,-3.32169726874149,-4.85483309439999));
#1984=CARTESIAN_POINT('',(7.2895150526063,-4.10474766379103,-5.06080005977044));
#1985=CARTESIAN_POINT('',(7.51746746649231,-4.49607741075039,-5.16652184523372));
#1986=CARTESIAN_POINT('',(7.97232419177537,-5.27763577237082,-5.38135366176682));
#1987=CARTESIAN_POINT('',(8.19922969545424,-5.66786499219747,-5.49045624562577));
#1988=CARTESIAN_POINT('',(8.65260283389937,-6.44810029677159,-5.71113983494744));
#1989=CARTESIAN_POINT('',(8.87907047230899,-6.83810638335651,-5.82272081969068));
#1990=CARTESIAN_POINT('',(9.582982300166,-8.05094836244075,-6.17247056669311));
#1991=CARTESIAN_POINT('',(10.0598640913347,-8.87350005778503,-6.41361722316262));
#1992=CARTESIAN_POINT('',(11.0131014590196,-10.5187124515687,-6.90011835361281));
#1993=CARTESIAN_POINT('',(11.4894564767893,-11.3413728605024,-7.14547551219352));
#1994=CARTESIAN_POINT('',(12.4298950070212,-12.966126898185,-7.63253934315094));
#1995=CARTESIAN_POINT('',(12.8939913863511,-13.7682273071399,-7.874186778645));
#1996=CARTESIAN_POINT('',(13.8215293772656,-15.3717118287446,-8.35887906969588));
#1997=CARTESIAN_POINT('',(14.2849712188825,-16.1730960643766,-8.60192289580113));
#1998=CARTESIAN_POINT('',(14.7483162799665,-16.9744266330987,-8.84536760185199));
#1999=B_SPLINE_CURVE_WITH_KNOTS('',3,(#1955,#1956,#1957,#1958,#1959,#1960,#1961,#1962,#1963,
#1964,#1965,#1966,#1967,#1968,#1969,#1970,#1971,#1972,#1973,#1974,#1975,#1976,#1977,#1978,#1979,
#1980,#1981,#1982,#1983,#1984,#1985,#1986,#1987,#1988,#1989,#1990,#1991,#1992,#1993,#1994,#1995,
#1996,#1997,#1998),.UNSPECIFIED.,.F.,.F.,(4,2,2,2,2,2,2,2,2,2,2,2,2,2,2,2,2,2,2,2,2,4),(0.,
0.552519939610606,1.10514794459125,1.65913752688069,2.21308368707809,3.3119805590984,
3.86040189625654,4.13450243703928,4.40859998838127,5.09468174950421,5.78086829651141,
7.15412270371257,8.53240056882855,9.9103184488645,11.3083144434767,12.7063320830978,
14.1014629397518,15.496582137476,18.4409238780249,21.3872183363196,24.2608389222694,
27.1325597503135),.UNSPECIFIED.);
#2000=CARTESIAN_POINT('',(4.88756660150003,0.,-4.12973980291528));
#2001=VERTEX_POINT('',#2000);
#2002=EDGE_CURVE('E311',#1952,#2001,#1999,.T.);
#2003=ORIENTED_EDGE('',*,*,#2002,.T.);
#2004=CARTESIAN_POINT('',(5.83634927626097,1.61771364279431,-4.44292753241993));
#2005=CARTESIAN_POINT('',(5.74547262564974,1.46259452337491,-4.40837624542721));
#2006=CARTESIAN_POINT('',(5.65451402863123,1.30742143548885,-4.37480849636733));
#2007=CARTESIAN_POINT('',(5.47243781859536,0.996916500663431,-4.31015361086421));
#2008=CARTESIAN_POINT('',(5.38132017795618,0.84158462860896,-4.2790669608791));
#2009=CARTESIAN_POINT('',(5.19874167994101,0.530389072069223,-4.21982884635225));
#2010=CARTESIAN_POINT('',(5.10728053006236,0.374525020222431,-4.19168480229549));
#2011=CARTESIAN_POINT('',(4.92430330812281,0.0626443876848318,-4.13906175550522));
#2012=CARTESIAN_POINT('',(4.83278724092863,-0.0933721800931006,-4.1145824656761));
#2013=CARTESIAN_POINT('',(4.55971999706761,-0.559219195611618,-4.04808912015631));
#2014=CARTESIAN_POINT('',(4.37816374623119,-0.869375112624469,-4.01251575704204));
#2015=CARTESIAN_POINT('',(4.10670223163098,-1.33497476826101,-3.97624885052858));
#2016=CARTESIAN_POINT('',(4.01644472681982,-1.49009005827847,-3.96700941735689));
#2017=CARTESIAN_POINT('',(3.88131547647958,-1.72290877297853,-3.95772489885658));
#2018=CARTESIAN_POINT('',(3.83632424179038,-1.80052369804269,-3.95539250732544));
#2019=CARTESIAN_POINT('',(3.74642913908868,-1.95580835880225,-3.95227742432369));
#2020=CARTESIAN_POINT('',(3.70152527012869,-2.03347809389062,-3.95149471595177));
#2021=CARTESIAN_POINT('',(3.544380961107,-2.30566228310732,-3.95150166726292));
#2022=CARTESIAN_POINT('',(3.4323757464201,-2.5003310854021,-3.95642296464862));
#2023=CARTESIAN_POINT('',(3.20892257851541,-2.88989781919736,-3.97570611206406));
#2024=CARTESIAN_POINT('',(3.09747471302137,-3.08479578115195,-3.9900694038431));
#2025=CARTESIAN_POINT('',(2.76362228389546,-3.66984429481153,-4.04576410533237));
#2026=CARTESIAN_POINT('',(2.54185284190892,-4.06009928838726,-4.09969805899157));
#2027=CARTESIAN_POINT('',(2.09821883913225,-4.84102294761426,-4.23020029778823));
#2028=CARTESIAN_POINT('',(1.87635689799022,-5.23168790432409,-4.30685065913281));
#2029=CARTESIAN_POINT('',(1.4328377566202,-6.01170196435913,-4.47382513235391));
#2030=CARTESIAN_POINT('',(1.21118051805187,-6.40105138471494,-4.5641456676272));
#2031=CARTESIAN_POINT('',(0.764637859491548,-7.18434487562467,-4.75458782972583));
#2032=CARTESIAN_POINT('',(0.539752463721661,-7.57827322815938,-4.85483309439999));
#2033=CARTESIAN_POINT('',(0.0899417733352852,-8.36527904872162,-5.06080005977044));
#2034=CARTESIAN_POINT('',(-0.134983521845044,-8.75835650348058,-5.16652184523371));
#2035=CARTESIAN_POINT('',(-0.584404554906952,-9.54305316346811,-5.38135366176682));
#2036=CARTESIAN_POINT('',(-0.808900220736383,-9.93467370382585,-5.49045624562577));
#2037=CARTESIAN_POINT('',(-1.25791724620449,-10.7174240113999,-5.71113983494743));
#2038=CARTESIAN_POINT('',(-1.48243860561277,-11.1085537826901,-5.82272081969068));
#2039=CARTESIAN_POINT('',(-2.18083465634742,-12.3245802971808,-6.17247056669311));
#2040=CARTESIAN_POINT('',(-2.65474442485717,-13.1488478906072,-6.41361722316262));
#2041=CARTESIAN_POINT('',(-3.60292146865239,-14.7969818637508,-6.9001183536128));
#2042=CARTESIAN_POINT('',(-4.07718877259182,-15.6208476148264,-7.14547551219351));
#2043=CARTESIAN_POINT('',(-5.01404777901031,-17.2476682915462,-7.63253934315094));
#2044=CARTESIAN_POINT('',(-5.47663891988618,-18.0506377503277,-7.874186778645));
#2045=CARTESIAN_POINT('',(-6.4015282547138,-19.6556514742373,-8.35887906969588));
#2046=CARTESIAN_POINT('',(-6.863826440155,-20.4576960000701,-8.60192289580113));
#2047=CARTESIAN_POINT('',(-7.32612653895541,-21.2596298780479,-8.84536760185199));
#2048=B_SPLINE_CURVE_WITH_KNOTS('',3,(#2004,#2005,#2006,#2007,#2008,#2009,#2010,#2011,#2012,
#2013,#2014,#2015,#2016,#2017,#2018,#2019,#2020,#2021,#2022,#2023,#2024,#2025,#2026,#2027,#2028,
#2029,#2030,#2031,#2032,#2033,#2034,#2035,#2036,#2037,#2038,#2039,#2040,#2041,#2042,#2043,#2044,
#2045,#2046,#2047),.UNSPECIFIED.,.F.,.F.,(4,2,2,2,2,2,2,2,2,2,2,2,2,2,2,2,2,2,2,2,2,4),(0.,
0.552519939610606,1.10514794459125,1.65913752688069,2.21308368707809,3.3119805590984,
3.86040189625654,4.13450243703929,4.40859998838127,5.09468174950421,5.78086829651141,
7.15412270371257,8.53240056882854,9.9103184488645,11.3083144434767,12.7063320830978,
14.1014629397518,15.496582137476,18.4409238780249,21.3872183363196,24.2608389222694,
27.1325597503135),.UNSPECIFIED.);
#2049=CARTESIAN_POINT('',(2.44378330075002,-4.23275683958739,-4.12973980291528));
#2050=VERTEX_POINT('',#2049);
#2051=EDGE_CURVE('E446',#2001,#2050,#2048,.T.);
#2052=ORIENTED_EDGE('',*,*,#2051,.T.);
#2053=CARTESIAN_POINT('',(4.32308448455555,-4.24559492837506,-4.44368313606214));
#2054=CARTESIAN_POINT('',(4.14331198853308,-4.24445356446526,-4.4091173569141));
#2055=CARTESIAN_POINT('',(3.96345182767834,-4.24326819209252,-4.37553365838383));
#2056=CARTESIAN_POINT('',(3.60351460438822,-4.24083893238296,-4.31084324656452));
#2057=CARTESIAN_POINT('',(3.42343750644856,-4.23959503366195,-4.27973701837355));
#2058=CARTESIAN_POINT('',(3.06264886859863,-4.23707557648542,-4.22045496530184));
#2059=CARTESIAN_POINT('',(2.8819368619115,-4.23579994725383,-4.19228658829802));
#2060=CARTESIAN_POINT('',(2.52035319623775,-4.23327690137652,-4.13960997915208));
#2061=CARTESIAN_POINT('',(2.33948155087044,-4.23202948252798,-4.11510146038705));
#2062=CARTESIAN_POINT('',(1.79952160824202,-4.22846742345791,-4.04851358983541));
#2063=CARTESIAN_POINT('',(1.44014875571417,-4.22631007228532,-4.01286653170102));
#2064=CARTESIAN_POINT('',(0.901209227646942,-4.22401053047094,-3.97647547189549));
#2065=CARTESIAN_POINT('',(0.721751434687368,-4.22340023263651,-3.96719243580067));
#2066=CARTESIAN_POINT('',(0.452566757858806,-4.22277990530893,-3.95784053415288));
#2067=CARTESIAN_POINT('',(0.36285690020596,-4.22262231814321,-3.95548535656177));
#2068=CARTESIAN_POINT('',(0.183433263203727,-4.22241014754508,-3.95232432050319));
#2069=CARTESIAN_POINT('',(0.0937194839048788,-4.22235556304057,-3.95151844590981));
#2070=CARTESIAN_POINT('',(-0.220207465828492,-4.22235121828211,-3.95144416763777));
#2071=CARTESIAN_POINT('',(-0.444436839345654,-4.22268126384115,-3.95629157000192));
#2072=CARTESIAN_POINT('',(-0.892816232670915,-4.22393763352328,-3.97540211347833));
#2073=CARTESIAN_POINT('',(-1.11696623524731,-4.22486404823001,-3.98966668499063));
#2074=CARTESIAN_POINT('',(-1.78947764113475,-4.22824707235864,-4.04504266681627));
#2075=CARTESIAN_POINT('',(-2.23761389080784,-4.23130704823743,-4.09873417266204));
#2076=CARTESIAN_POINT('',(-3.13429162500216,-4.23755785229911,-4.22874464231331));
#2077=CARTESIAN_POINT('',(-3.58282861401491,-4.24074911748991,-4.30514551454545));
#2078=CARTESIAN_POINT('',(-4.47866446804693,-4.2466544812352,-4.47163108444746));
#2079=CARTESIAN_POINT('',(-4.92596362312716,-4.24936870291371,-4.56171224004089));
#2080=CARTESIAN_POINT('',(-5.82614433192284,-4.25430009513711,-4.75168271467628));
#2081=CARTESIAN_POINT('',(-6.27901227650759,-4.25650944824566,-4.85169580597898));
#2082=CARTESIAN_POINT('',(-7.1840309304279,-4.26046846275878,-5.05720704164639));
#2083=CARTESIAN_POINT('',(-7.63618162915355,-4.26221811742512,-5.16270526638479));
#2084=CARTESIAN_POINT('',(-8.53900852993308,-4.26536023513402,-5.37709723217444));
#2085=CARTESIAN_POINT('',(-8.98968585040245,-4.26675342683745,-5.48598352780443));
#2086=CARTESIAN_POINT('',(-9.89062810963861,-4.26927197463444,-5.70623920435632));
#2087=CARTESIAN_POINT('',(-10.3408930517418,-4.27039733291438,-5.81760856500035));
#2088=CARTESIAN_POINT('',(-11.7409609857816,-4.2735867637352,-6.16670840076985));
#2089=CARTESIAN_POINT('',(-12.6902361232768,-4.27530549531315,-6.4074226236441));
#2090=CARTESIAN_POINT('',(-14.5886140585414,-4.2782319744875,-6.89306627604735));
#2091=CARTESIAN_POINT('',(-15.5377163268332,-4.27943938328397,-7.13799838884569));
#2092=CARTESIAN_POINT('',(-17.4119948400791,-4.28150957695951,-7.62422329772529));
#2093=CARTESIAN_POINT('',(-18.3371834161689,-4.28238013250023,-7.86545670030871));
#2094=CARTESIAN_POINT('',(-20.186614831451,-4.28391199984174,-8.34932460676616));
#2095=CARTESIAN_POINT('',(-21.1108578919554,-4.28457344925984,-8.59195808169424));
#2096=CARTESIAN_POINT('',(-22.0350059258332,-4.28517781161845,-8.83499320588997));
#2097=B_SPLINE_CURVE_WITH_KNOTS('',3,(#2053,#2054,#2055,#2056,#2057,#2058,#2059,#2060,#2061,
#2062,#2063,#2064,#2065,#2066,#2067,#2068,#2069,#2070,#2071,#2072,#2073,#2074,#2075,#2076,#2077,
#2078,#2079,#2080,#2081,#2082,#2083,#2084,#2085,#2086,#2087,#2088,#2089,#2090,#2091,#2092,#2093,
#2094,#2095,#2096),.UNSPECIFIED.,.F.,.F.,(4,2,2,2,2,2,2,2,2,2,2,2,2,2,2,2,2,2,2,2,2,4),(0.,
0.552514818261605,1.1051375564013,1.65912885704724,2.21307674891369,3.31195528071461,
3.86036374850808,4.13445781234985,4.40854902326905,5.09352626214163,5.77860756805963,
7.14964510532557,8.52568899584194,9.9013772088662,11.2971073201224,12.6928578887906,
14.0857321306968,15.4785950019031,18.4182140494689,21.3597778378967,24.2287357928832,
27.0958016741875),.UNSPECIFIED.);
#2098=EDGE_CURVE('E482',#2050,#1852,#2097,.T.);
#2099=ORIENTED_EDGE('',*,*,#2098,.T.);
#2100=EDGE_LOOP('',(#1856,#1905,#1954,#2003,#2052,#2099));
#2101=FACE_BOUND('',#2100,.T.);
#2102=ORIENTED_EDGE('',*,*,#1793,.F.);
#2103=EDGE_LOOP('',(#2102));
#2104=FACE_BOUND('',#2103,.T.);
#2105=ADVANCED_FACE('F255',(#2101,#2104),#1805,.T.);
#2106=CARTESIAN_POINT('',(4.61880215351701,0.,-3.81737471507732));
#2107=CARTESIAN_POINT('',(4.61877992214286,-7.76382004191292E-06,-3.83361341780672));
#2108=CARTESIAN_POINT('',(4.62029609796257,-6.16180478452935E-06,-3.84981475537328));
#2109=CARTESIAN_POINT('',(4.62611206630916,-7.06482131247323E-07,-3.88162213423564));
#2110=CARTESIAN_POINT('',(4.63039628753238,3.13422004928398E-06,-3.89723099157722));
#2111=CARTESIAN_POINT('',(4.64144825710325,-3.12692157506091E-06,-3.92748827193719));
#2112=CARTESIAN_POINT('',(4.64821019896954,-1.31963189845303E-05,-3.94213884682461));
#2113=CARTESIAN_POINT('',(4.66389892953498,-9.91592112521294E-06,-3.97024344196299));
#2114=CARTESIAN_POINT('',(4.67282839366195,3.46294486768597E-06,-3.98369595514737));
#2115=CARTESIAN_POINT('',(4.69342022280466,-3.78425162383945E-06,-4.01037479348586));
#2116=CARTESIAN_POINT('',(4.70525928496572,-2.76806135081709E-05,-4.02346432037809));
#2117=CARTESIAN_POINT('',(4.7307239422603,-2.18635724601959E-05,-4.04777765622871));
#2118=CARTESIAN_POINT('',(4.74435098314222,7.89346507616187E-06,-4.05899993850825));
#2119=CARTESIAN_POINT('',(4.77511235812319,-9.0490056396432E-06,-4.08096736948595));
#2120=CARTESIAN_POINT('',(4.79246809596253,-6.75788567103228E-05,-4.09140216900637));
#2121=CARTESIAN_POINT('',(4.82853216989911,-6.7145945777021E-05,-4.1095105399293));
#2122=CARTESIAN_POINT('',(4.84723818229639,-8.38060153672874E-06,-4.11718872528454));
#2123=CARTESIAN_POINT('',(4.8722256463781,2.55642870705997E-06,-4.12535456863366));
#2124=CARTESIAN_POINT('',(4.87810725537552,4.24550539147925E-07,-4.1271310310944));
#2125=CARTESIAN_POINT('',(4.88520479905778,-8.4546624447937E-08,-4.12910128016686));
#2126=CARTESIAN_POINT('',(4.88638497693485,-1.0138357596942E-07,-4.12942319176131));
#2127=CARTESIAN_POINT('',(4.88756660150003,0.,-4.12973980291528));
#2128=B_SPLINE_CURVE_WITH_KNOTS('',3,(#2106,#2107,#2108,#2109,#2110,#2111,#2112,#2113,#2114,
#2115,#2116,#2117,#2118,#2119,#2120,#2121,#2122,#2123,#2124,#2125,#2126,#2127),.UNSPECIFIED.,
.F.,.F.,(4,2,2,2,2,2,2,2,2,2,4),(0.,0.0485887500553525,0.0969065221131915,0.145111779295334,
0.193376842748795,0.246120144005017,0.298906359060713,0.359420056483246,0.41983199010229,
0.438260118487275,0.441929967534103),.UNSPECIFIED.);
#2129=EDGE_CURVE('E391',#213,#2001,#2128,.T.);
#2130=ORIENTED_EDGE('',*,*,#2129,.F.);
#2131=ORIENTED_EDGE('',*,*,#214,.F.);
#2132=CARTESIAN_POINT('',(2.30940107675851,-4.,-3.81737471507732));
#2133=CARTESIAN_POINT('',(2.30938325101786,-3.99998460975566,-3.83361342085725));
#2134=CARTESIAN_POINT('',(2.31014272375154,-4.00129685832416,-3.84981475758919));
#2135=CARTESIAN_POINT('',(2.31305542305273,-4.00633091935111,-3.88162213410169));
#2136=CARTESIAN_POINT('',(2.31520085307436,-4.01003925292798,-3.89723098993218));
#2137=CARTESIAN_POINT('',(2.32072142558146,-4.01961365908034,-3.92748827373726));
#2138=CARTESIAN_POINT('',(2.32409369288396,-4.02547468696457,-3.94213885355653));
#2139=CARTESIAN_POINT('',(2.33194089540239,-4.03905988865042,-3.9702434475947));
#2140=CARTESIAN_POINT('',(2.33641719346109,-4.04678636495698,-3.98369595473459));
#2141=CARTESIAN_POINT('',(2.34670683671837,-4.06462303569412,-4.01037479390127));
#2142=CARTESIAN_POINT('',(2.35260570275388,-4.07488788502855,-4.02346432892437));
#2143=CARTESIAN_POINT('',(2.36534306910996,-4.09693801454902,-4.04777766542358));
#2144=CARTESIAN_POINT('',(2.37218233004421,-4.10872452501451,-4.05899994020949));
#2145=CARTESIAN_POINT('',(2.38754833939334,-4.13537313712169,-4.08096736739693));
#2146=CARTESIAN_POINT('',(2.39617555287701,-4.15043288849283,-4.09140217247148));
#2147=CARTESIAN_POINT('',(2.41420796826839,-4.1816650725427,-4.10951054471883));
#2148=CARTESIAN_POINT('',(2.42361183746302,-4.19783559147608,-4.11718872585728));
#2149=CARTESIAN_POINT('',(2.43611503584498,-4.21946990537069,-4.12535456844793));
#2150=CARTESIAN_POINT('',(2.43905399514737,-4.22456459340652,-4.12713103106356));
#2151=CARTESIAN_POINT('',(2.44260232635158,-4.23071150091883,-4.12910128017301));
#2152=CARTESIAN_POINT('',(2.44319240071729,-4.23173357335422,-4.12942319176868));
#2153=CARTESIAN_POINT('',(2.44378330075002,-4.23275683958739,-4.12973980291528));
#2154=B_SPLINE_CURVE_WITH_KNOTS('',3,(#2132,#2133,#2134,#2135,#2136,#2137,#2138,#2139,#2140,
#2141,#2142,#2143,#2144,#2145,#2146,#2147,#2148,#2149,#2150,#2151,#2152,#2153),.UNSPECIFIED.,
.F.,.F.,(4,2,2,2,2,2,2,2,2,2,4),(0.,0.0485887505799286,0.0969065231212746,0.145111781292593,
0.193376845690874,0.246120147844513,0.298906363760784,0.359420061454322,0.41983199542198,
0.438260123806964,0.441929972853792),.UNSPECIFIED.);
#2155=EDGE_CURVE('E39',#2050,#29,#2154,.F.);
#2156=ORIENTED_EDGE('',*,*,#2155,.F.);
#2157=ORIENTED_EDGE('',*,*,#2051,.F.);
#2158=EDGE_LOOP('',(#2130,#2131,#2156,#2157));
#2159=FACE_BOUND('',#2158,.T.);
#2160=ADVANCED_FACE('F377',(#2159),#166,.F.);
#2161=ORIENTED_EDGE('',*,*,#2155,.T.);
#2162=ORIENTED_EDGE('',*,*,#469,.F.);
#2163=CARTESIAN_POINT('',(-2.3094010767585,-4.,-3.81737471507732));
#2164=CARTESIAN_POINT('',(-2.3093967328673,-3.99997679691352,-3.83361342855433));
#2165=CARTESIAN_POINT('',(-2.31015342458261,-4.00129065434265,-3.84981476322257));
#2166=CARTESIAN_POINT('',(-2.31305665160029,-4.00633020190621,-3.88162213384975));
#2167=CARTESIAN_POINT('',(-2.3151954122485,-4.01004240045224,-3.89723098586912));
#2168=CARTESIAN_POINT('',(-2.32072685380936,-4.01961051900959,-3.92748827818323));
#2169=CARTESIAN_POINT('',(-2.32411660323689,-4.02546142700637,-3.94213887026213));
#2170=CARTESIAN_POINT('',(-2.33195811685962,-4.03904991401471,-3.97024346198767));
#2171=CARTESIAN_POINT('',(-2.33641119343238,-4.04678982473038,-3.98369595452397));
#2172=CARTESIAN_POINT('',(-2.34671339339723,-4.06461925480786,-4.01037479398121));
#2173=CARTESIAN_POINT('',(-2.35265371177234,-4.07486014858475,-4.02346434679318));
#2174=CARTESIAN_POINT('',(-2.36538101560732,-4.09691608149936,-4.04777768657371));
#2175=CARTESIAN_POINT('',(-2.37216868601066,-4.10873239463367,-4.05899994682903));
#2176=CARTESIAN_POINT('',(-2.38756398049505,-4.13536411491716,-4.0809673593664));
#2177=CARTESIAN_POINT('',(-2.39629256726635,-4.15036533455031,-4.09140216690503));
#2178=CARTESIAN_POINT('',(-2.41432424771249,-4.18159793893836,-4.10951054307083));
#2179=CARTESIAN_POINT('',(-2.42362635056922,-4.19782721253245,-4.11718872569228));
#2180=CARTESIAN_POINT('',(-2.43611060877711,-4.21947246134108,-4.12535456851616));
#2181=CARTESIAN_POINT('',(-2.43905325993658,-4.22456501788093,-4.12713103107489));
#2182=CARTESIAN_POINT('',(-2.44260247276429,-4.23071141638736,-4.12910128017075));
#2183=CARTESIAN_POINT('',(-2.44319257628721,-4.23173347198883,-4.12942319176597));
#2184=CARTESIAN_POINT('',(-2.44378330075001,-4.2327568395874,-4.12973980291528));
#2185=B_SPLINE_CURVE_WITH_KNOTS('',3,(#2163,#2164,#2165,#2166,#2167,#2168,#2169,#2170,#2171,
#2172,#2173,#2174,#2175,#2176,#2177,#2178,#2179,#2180,#2181,#2182,#2183,#2184),.UNSPECIFIED.,
.F.,.F.,(4,2,2,2,2,2,2,2,2,2,4),(0.,0.0485887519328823,0.0969065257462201,0.145111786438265,
0.193376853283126,0.246120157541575,0.298906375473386,0.359420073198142,0.419832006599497,
0.43826013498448,0.441929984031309),.UNSPECIFIED.);
#2186=EDGE_CURVE('E367',#1852,#286,#2185,.F.);
#2187=ORIENTED_EDGE('',*,*,#2186,.F.);
#2188=ORIENTED_EDGE('',*,*,#2098,.F.);
#2189=EDGE_LOOP('',(#2161,#2162,#2187,#2188));
#2190=FACE_BOUND('',#2189,.T.);
#2191=ADVANCED_FACE('F351',(#2190),#423,.F.);
#2192=ORIENTED_EDGE('',*,*,#2129,.T.);
#2193=ORIENTED_EDGE('',*,*,#2002,.F.);
#2194=CARTESIAN_POINT('',(2.3094010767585,4.,-3.81737471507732));
#2195=CARTESIAN_POINT('',(2.309396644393,3.99997692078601,-3.83361340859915));
#2196=CARTESIAN_POINT('',(2.31015335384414,4.00129075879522,-3.849814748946));
#2197=CARTESIAN_POINT('',(2.31305664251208,4.00633022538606,-3.88162213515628));
#2198=CARTESIAN_POINT('',(2.31519544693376,4.01004236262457,-3.89723099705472));
#2199=CARTESIAN_POINT('',(2.32072681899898,4.01961055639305,-3.92748826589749));
#2200=CARTESIAN_POINT('',(2.32411645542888,4.02546160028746,-3.94213882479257));
#2201=CARTESIAN_POINT('',(2.33195799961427,4.03905006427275,-3.97024342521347));
#2202=CARTESIAN_POINT('',(2.33641122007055,4.04678981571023,-3.98369595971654));
#2203=CARTESIAN_POINT('',(2.34671336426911,4.0646192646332,-4.01037478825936));
#2204=CARTESIAN_POINT('',(2.35265344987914,4.07486036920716,-4.02346427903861));
#2205=CARTESIAN_POINT('',(2.36538077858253,4.09691629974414,-4.04777761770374));
#2206=CARTESIAN_POINT('',(2.37216870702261,4.10873239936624,-4.05899993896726));
#2207=CARTESIAN_POINT('',(2.3875639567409,4.13536411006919,-4.08096736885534));
#2208=CARTESIAN_POINT('',(2.39629215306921,4.15036559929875,-4.09140211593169));
#2209=CARTESIAN_POINT('',(2.41432381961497,4.18159822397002,-4.10951048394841));
#2210=CARTESIAN_POINT('',(2.4236262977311,4.19782724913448,-4.11718871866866));
#2211=CARTESIAN_POINT('',(2.43611062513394,4.21947245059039,-4.125354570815));
#2212=CARTESIAN_POINT('',(2.43905326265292,4.22456501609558,-4.12713103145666));
#2213=CARTESIAN_POINT('',(2.44260247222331,4.23071141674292,-4.12910128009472));
#2214=CARTESIAN_POINT('',(2.4431925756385,4.23173347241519,-4.1294231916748));
#2215=CARTESIAN_POINT('',(2.44378330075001,4.2327568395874,-4.12973980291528));
#2216=B_SPLINE_CURVE_WITH_KNOTS('',3,(#2194,#2195,#2196,#2197,#2198,#2199,#2200,#2201,#2202,
#2203,#2204,#2205,#2206,#2207,#2208,#2209,#2210,#2211,#2212,#2213,#2214,#2215),.UNSPECIFIED.,
.F.,.F.,(4,2,2,2,2,2,2,2,2,2,4),(0.,0.0485887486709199,0.0969065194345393,0.14511177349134,
0.193376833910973,0.246120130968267,0.298906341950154,0.359420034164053,0.419831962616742,
0.438260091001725,0.441929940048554),.UNSPECIFIED.);
#2217=EDGE_CURVE('E288',#1062,#1952,#2216,.T.);
#2218=ORIENTED_EDGE('',*,*,#2217,.F.);
#2219=ORIENTED_EDGE('',*,*,#1516,.F.);
#2220=EDGE_LOOP('',(#2192,#2193,#2218,#2219));
#2221=FACE_BOUND('',#2220,.T.);
#2222=ADVANCED_FACE('F346',(#2221),#1470,.F.);
#2223=ORIENTED_EDGE('',*,*,#2186,.T.);
#2224=ORIENTED_EDGE('',*,*,#749,.F.);
#2225=CARTESIAN_POINT('',(-4.61880215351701,0.,-3.81737471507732));
#2226=CARTESIAN_POINT('',(-4.6187799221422,7.7638155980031E-06,-3.83361341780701));
#2227=CARTESIAN_POINT('',(-4.62029609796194,6.16180018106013E-06,-3.84981475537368));
#2228=CARTESIAN_POINT('',(-4.6261120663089,7.06479583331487E-07,-3.88162213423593));
#2229=CARTESIAN_POINT('',(-4.63039628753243,-3.13422039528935E-06,-3.8972309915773));
#2230=CARTESIAN_POINT('',(-4.64144825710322,3.12692190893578E-06,-3.92748827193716));
#2231=CARTESIAN_POINT('',(-4.64821019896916,1.31963178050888E-05,-3.94213884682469));
#2232=CARTESIAN_POINT('',(-4.6638989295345,9.91591965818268E-06,-3.9702434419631));
#2233=CARTESIAN_POINT('',(-4.67282839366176,-3.46294510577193E-06,-3.98369595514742));
#2234=CARTESIAN_POINT('',(-4.69342022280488,3.78425187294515E-06,-4.01037479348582));
#2235=CARTESIAN_POINT('',(-4.70525928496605,2.76806128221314E-05,-4.02346432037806));
#2236=CARTESIAN_POINT('',(-4.7307239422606,2.18635715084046E-05,-4.04777765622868));
#2237=CARTESIAN_POINT('',(-4.74435098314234,-7.89346535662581E-06,-4.05899993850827));
#2238=CARTESIAN_POINT('',(-4.7751123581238,9.04900594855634E-06,-4.08096736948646));
#2239=CARTESIAN_POINT('',(-4.79246809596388,6.75788568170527E-05,-4.09140216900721));
#2240=CARTESIAN_POINT('',(-4.82853216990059,6.71459456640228E-05,-4.10951053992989));
#2241=CARTESIAN_POINT('',(-4.84723818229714,8.38060141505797E-06,-4.11718872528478));
#2242=CARTESIAN_POINT('',(-4.8722256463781,-2.55642866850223E-06,-4.12535456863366));
#2243=CARTESIAN_POINT('',(-4.87810725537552,-4.24550450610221E-07,-4.1271310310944));
#2244=CARTESIAN_POINT('',(-4.88520479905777,8.4546650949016E-08,-4.12910128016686));
#2245=CARTESIAN_POINT('',(-4.88638497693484,1.01383588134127E-07,-4.12942319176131));
#2246=CARTESIAN_POINT('',(-4.88756660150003,0.,-4.12973980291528));
#2247=B_SPLINE_CURVE_WITH_KNOTS('',3,(#2225,#2226,#2227,#2228,#2229,#2230,#2231,#2232,#2233,
#2234,#2235,#2236,#2237,#2238,#2239,#2240,#2241,#2242,#2243,#2244,#2245,#2246),.UNSPECIFIED.,
.F.,.F.,(4,2,2,2,2,2,2,2,2,2,4),(0.,0.048588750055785,0.0969065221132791,0.145111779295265,
0.193376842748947,0.24612014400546,0.29890635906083,0.359420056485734,0.419831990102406,
0.438260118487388,0.441929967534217),.UNSPECIFIED.);
#2248=EDGE_CURVE('E451',#1854,#566,#2247,.F.);
#2249=ORIENTED_EDGE('',*,*,#2248,.F.);
#2250=ORIENTED_EDGE('',*,*,#1855,.F.);
#2251=EDGE_LOOP('',(#2223,#2224,#2249,#2250));
#2252=FACE_BOUND('',#2251,.T.);
#2253=ADVANCED_FACE('F280',(#2252),#703,.F.);
#2254=ORIENTED_EDGE('',*,*,#2217,.T.);
#2255=ORIENTED_EDGE('',*,*,#1953,.F.);
#2256=CARTESIAN_POINT('',(-2.3094010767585,4.,-3.81737471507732));
#2257=CARTESIAN_POINT('',(-2.30938322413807,3.99998464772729,-3.8336134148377));
#2258=CARTESIAN_POINT('',(-2.3101427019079,4.00129689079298,-3.84981475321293));
#2259=CARTESIAN_POINT('',(-2.31305541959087,4.0063309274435,-3.88162213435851));
#2260=CARTESIAN_POINT('',(-2.31520086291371,4.01003924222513,-3.8972309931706));
#2261=CARTESIAN_POINT('',(-2.32072141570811,4.01961366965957,-3.92748827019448));
#2262=CARTESIAN_POINT('',(-2.32409365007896,4.02547473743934,-3.94213884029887));
#2263=CARTESIAN_POINT('',(-2.33194085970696,4.03905993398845,-3.9702434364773));
#2264=CARTESIAN_POINT('',(-2.33641719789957,4.04678636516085,-3.98369595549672));
#2265=CARTESIAN_POINT('',(-2.34670683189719,4.06462303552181,-4.0103747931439));
#2266=CARTESIAN_POINT('',(-2.35260563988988,4.07488793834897,-4.02346431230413));
#2267=CARTESIAN_POINT('',(-2.3653430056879,4.09693807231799,-4.04777764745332));
#2268=CARTESIAN_POINT('',(-2.37218232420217,4.10872453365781,-4.05899993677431));
#2269=CARTESIAN_POINT('',(-2.38754834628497,4.13537312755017,-4.08096737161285));
#2270=CARTESIAN_POINT('',(-2.39617549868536,4.1504329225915,-4.09140216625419));
#2271=CARTESIAN_POINT('',(-2.41420790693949,4.18166511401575,-4.10951053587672));
#2272=CARTESIAN_POINT('',(-2.42361182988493,4.19783559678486,-4.11718872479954));
#2273=CARTESIAN_POINT('',(-2.43611503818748,4.21946990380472,-4.12535456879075));
#2274=CARTESIAN_POINT('',(-2.43905399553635,4.22456459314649,-4.12713103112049));
#2275=CARTESIAN_POINT('',(-2.44260232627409,4.23071150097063,-4.12910128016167));
#2276=CARTESIAN_POINT('',(-2.44319240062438,4.23173357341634,-4.12942319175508));
#2277=CARTESIAN_POINT('',(-2.44378330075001,4.2327568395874,-4.12973980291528));
#2278=B_SPLINE_CURVE_WITH_KNOTS('',3,(#2256,#2257,#2258,#2259,#2260,#2261,#2262,#2263,#2264,
#2265,#2266,#2267,#2268,#2269,#2270,#2271,#2272,#2273,#2274,#2275,#2276,#2277),.UNSPECIFIED.,
.F.,.F.,(4,2,2,2,2,2,2,2,2,2,4),(0.,0.048588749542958,0.0969065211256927,0.14511177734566,
0.193376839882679,0.246120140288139,0.298906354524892,0.359420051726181,0.419831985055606,
0.438260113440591,0.441929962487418),.UNSPECIFIED.);
#2279=EDGE_CURVE('E263',#814,#1903,#2278,.T.);
#2280=ORIENTED_EDGE('',*,*,#2279,.F.);
#2281=ORIENTED_EDGE('',*,*,#1245,.F.);
#2282=EDGE_LOOP('',(#2254,#2255,#2280,#2281));
#2283=FACE_BOUND('',#2282,.T.);
#2284=ADVANCED_FACE('F245',(#2283),#1199,.F.);
#2285=ORIENTED_EDGE('',*,*,#2248,.T.);
#2286=ORIENTED_EDGE('',*,*,#997,.F.);
#2287=ORIENTED_EDGE('',*,*,#2279,.T.);
#2288=ORIENTED_EDGE('',*,*,#1904,.F.);
#2289=EDGE_LOOP('',(#2285,#2286,#2287,#2288));
#2290=FACE_BOUND('',#2289,.T.);
#2291=ADVANCED_FACE('F238',(#2290),#951,.F.);
#2292=CLOSED_SHELL('',(#275,#555,#803,#1051,#1331,#1570,#1598,#1615,#1622,#1634,#1641,#1648,
#1655,#1680,#1700,#1780,#1800,#2105,#2160,#2191,#2222,#2253,#2284,#2291));
#2293=MANIFOLD_SOLID_BREP('B2',#2292);
#2294=ADVANCED_BREP_SHAPE_REPRESENTATION('',(#18,#2293),#14);
#2295=SHAPE_DEFINITION_REPRESENTATION(#9,#2294);
ENDSEC;
END-ISO-10303-21;
